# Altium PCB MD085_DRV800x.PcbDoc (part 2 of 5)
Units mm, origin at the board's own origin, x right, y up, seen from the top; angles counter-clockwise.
Board outline 152.66 x 101.89 mm, 4 copper layers (Top Layer, Mid-Layer 1, Mid-Layer 2, Bottom Layer), stack 2.355 mm thick; 265 components, 148 nets, 849 pads, 1494 vias.
Unrouted connection lines stored in the file: 2.

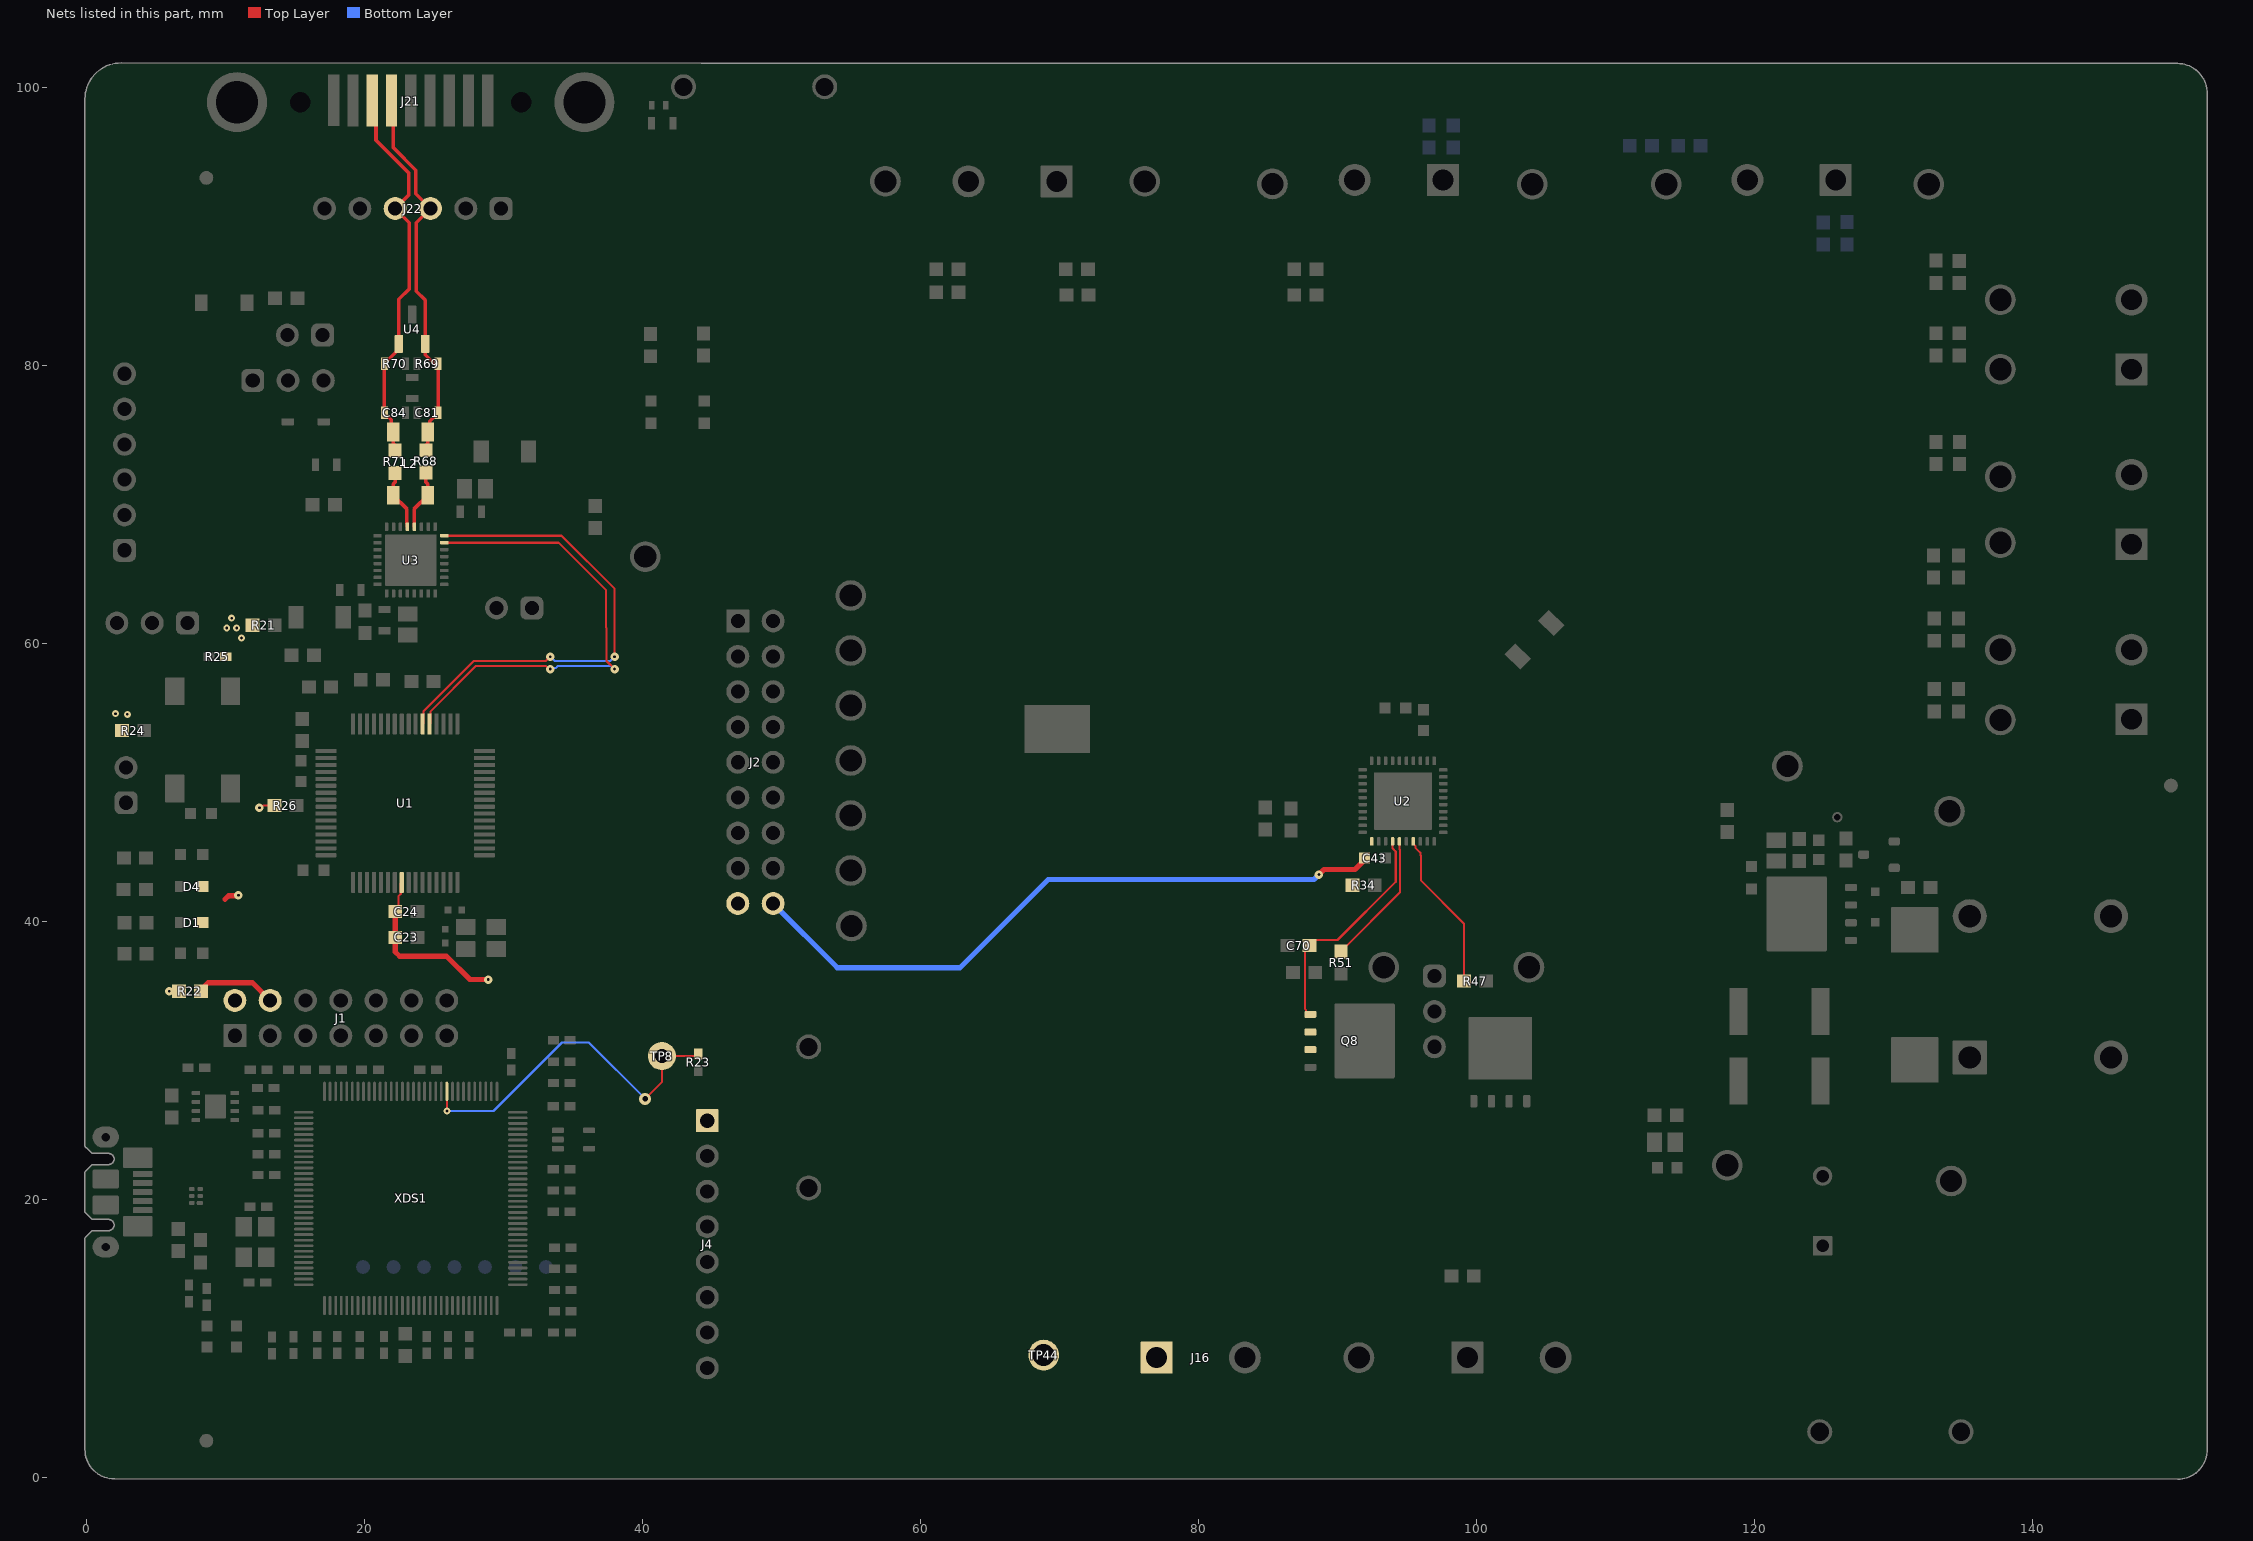
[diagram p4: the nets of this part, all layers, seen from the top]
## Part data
C1 C15: library part CMP-0006906-5, "CAP, CERM, 2.2 uF, 10 V, +/- 10%, X5R, 0603", Cap_Case=0603, Manufacturer=Kemet, Supplier Part Number 1=399-4911-1-ND, TempCo=X5R, Tolerance_%=10%, Value1=Unknown, Value2=10V, ValueDisplayed=2.2uF
C2: library part CMP-0006688-2, "CAP, CERM, 3300 pF, 50 V, +/- 10%, X7R, 0402", Cap_Case=0402, Manufacturer=MuRata, Supplier Part Number 1=490-3248-1-ND, TempCo=X7R, Tolerance_%=10%, Value1=Unknown, Value2=50V, ValueDisplayed=3300pF
C3 C10 C13 C17: library part CMP-0006276-2, "CAP, CERM, 1 uF, 25 V, +/- 10%, X5R, 0402", Cap_Case=0402, Manufacturer=TDK, Supplier Part Number 1=445-9066-1-ND, TempCo=X5R, Tolerance_%=10%, Value1=Unknown, Value2=25V, ValueDisplayed=1uF
C4: library part CMP-0006341-2, "CAP, CERM, 2.2 uF, 6.3 V, +/- 10%, X5R, 0402", Cap_Case=0402, Manufacturer=Samsung, Supplier Part Number 1=1276-1172-1-ND, TempCo=X5R, Tolerance_%=10%, Value1=Unknown, Value2=6.3V, ValueDisplayed=2.2uF
C5 C6 C7 C14 C20: library part CMP-0006658-2, "CAP, CERM, 0.01 uF, 25 V, +/- 10%, X7R, 0402", Cap_Case=0402, Manufacturer=MuRata, Supplier Part Number 1=490-1312-1-ND, TempCo=X7R, Tolerance_%=10%, Value1=Unknown, Value2=25V, ValueDisplayed=0.01uF
C8 C9 C11 C12 C16 C21 C22: library part CMP-0006623-2, "CAP, CERM, 0.1 uF, 6.3 V, +/- 10%, X7R, 0402", Cap_Case=0402, Manufacturer=MuRata, Supplier Part Number 1=GRM155R70J104KA01D-ND, TempCo=X7R, Tolerance_%=10%, Value1=Unknown, Value2=6.3V, ValueDisplayed=0.1uF
C18 C19: library part CMP-0006415-2, "CAP, CERM, 12 pF, 50 V, +/- 5%, C0G/NP0, 0402", Cap_Case=0402, Manufacturer=MuRata, Supplier Part Number 1=14T3292, TempCo=C0G/NP0, Tolerance_%=5%, Value1=Unknown, Value2=50V, ValueDisplayed=12pF
C23: library part CMP-0860569-1, "CAP, CERM, 10 µF, 25 V,+/- 10%, X5R, 0603", Cap_Case=0603, Manufacturer=MuRata, TempCo=X5R, Tolerance_%=10%, Value2=25V, ValueDisplayed=10µF
C24 C34 C37: library part CMP-0006837-4, "CAP, CERM, 0.1 uF, 50 V, +/- 10%, X7R, 0603", Cap_Case=0603, Manufacturer="Wurth Elektronik", TempCo=X7R, Tolerance_%=10%, Value1=Unknown, Value2=50V, ValueDisplayed=0.1uF
C25: library part CMP-0119380-1, "WCAP-CSGP Multilayer Ceramic Chip Capacitor, General Purpose, size 0603, X7R Class II, 470nF, 25VDC", Capacitance Tolerance=+/-10%, Case/Size Code=0603, Insulation Resistance=1.1GOhm, Manufacturer="Wurth Elektronik", Operating Temperature Max=125°C, Operating Temperature Min=-55°C, Rated Voltage (DC)=25V
C26: library part CMP-0104705-1, "WCAP-CSGP Multilayer Ceramic Chip Capacitor, General Purpose, size 0603, X7R, 10nF, 25VDC", Capacitance Tolerance=+/-10%, Case/Size Code=0603, Insulation Resistance=10GOhm, Manufacturer="Wurth Elektronik", Operating Temperature Max=125°C, Operating Temperature Min=-55°C, Rated Voltage (DC)=25V
C27: library part CMP-0115494-1, "WCAP-CSGP Multilayer Ceramic Chip Capacitor, General Purpose, size 0603, X7R, 1µF, 50VDC", Capacitance Tolerance=+/-10%, Case/Size Code=0603, Insulation Resistance=0.5GOhm, Manufacturer="Wurth Elektronik", Operating Temperature Max=125°C, Operating Temperature Min=-55°C, Rated Voltage (DC)=50V
C28 C29: library part CMP-0050268-1, "WCAP-CSGP Multilayer Ceramic Chip Capacitor, General Purpose, size 0402, NP0, 22pF, 50VDC", Capacitance Tolerance=+/-5%, Case/Size Code=0402, Insulation Resistance=10GOhm, Manufacturer="Wurth Elektronik", Operating Temperature Max=125°C, Operating Temperature Min=-55°C, Rated Voltage (DC)=50V
C33 C36: library part CMP-0750039-1, "CAP, CERM, 0.01 µF, 50 V,+/- 10%, X7R, 0603", Cap_Case=0603, Manufacturer="Wurth Elektronik", TempCo=X7R, Tolerance_%=10%, Value2=50V, ValueDisplayed=0.01µF
C35 C38: library part CMP-0007696-2, "CAP, CERM, 1 uF, 50 V, +/- 10%, X7R, 0805", Cap_Case=0805, Manufacturer="Wurth Elektronik", Supplier Part Number 1=710-885012207103, TempCo=X7R, Tolerance_%=10%, Value1=Unknown, Value2=50V, ValueDisplayed=1uF
C39: library part CMP-0087013-2, "Electrolytic Capacitor, 330 uF, 50 V, WCAP-ATG5 Series, 20%, Radial Leaded, 10 mm", Manufacturer="Wurth Electronics", Tolerance_%=20%, ValueDisplayed=330uF
C43 C46: library part CMP-0108290-1, "WCAP-CSGP Multilayer Ceramic Chip Capacitor, General Purpose, size 0603, X7R, 1µF, 25VDC", Capacitance Tolerance=+/-10%, Case/Size Code=0603, Insulation Resistance=0.5GOhm, Manufacturer="Wurth Elektronik", Operating Temperature Max=125°C, Operating Temperature Min=-55°C, Rated Voltage (DC)=25V
C44: library part CMP-0081454-1, "CAP, CERM, 10 µF, 50 V,+/- 20%, X5R, 1206", Cap_Case=1206, Manufacturer="Wurth Elektronik", TempCo=X5R, Tolerance_%=20%, Value2=50V, ValueDisplayed=10µF
C45: library part CMP-0108322-1, "WCAP-CSGP Multilayer Ceramic Chip Capacitor, General Purpose, size 0603, X7R, 100nF, 100VDC", Capacitance Tolerance=+/-10%, Case/Size Code=0603, Insulation Resistance=1GOhm, Manufacturer="Wurth Elektronik", Operating Temperature Max=125°C, Operating Temperature Min=-55°C, Rated Voltage (DC)=100V
C49 C50 C51 C52 C53 C54 C55 C56 C57 C58 C59 C60 C61 C64 C65 C66 C71 C72 C73 C87 C88 C89 C90 C91 C92: library part CMP-0006836-4, "CAP, CERM, 0.022 uF, 50 V, +/- 10%, X7R, 0603", Cap_Case=0603, Manufacturer="Wurth Elektronik", TempCo=X7R, Tolerance_%=10%, Value1=Unknown, Value2=50V, ValueDisplayed=0.022uF
C68: library part CMP-0079993-1, "CAP, CERM, 0.01 µF, 100 V,+/- 10%, X7R, 0603", Cap_Case=0603, Manufacturer="Wurth Elektronik", Supplier Part Number 1=45AC8565, TempCo=X7R, Tolerance_%=10%, Value2=100V, ValueDisplayed=0.01µF
C69: library part CMP-0080094-1, "CAP, CERM, 5100 pF, 50 V,+/- 5%, C0G/NP0, 0603", Cap_Case=0603, Manufacturer=Kemet, Supplier Part Number 1=399-9975-1-ND, TempCo=C0G/NP0, Tolerance_%=5%, Value2=50V, ValueDisplayed=5100pF
C70: library part CMP-0074687-3, "CAP, CERM, 0.22 µF, 10 V,+/- 10%, X7R, 0603", Cap_Case=0603, Manufacturer="Wurth Elektronik", Supplier Part Number 1=732-7941-1-ND, TempCo=X7R, Tolerance_%=10%, Value2=10V, ValueDisplayed=0.22µF
C74 C77 C79: library part CMP-0007044-5, "CAP, CERM, 0.1 uF, 50 V, +/- 10%, X7R, 0603", Cap_Case=0603, Manufacturer=TDK, Supplier Part Number 1=445-1314-1-ND, TempCo=X7R, Tolerance_%=10%, Value1="0.0296 ohm", Value2=50V, ValueDisplayed=0.1uF
C75 C83: library part CMP-0080701-1, "CAP, CERM, 4.7 µF, 16 V,+/- 10%, X7R, AEC-Q200 Grade 1, 0805", Cap_Case=0805, Manufacturer=TDK, Supplier Part Number 1=445-8788-1-ND, TempCo=X7R, Tolerance_%=10%, Value2=16V, ValueDisplayed=4.7µF
C76 C78: library part CMP-0008802-2, "CAP, CERM, 10 uF, 50 V, +/- 10%, X7R, 1206", Cap_Case=1206, Manufacturer=Samsung, Supplier Part Number 1=1276-6767-1-ND, TempCo=X7R, Tolerance_%=10%, Value1=Unknown, Value2=50V, ValueDisplayed=10uF
C80: library part CMP-0006776-4, "CAP, CERM, 220 pF, 50 V, +/- 1%, C0G/NP0, 0603", Cap_Case=0603, Manufacturer=AVX, Supplier Part Number 1=478-3719-1-ND, TempCo=C0G/NP0, Tolerance_%=1%, Value1="0.083 ohm", Value2=50V, ValueDisplayed=220pF
C81 C84: library part CMP-0007253-4, "CAP, CERM, 20 pF, 100 V, +/- 5%, C0G/NP0, 0603", Cap_Case=0603, Manufacturer=MuRata, Supplier Part Number 1=490-1334-1-ND, TempCo=C0G/NP0, Tolerance_%=5%, Value1=Unknown, Value2=100V, ValueDisplayed=20pF
C82: library part CMP-0006746-5, "CAP, CERM, 4700 pF, 100 V, +/- 10%, X7R, 0603", Cap_Case=0603, Manufacturer=AVX, Supplier Part Number 1=478-1203-1-ND, TempCo=X7R, Tolerance_%=10%, Value1="0.136 ohm", Value2=100V, ValueDisplayed=4700pF
C85: library part CMP-0006977-4, "CAP, CERM, 0.01 uF, 100 V, +/- 10%, X7R, 0603", Cap_Case=0603, Manufacturer=Kemet, Supplier Part Number 1=399-5347-1-ND, TempCo=X7R, Tolerance_%=10%, Value1=Unknown, Value2=100V, ValueDisplayed=0.01uF
D1 D2 D3 D6 D7 D10: library part CMP-0002894-2, "LED, Green, SMD", Color=green, Manufacturer="Wurth Elektronik", Value1=W, Value2=2V
D4: library part CMP-0002947-3, "LED, Red, SMD", Color=Red, Manufacturer="Wurth Elektronik", Power_TotalModule=72mW, Value1=0.072W, Value2=2V
D5: library part CMP-0079597-2, "Diode, Switching, 75 V, 0.15 A, AEC-Q101, SOD-323", Manufacturer="Diodes Inc.", Value1=0.15A, Value2=1.25V
D8: library part CMP-0076974-2, "Diode, Switching, 100 V, 0.15 A, SOD-123", Manufacturer="Micro Commercial Components", Value1=0.15A, Value2=1.25V
D9: library part CMP-0098376-1, "24-V, 1-Channel ESD Protection Diode", Breakdown Voltage=25.5V, Clamping Voltage=40V, Digikey Part Number=296-ESD1LIN24DYFRCT-ND, Manufacturer="Texas Instruments", Mouser Part Number=595-ESD1LIN24DYFR, Operating Temperature Range="-55°C to +150°C", ValueDisplayed=2.3pF
F1: library part CMP-0077200-3, "Fuse, 30 A, 250 VAC, 100 VDC, SMD", Irating_A=30A, Manufacturer=Littelfuse, Supplier Part Number 1=F6439CT-ND
FID1 FID2 FID3: library part CMP-0077181-1, "Fiducial mark.  There is nothing to buy or mount.", Manufacturer=N/A
H1 H2 H3 H4: library part CMP-0003620-1, "Bumpon, Hemisphere, 0.44 X 0.20, Clear", Manufacturer=3M, Supplier Part Number 1=SJ5303-7-ND
IC1: library part CMP-0043115-3, "4-Channel ESD Protection Array for High-Speed Data Interfaces, DRY0006A (USON-6)", Breakdown Voltage(Min)(V)=6, IO Capacitance(Typ)(pF)=1.6, IO Leakage Current(nA)=1, Manufacturer="Texas Instruments", Operating Temperature Range="-40 to 85 C", Rating=Catalog
IC2: library part CMP-0036329-3, "500mA, Adjustable, Low Quiescent Current, Low-Noise, High-PSRR, Single-Output LDO Regulator, DRB0008A (VSON-8)", Manufacturer="Texas Instruments", Operating Temperature Range="-40 to 125 C", Rating=Catalog
IC3: library part CMP-0032790-2, "Precision Micropower Shunt Voltage Reference, 0.5% accuracy, 2.5 V, 15 ppm / degC, 15 mA, -40 to 85 degC, 5-pin SC70 (DCK), Green (RoHS & no Sb/Br)", Manufacturer="Texas Instruments", Rating=Catalog, Temp Coeff(Max)(ppm/ degree C)=100, Temp Coeff(Typ)(ppm/ degree C)=15
J1: library part CMP-0075415-2, "Header, 100mil, 7x2, Gold, TH", Color=Black, Current_A=6.3A, Manufacturer=Samtec, Supplier Part Number 1=SAM1028-07-ND, Voltage_V=550V
J2: library part CMP-0075464-1, "Header, 100mil, 9x2, Gold, TH", Color=Black, Current_A=6.3A, Manufacturer=Samtec, Supplier Part Number 1=SAM1028-09-ND, Voltage_V=550V
J3 J18 J20: library part CMP-0075405-3, "Header, 100mil, 2x1, Gold, TH", Color=Black, Current_A=6.3A, Manufacturer=Samtec, Supplier Part Number 1=SAM1029-02-ND, Voltage_V=550V
J4: library part CMP-0075419-2, "Header, 100mil, 8x1, Gold, TH", Color=Black, Current_A=6.3A, Manufacturer=Samtec, Supplier Part Number 1=SAM1029-08-ND, Voltage_V=550V
J5: library part CMP-0086764-1, "2 Position Wire to Board Terminal Block Horizontal with Board 0.400\" (10.16mm) Through Hole", Current_A=57A, Manufacturer=Wurth, Voltage_V=750V
J6 J7 J8 J9 J16: library part CMP-0093233-2, "2 Position Wire to Board Terminal Block Horizontal with Board 0.250\" (6.35mm) Through Hole", Current_A=32A, Digikey Part Number=732-691250610002-ND, Manufacturer="Wurth Electronics", Mouser Part Number=710-691250610002, Operating Temperature Range="-32°C to +120°C", Voltage_V=450V
J10 J11 J12: library part CMP-0096350-1, "2 Position Wire to Board Terminal Block Horizontal with Board 0.197\" (5.00mm) Through Hole", Current_A=14A, Digikey Part Number=732-691216710002-ND, Manufacturer="Wurth Electronics", Mouser Part Number=710-691216710002, Operating Temperature Range="-30°C to +120°C", Voltage_V=300V
J13 J19 J23: library part CMP-0075407-2, "Header, 100mil, 3x1, Gold, TH", Color=Black, Current_A=6.3A, Manufacturer=Samtec, Supplier Part Number 1=SAM1029-03-ND, Voltage_V=550V
J17 J22: library part CMP-0075413-2, "Header, 100mil, 6x1, Gold, TH", Color=Black, Current_A=6.3A, Manufacturer=Samtec, Supplier Part Number 1=SAM1029-06-ND, Voltage_V=550V
J21: library part CMP-0074875-1, "Receptacle, D-Sub, 9 Position, R/A, SMT", Color=Black, Manufacturer=NorComp, Supplier Part Number 1=190-09FA-ND
L1: library part CMP-0087162-1, "FIXED IND 2.2UH 16A 2.2 MOHM", Manufacturer="Wurth Electronics"
L2: library part CMP-0062430-2, "Inductor, Ferrite, 100 uH, 0.15 A, 2 ohm, SMD", Manufacturer=TDK, Supplier Part Number 1=445-3959-1-ND, Value1="2 ohm", Value2=0.15A, ValueDisplayed=100uH
LBL1: library part CMP-0003625-1, "Thermal Transfer Printable Labels, 0.650\" W x 0.200\" H - 10,000 per roll", Manufacturer=Brady, Supplier Part Number 1=97C5133
LED1: library part CMP-0078131-2, "LED, Red, SMD", Color=Red, Manufacturer=Lite-On, Power_TotalModule=62.5mW, Value1=.0625W, Value2=2V
LED2: library part CMP-0002827-3, "LED, Green, SMD", Color=green, Manufacturer=Lite-On, Power_TotalModule=100mW, Value1=0.1W, Value2=2.1V
Logo1: library part CMP-0074844-1
Logo2: library part CMP-0074838-1, "Texas Instrument Corporate Signature"
Logo3: library part CMP-0074847-1, "FCC_disclaimer"
Logo4: library part CMP-0074769-3, Manufacturer="Texas Instruments"
LOGO5 LOGO7: library part CMP-0074837-2, "IEC 61010-1 Hot Surface Warning", Manufacturer="Texas Instruments"
Logo6: library part CMP-0074836-1, "IEC 61010-1 Caution Warning"
Q1: library part CMP-0000375-2, "Transistor, NPN, 65 V, 0.1 A, SOT-23", Manufacturer="ON Semiconductor", Supplier Part Number 1=BC846BLT1GOSCT-ND, Value1="0.1 A", Value2=450
Q4 Q8: library part CMP-0000713-2, "MOSFET, N-CH, 40 V, 100 A, DNK0008A (VSON-CLIP-8)", Alternate Manufacturer=None, Manufacturer="Texas Instruments", Supplier Part Number 1=CSD18512Q5B-ND, Value1=0.002, Value2="37 nC"
Q7: library part CMP-0000594-1, "MOSFET, N-CH, 30 V, 25 A, DQJ0008A (VSONP-8)", Alternate Manufacturer=None, Manufacturer="Texas Instruments", Supplier Part Number 1=CSD17579Q5A-ND, Value1=0.013, Value2="11.6 nC"
R1: library part CMP-0026731-1, "RES, 330 k, 1%, 0.0625 W, 0402", Manufacturer="Yageo America", Power_W=62.5mW, Supplier Part Number 1=311-330KLRCT-ND, TempCo="100 ppm/C", Tolerance_%=1%, Value2=0.0625W, Value_Code=330k
R2 R5 R68 R71: library part CMP-0025885-5, "RES, 0, 5%, 0.1 W, 0603", Manufacturer=Yageo, Power_W=100mW, Supplier Part Number 1=311-0.0GRCT-ND, TempCo="200 ppm/C", Tolerance_%=5%, Value2=0.1W, Value_Code=0000, ValueDisplayed=0
R3: library part CMP-0026728-1, "RES, 220 k, 1%, 0.0625 W, 0402", Manufacturer="Yageo America", Power_W=62.5mW, Supplier Part Number 1=311-220KLRCT-ND, TempCo="100 ppm/C", Tolerance_%=1%, Value2=0.0625W, Value_Code=220k
R4: library part CMP-0026695-1, "RES, 3.30 k, 1%, 0.1 W, AEC-Q200 Grade 0, 0402", Manufacturer=Panasonic, Power_W=100mW, Supplier Part Number 1=P3.30KLCT-ND, TempCo="100 ppm/C", Tolerance_%=1%, Value2=0.1W, Value_Code=3k30, ValueDisplayed=3.30k
R6: library part CMP-0026100-2, "RES, 1.00 M, 1%, 0.063 W, AEC-Q200 Grade 0, 0402", Manufacturer=Vishay-Dale, Power_W=63mW, Supplier Part Number 1=541-1.00MLCT-ND, TempCo="100 ppm/C", Tolerance_%=1%, Value2=0.063W, Value_Code=1M00, ValueDisplayed=1.00M
R7 R8 R14: library part CMP-0026825-5, "RES, 10 k, 5%, 0.063 W, AEC-Q200 Grade 0, 0402", Manufacturer=Vishay-Dale, Power_W=63mW, Supplier Part Number 1=541-10KJCT-ND, TempCo="200 ppm/C", Tolerance_%=5%, Value2=0.063W, Value_Code=10k0, ValueDisplayed=10k
R9 R10 R11 R12 R17: library part CMP-0026852-3, "RES, 1.0 k, 5%, 0.063 W, AEC-Q200 Grade 0, 0402", Manufacturer=Vishay-Dale, Power_W=63mW, Supplier Part Number 1=541-1.0KJCT-ND, TempCo="200 ppm/C", Tolerance_%=5%, Value2=0.063W, Value_Code=1k00, ValueDisplayed=1.0k
R13 R16: library part CMP-0026824-3, "RES, 100, 5%, 0.063 W, AEC-Q200 Grade 0, 0402", Manufacturer=Vishay-Dale, Power_W=63mW, Supplier Part Number 1=541-100JCT-ND, TempCo="200 ppm/C", Tolerance_%=5%, Value2=0.063W, Value_Code=100R, ValueDisplayed=100
R15: library part CMP-0026413-2, "RES, 4.87 k, 1%, 0.063 W, AEC-Q200 Grade 0, 0402", Manufacturer=Vishay-Dale, Power_W=63mW, Supplier Part Number 1=541-4.87KLCT-ND, TempCo="100 ppm/C", Tolerance_%=1%, Value2=0.063W, Value_Code=4k87, ValueDisplayed=4.87k
R18: library part CMP-0026946-3, "RES, 51, 5%, 0.063 W, AEC-Q200 Grade 0, 0402", Manufacturer=Vishay-Dale, Power_W=63mW, Supplier Part Number 1=541-51JCT-ND, TempCo="200 ppm/C", Tolerance_%=5%, Value2=0.063W, Value_Code=51R0, ValueDisplayed=51
R19 R20: library part CMP-0026934-3, "RES, 470, 5%, 0.063 W, AEC-Q200 Grade 0, 0402", Manufacturer=Vishay-Dale, Power_W=63mW, Supplier Part Number 1=541-470JCT-ND, TempCo="200 ppm/C", Tolerance_%=5%, Value2=0.063W, Value_Code=470R, ValueDisplayed=470
R21 R22 R26 R27 R34 R64: library part CMP-0025885-5, "RES, 0, 5%, 0.1 W, 0603", Manufacturer=Yageo, PartNumber=RC0603JR-070RL, Power_W=100mW, Supplier Part Number 1=311-0.0GRCT-ND, TempCo="200 ppm/C", Tolerance_%=5%, Value2=0.1W, Value_Code=0000, ValueDisplayed=0
R23 R25: library part CMP-0026935-3, "RES, 47 k, 5%, 0.063 W, AEC-Q200 Grade 0, 0402", Manufacturer=Vishay-Dale, Power_W=63mW, Supplier Part Number 1=541-47KJCT-ND, TempCo="200 ppm/C", Tolerance_%=5%, Value2=0.063W, Value_Code=47k0, ValueDisplayed=47k
R24 R43 R73 R74: library part CMP-0025918-5, "RES, 3.3 k, 5%, 0.1 W, 0603", Manufacturer=Yageo, Power_W=100mW, Supplier Part Number 1=311-3.3KGRCT-ND, TempCo="100 ppm/C", Tolerance_%=5%, Value2=0.1W, Value_Code=3k30, ValueDisplayed=3.3k
R28 R29 R30 R31 R63: library part CMP-0025912-5, "RES, 330, 5%, 0.1 W, 0603", Manufacturer=Yageo, Power_W=100mW, Supplier Part Number 1=311-330GRCT-ND, TempCo="100 ppm/C", Tolerance_%=5%, Value2=0.1W, Value_Code=330R, ValueDisplayed=330
R32 R33 R67: library part CMP-0025886-5, "RES, 10 k, 5%, 0.1 W, 0603", Manufacturer=Yageo, Power_W=100mW, Supplier Part Number 1=311-10KGRCT-ND, TempCo="100 ppm/C", Tolerance_%=5%, Value2=0.1W, Value_Code=10k0, ValueDisplayed=10k
R44: library part CMP-0025891-5, "RES, 16 k, 5%, 0.1 W, 0603", Manufacturer=Yageo, Power_W=100mW, Supplier Part Number 1=311-16KGRCT-ND, TempCo="100 ppm/C", Tolerance_%=5%, Value2=0.1W, Value_Code=16k0, ValueDisplayed=16k
R47 R65: library part CMP-0025899-5, "RES, 1.0 k, 5%, 0.1 W, 0603", Manufacturer=Yageo, Power_W=100mW, Supplier Part Number 1=311-1.0KGRCT-ND, TempCo="100 ppm/C", Tolerance_%=5%, Value2=0.1W, Value_Code=1k00, ValueDisplayed=1.0k
R51: library part CMP-0022918-5, "RES, 220, 1%, 0.1 W, 0603", Manufacturer=Yageo, Power_W=100mW, Supplier Part Number 1=311-220HRCT-ND, TempCo="100 ppm/C", Tolerance_%=1%, Value2=0.1W, Value_Code=220R, ValueDisplayed=220
R57: library part CMP-0022895-5, "RES, 1.00 k, 1%, 0.1 W, 0603", Manufacturer=Yageo, Power_W=100mW, Supplier Part Number 1=311-1.00KHRCT-ND, TempCo="100 ppm/C", Tolerance_%=1%, Value2=0.1W, Value_Code=1k00, ValueDisplayed=1.00k
R62: library part CMP-0025930-5, "RES, 560, 5%, 0.1 W, 0603", Manufacturer=Yageo, Power_W=100mW, Supplier Part Number 1=311-560GRCT-ND, TempCo="100 ppm/C", Tolerance_%=5%, Value2=0.1W, Value_Code=560R, ValueDisplayed=560
R66 R75: library part CMP-0078790-1, "RES, 0, 0.05%, 2 W, AEC-Q200 Grade 0, 2512", Manufacturer="Stackpole Electronics Inc", Power_W=2W, Supplier Part Number 1=HCJ2512ZT0R00CT-ND, Tolerance_%=0.05%, Value_Code=0
R69 R70: library part CMP-0023213-5, "RES, 60.4, 1%, 0.1 W, 0603", Manufacturer=Yageo, Power_W=100mW, Supplier Part Number 1=311-60.4HRCT-ND, TempCo="100 ppm/C", Tolerance_%=1%, Value2=0.1W, Value_Code=60R4, ValueDisplayed=60.4
R72: library part CMP-0026660-1, "RES, 1.00 M, 1%, 0.1 W, 0402", Manufacturer=Panasonic, Power_W=100mW, Supplier Part Number 1=P1.00MLCT-ND, TempCo="100 ppm/C", Tolerance_%=1%, Value2=0.1W, Value_Code=1M00, ValueDisplayed=1.00M
R76: library part CMP-0025900-5, "RES, 20 k, 5%, 0.1 W, 0603", Manufacturer=Yageo, Power_W=100mW, Supplier Part Number 1=311-20KGRCT-ND, TempCo="100 ppm/C", Tolerance_%=5%, Value2=0.1W, Value_Code=20k0, ValueDisplayed=20k
R77: library part CMP-0025898-5, "RES, 1.8 k, 5%, 0.1 W, 0603", Manufacturer=Yageo, Power_W=100mW, Supplier Part Number 1=311-1.8KGRCT-ND, TempCo="100 ppm/C", Tolerance_%=5%, Value2=0.1W, Value_Code=1k80, ValueDisplayed=1.8k
S1: library part CMP-0097347-1, "Tactile Switch SPST-NO Top Actuated Surface Mount", Coil Resistance_ohm=100mΩ, Contact Current Rating=50mA, Digikey Part Number=732-7022-1-ND, Manufacturer="Wurth Electronics", Mouser Part Number=710-430481025816, Operating Force=160gf, Operating Temperature Range="-40°C to +85°C"
SH1 SH2 SH3: library part CMP-0075110-1, "1mm Uninsulated Shorting Plug, 10.16mm spacing, TH", Manufacturer=Harwin, PartNumber=D3082-05, Supplier Part Number 1=952-1873-ND
SH-J1 SH-J2 SH-J3 SH-J4 SH-J5 SH-J6 SH-J7 SH-J8 SH-J9 SH-J10 SH-J14 SH-J15 SH-J16 SH-J17 SH-J18 SH-J19 SH-J20 SH-J21: library part CMP-0003761-2, "Shunt, 2.54mm, Gold, Black", Manufacturer="Wurth Elektronik", Supplier Part Number 1=732-2678-ND
TP1 TP2 TP3 TP4 TP5 TP6 TP7: library part CMP-0003825-1, "1mm Test Point, SMT", Manufacturer=Any, PartNumber=TP_SM_1MM
TP8: library part CMP-0055139-2, "Test Point, Miniature, White, TH", Color=White, Manufacturer="Keystone Electronics", Supplier Part Number 1=36-5002-ND
TP10 TP11 TP12 TP13 TP14 TP15 TP19 TP31 TP32 TP33 TP34 TP35 TP36 TP37 TP38 TP39 TP40 TP41 TP42 TP44 TP46 TP47 TP48 TP49: library part CMP-0055149-2, "Test Point, Multipurpose, White, TH", Color=White, Manufacturer="Keystone Electronics", Supplier Part Number 1=36-5012-ND
TP16: library part CMP-0055153-2, "Test Point, Compact, SMT", Manufacturer="Keystone Electronics", Supplier Part Number 1=36-5016TR-ND
TP20 TP21: library part CMP-0055147-2, "Test Point, Multipurpose, Red, TH", Color=Red, Manufacturer="Keystone Electronics", Supplier Part Number 1=36-5010-ND
TP25 TP26: library part CMP-0055148-2, "Test Point, Multipurpose, Black, TH", Color=Black, Manufacturer="Keystone Electronics", Supplier Part Number 1=36-5011-ND
TP30: library part CMP-0003719-1, "Testpoint", Manufacturer="Texas Instruments"
U1: library part CMP-0093960-1, "Mixed-Signal Microcontrollers With CAN-FD Interface LQFP64", Frequency_Fixed=80MHz, Manufacturer="Texas Instruments", Max Supply Voltage=3.6V, Min Supply Voltage=1.62V, Operating Temperature Range="-40°C to +125°C"
U2: library part CMP-0121851-2, "Automotive Multi-function Driver with Integrated Half-bridges &HighSide and Current Sensing & Advanced Diagnostics", Manufacturer="Texas Instruments", Max Supply Voltage=35V, Min Supply Voltage=4.5V, Operating Temperature Range="-40°C to +150°C"
U3: library part CMP-0093295-1, "CAN FD and LIN System Basis Chip (SBC) with Integrated Watchdog, Selective Wake and Advanced CAN Bus Fault Diagnostics", Manufacturer="Texas Instruments", Max Supply Voltage=28V, Min Supply Voltage=4.5V, Operating Temperature Range="-40°C to +150°C"
U4: library part CMP-0093261-1, "24-V, 2-Channel ESD Protection Diode for In-Vehicle Networks", Breakdown Voltage=25.5V, Clamping Voltage=32V, Manufacturer="Texas Instruments", Operating Temperature Range="-55°C to +150°C", ValueDisplayed=3pF
USB1: library part CMP-0055311-1, "Receptacle, USB 2.0, Micro B, 5 Position, R/A, SMT", Color=Black, Current_A=1.8A, Manufacturer=Molex, Supplier Part Number 1=WM11263CT-ND, Voltage_V=30V
XDS1: library part CMP-0077954-1, "MSP432E401YTPDT, PDT0128A (TQFP-128)", Alternate Manufacturer="Texas Instruments", Alternate PartNumber=MSP432E401YTPDT
Y1: library part CMP-0004635-3, "Crystal, 16 MHz, 8pF, SMD", Frequency Stability=+/-30ppm, Frequency_Fixed=16MHz, Manufacturer=NDK, Supplier Part Number 1=644-1157-1-ND
Y2: library part CMP-0098168-2, "Crystal 40MHz ±10ppm (Tol) ±20ppm (Stability) 12pF FUND 40Ohm 4-Pin Mini-CSMD T/R", Frequency Stability=20ppm, Frequency Tolerance=10ppm, Frequency_Fixed=40MHz, Load Capacitance=12pF, Manufacturer="Seiko Epson", Operating Temperature Range="-40°C to +105°C"
ZZ1: library part CMP-0003616-3
ZZ2: library part CMP-0077236-1
ZZ3: library part CMP-0077237-1
ZZ4: library part CMP-0077238-1

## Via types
v1: diameter 0.5, hole 0.2, Top Layer to Bottom Layer, tented both sides, 1346 vias
v2: diameter 0.61, hole 0.2, Top Layer to Bottom Layer, tented both sides, 54 vias
v3: diameter 0.508, hole 0.203, Top Layer to Bottom Layer, tented both sides, 46 vias
v4: diameter 0.5, hole 0.2, Top Layer to Bottom Layer, 16 vias
v5: diameter 0.864, hole 0.406, Top Layer to Bottom Layer, tented both sides, 15 vias
v6: diameter 0.711, hole 0.356, Top Layer to Bottom Layer, tented both sides, 10 vias
v7: diameter 5, hole 4.3, Top Layer to Bottom Layer, 3 vias
v8: diameter 0.61, hole 0.203, Top Layer to Bottom Layer, tented both sides, 3 vias
v9: diameter 5, hole 4.5, Top Layer to Bottom Layer, 1 vias

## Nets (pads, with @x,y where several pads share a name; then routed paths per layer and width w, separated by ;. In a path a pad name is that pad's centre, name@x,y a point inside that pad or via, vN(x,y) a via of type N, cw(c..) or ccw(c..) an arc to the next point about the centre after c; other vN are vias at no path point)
3V3: J1.4 R22.1 | length 5.9
  Top Layer w0.381: R22.1@8.13,34.992 8.13,35.017 8.339,35.227 8.364,35.227 8.737,35.6 11.928,35.6 J1.4@13.198,34.33
3V3_MCU: C23.1 C24.1 D1.2 D4.2 J2.17 J4.1 R21.1 R22.2 R24.2 R25.2 R26.1 U1.40 | length 15.8
  Top Layer w0.152: v2(12.426,48.188) 12.55,48.188 12.701,48.339 R26.1@13.596,48.339 ; C24.1@22.195,40.714 22.418,40.937 22.418,41.809 22.588,41.979 22.588,42.051 22.588,42.74 U1.40@22.662,42.814
  Top Layer w0.381: v2(5.945,34.992) R22.2@6.73,34.992 ; 9.953,41.605 10.194,41.846 10.868,41.846 v2(10.912,41.889) ; C24.1@22.195,40.714 22.195,37.822 22.514,37.503 25.887,37.503 27.561,35.828 v2(28.885,35.828)
  other v1: 2.923,54.908 2.075,54.954 11.142,60.397 10.075,61.108 10.787,61.108 10.431,61.82
+5V: J1.2
BSL_INVOKE: R23.2 TP8.1 XDS1.42 | length 25.6
  Top Layer w0.152: XDS1.42@25.907,27.78 25.907,26.389 v1(25.924,26.372) ; v5(40.177,27.246) 41.377,28.446 TP8.1@41.377,30.328 43.82,30.328 R23.2@43.979,30.486
  Bottom Layer w0.152: v1(25.924,26.372) 29.258,26.372 34.19,31.304 36.12,31.304 v5(40.177,27.246)
CAN_RX: U1.6 U3.24 | length 35.3
  Top Layer w0.152: U1.6@24.162,54.214 24.236,54.288 24.236,55.148 27.835,58.747 33.027,58.747 33.335,59.055 v2(33.345,59.055) ; U3.24@25.72,67.753 34.155,67.753 37.972,63.936 v2(37.972,59.055)
  Bottom Layer w0.152: v2(33.345,59.055) 33.355,59.055 33.663,58.747 37.654,58.747 37.962,59.055 v2(37.972,59.055)
CAN_TX: U1.5 U3.23 | length 34.8
  Top Layer w0.152: U1.5@24.662,54.214 24.736,54.288 24.736,55.123 28.007,58.395 33.027,58.395 33.255,58.166 v2(33.345,58.166) ; U3.23@25.72,67.253 33.948,67.253 37.341,63.86 37.341,61.161 37.391,61.11 37.391,58.747 v2(37.972,58.166)
  Bottom Layer w0.152: v2(33.345,58.166) 33.408,58.229 33.731,58.229 33.896,58.395 37.654,58.395 37.883,58.166 v2(37.972,58.166)
CANH: L2.2 R68.1 U3.28 | length 4.4
  Top Layer w0.254: U3.28@23.57,68.403 23.57,68.83 23.545,68.855 23.545,69.673 L2.2@24.541,70.669 24.541,71.471 24.398,71.615 R68.1@24.398,72.342
CANH_BUS: C81.1 J21.7 J22.3 L2.3 R68.2 R69.2 U4.2 | length 27.7
  Top Layer w0.254: J21.7@22.066,99.033 22.066,95.663 23.673,94.056 23.673,92.344 J22.3@24.729,91.288 23.713,90.272 23.713,85.349 24.356,84.705 U4.2@24.356,81.558 24.356,80.781 25.275,79.862 C81.1@25.275,76.608 24.668,76.001 24.668,75.346 L2.3@24.541,75.219 24.541,74.417 24.398,74.274 R68.2@24.398,73.866
CANL: L2.1 R71.1 U3.29 | length 4.4
  Top Layer w0.254: R71.1@22.185,72.318 22.185,71.615 22.041,71.471 L2.1@22.041,70.669 23.037,69.673 23.037,68.644 23.062,68.619 U3.29@23.062,68.403
CANL_BUS: C84.2 J21.2 J22.4 L2.4 R70.1 R71.2 U4.1 | length 28.1
  Top Layer w0.254: J21.2@20.682,99.033 20.809,98.906 20.809,96.202 23.165,93.846 23.165,92.263 J22.4@22.189,91.288 23.205,90.272 23.205,85.501 22.456,84.752 U4.1@22.456,81.558 22.329,81.431 22.329,81.048 R70.1@21.407,80.125 C84.2@21.407,76.608 21.914,76.1 21.914,75.346 L2.4@22.041,75.219 22.041,74.417 22.185,74.274 R71.2@22.185,73.842
DVDD: C43.2 J2.18 R34.2 U2.21 | length 47.8
  Top Layer w0.381: v2(88.633,43.376) 89.005,43.747 91.236,43.747 C43.2@92.032,44.543
  Bottom Layer w0.381: J2.18@49.378,41.297 53.997,36.677 62.812,36.677 69.163,43.029 88.287,43.029 v2(88.633,43.376)
ECDRV: R51.1 U2.25 | length 9.7
  Top Layer w0.152: R51.1@90.233,37.843 90.233,37.868 94.466,42.101 94.466,45.164 94.432,45.198 U2.25@94.432,45.765
ECFB: C70.1 J16.1 Q8.1 Q8.2 Q8.3 TP44.1 U2.24 | length 16.4
  Top Layer w0.152: Q8.1@88.024,33.323 87.878,33.323 87.701,33.5 87.701,33.646 87.641,33.706 87.641,37.943 88.37,38.672 89.97,38.672 94.161,42.863 94.161,45.038 94.027,45.172 94.022,45.172 93.932,45.261 U2.24@93.932,45.765
GH_HS: R47.2 U2.27 | length 11.5
  Top Layer w0.152: U2.27@95.432,45.765 95.432,45.59 95.579,45.443 95.579,45.313 95.932,44.959 95.932,44.865 cw(c95.308,44.65) 95.968,44.65 95.968,42.958 99.077,39.85 R47.2@99.077,35.72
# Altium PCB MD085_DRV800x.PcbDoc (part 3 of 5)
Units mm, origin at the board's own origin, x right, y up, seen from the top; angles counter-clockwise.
Board outline 152.66 x 101.89 mm, 4 copper layers (Top Layer, Mid-Layer 1, Mid-Layer 2, Bottom Layer), stack 2.355 mm thick; 265 components, 148 nets, 849 pads, 1494 vias.
Unrouted connection lines stored in the file: 2.

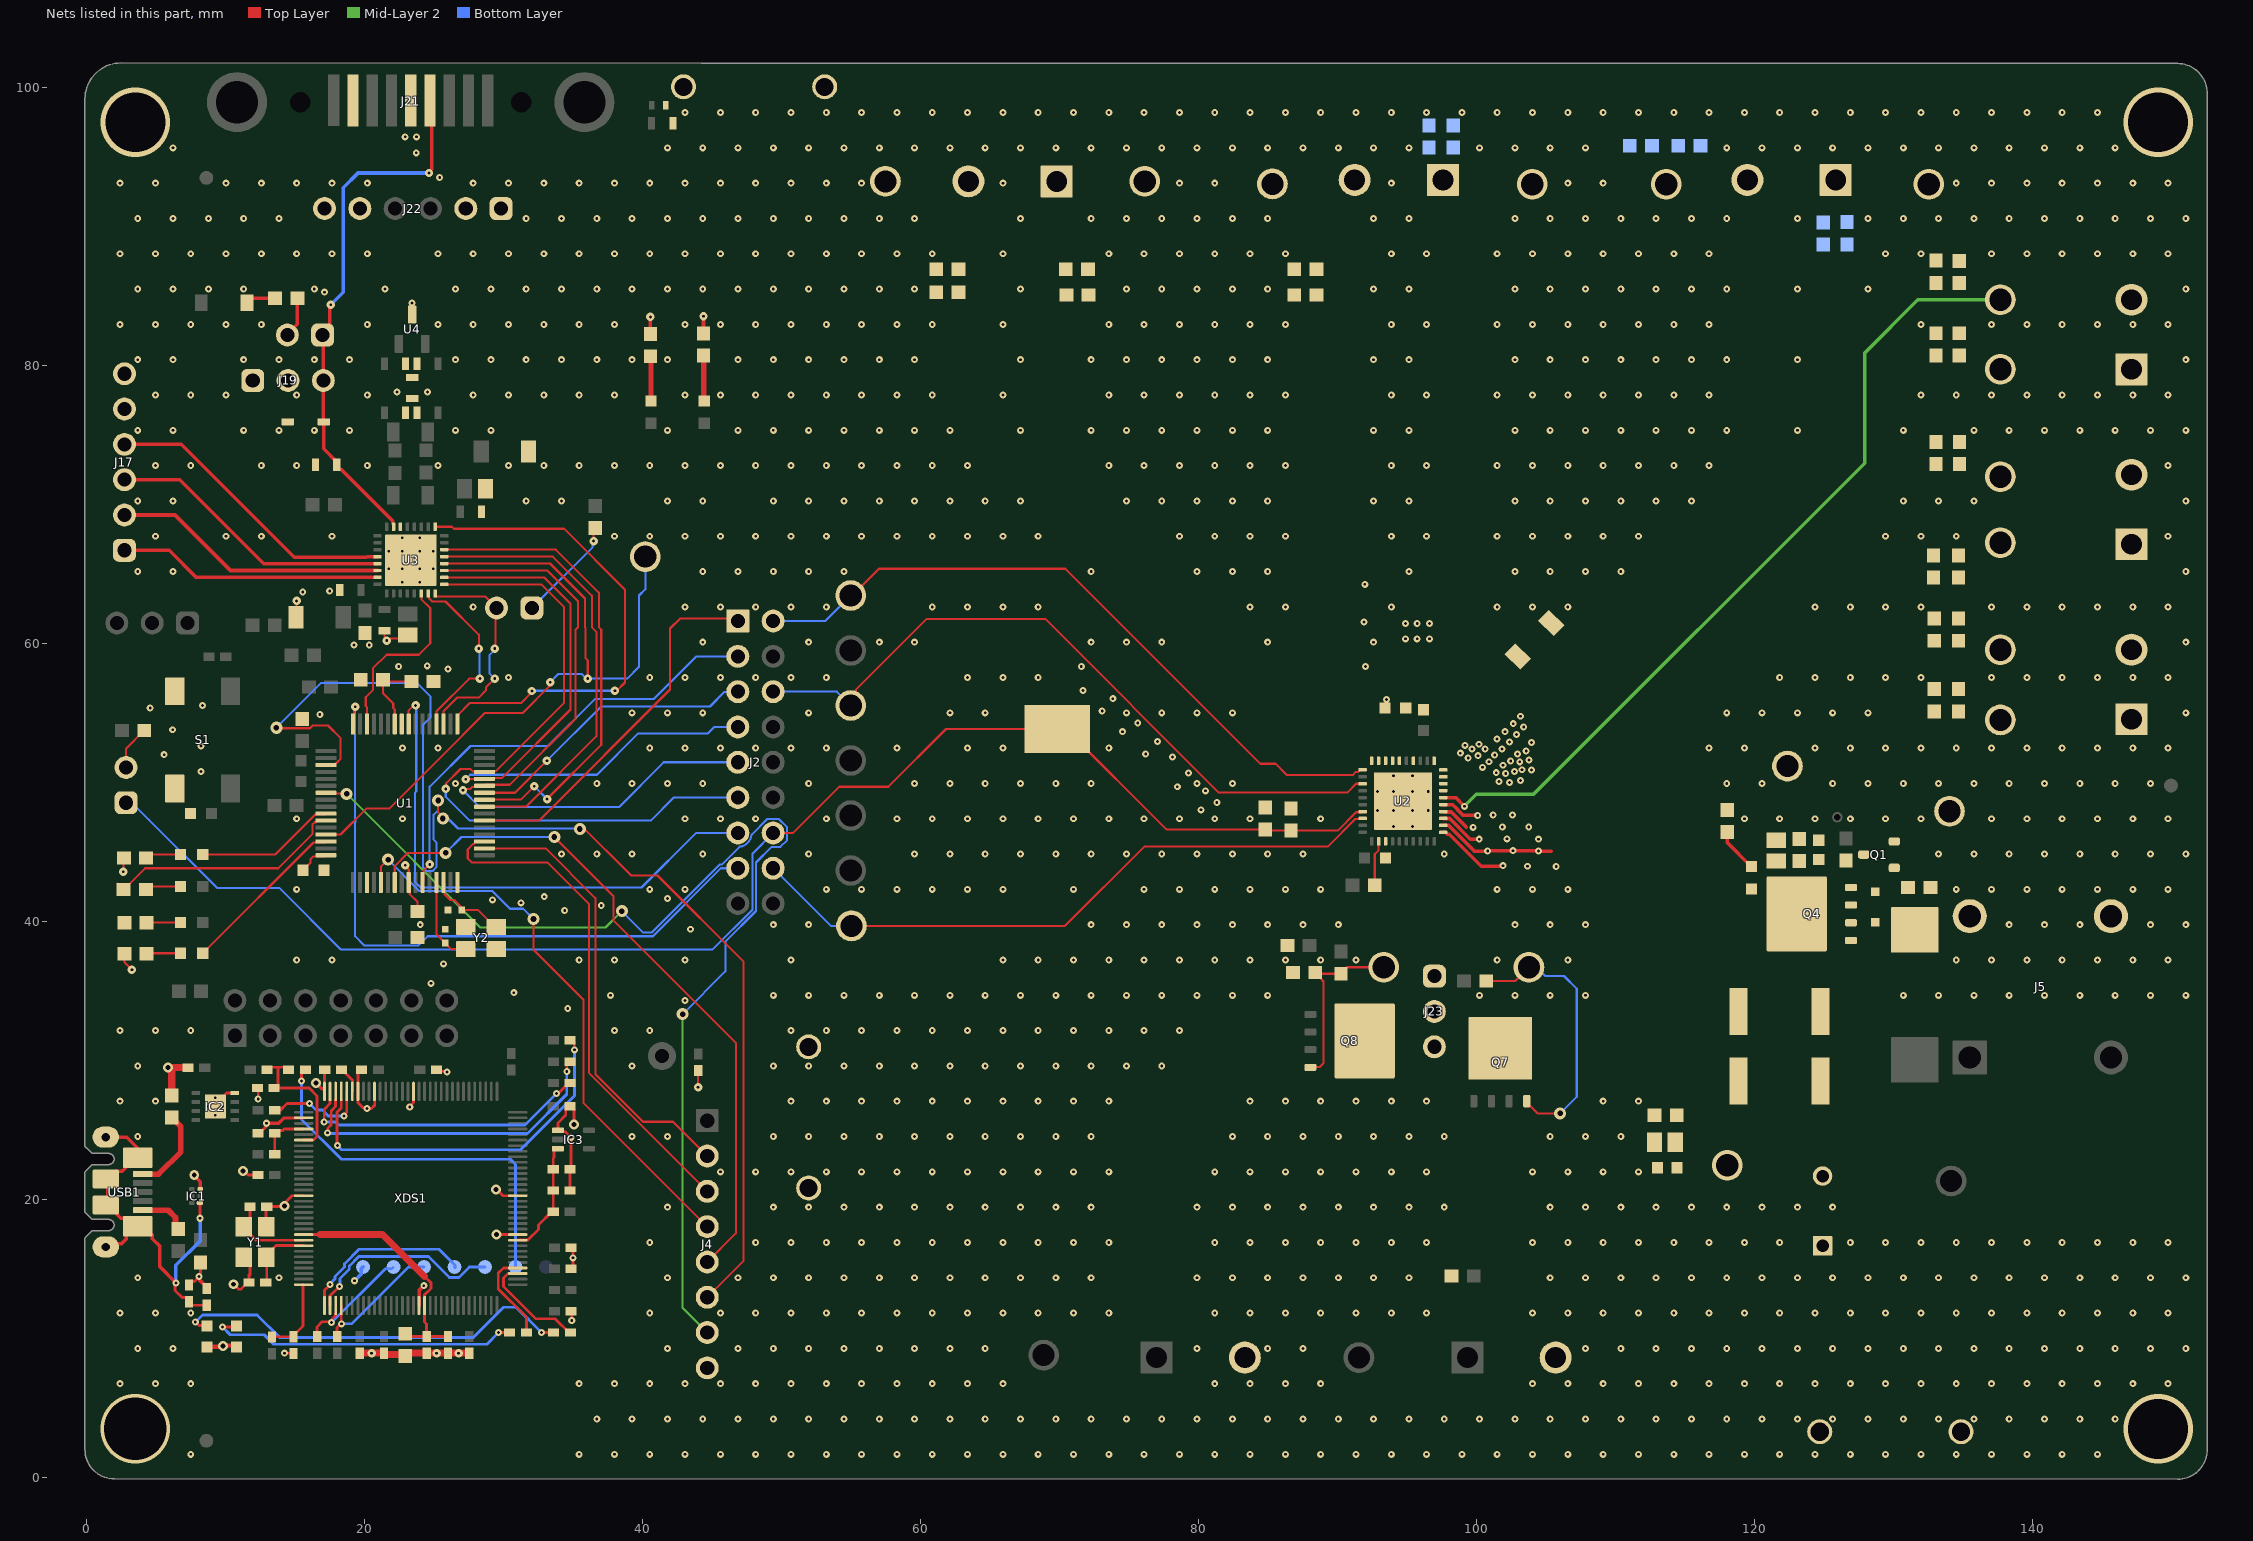
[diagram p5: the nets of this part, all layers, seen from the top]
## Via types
v1: diameter 0.5, hole 0.2, Top Layer to Bottom Layer, tented both sides, 1346 vias
v2: diameter 0.61, hole 0.2, Top Layer to Bottom Layer, tented both sides, 54 vias
v3: diameter 0.508, hole 0.203, Top Layer to Bottom Layer, tented both sides, 46 vias
v4: diameter 0.5, hole 0.2, Top Layer to Bottom Layer, 16 vias
v5: diameter 0.864, hole 0.406, Top Layer to Bottom Layer, tented both sides, 15 vias
v6: diameter 0.711, hole 0.356, Top Layer to Bottom Layer, tented both sides, 10 vias
v7: diameter 5, hole 4.3, Top Layer to Bottom Layer, 3 vias
v8: diameter 0.61, hole 0.203, Top Layer to Bottom Layer, tented both sides, 3 vias
v9: diameter 5, hole 4.5, Top Layer to Bottom Layer, 1 vias

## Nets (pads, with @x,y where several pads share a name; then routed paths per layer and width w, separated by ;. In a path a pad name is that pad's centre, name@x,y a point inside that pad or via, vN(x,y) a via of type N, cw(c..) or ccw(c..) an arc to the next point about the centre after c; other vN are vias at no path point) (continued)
GND: C1.2 C2.2 C3.2 C4.2 C5.2 C6.2 C7.2 C8.2 C9.2 C10.2 C11.2 C12.2 C13.2 C14.2 C15.2 C16.2 C17.2 C18.2 C19.2 C20.2 C21.2 C22.2 C23.2 C24.2 C25.1 C26.1 C28.1 C29.1 C33.2 C34.2 C35.2 C36.2 C37.2 C38.2 C39.1 C43.1 C44.2 C45.1 C49.1 C50.1 C51.1 C52.1 C53.1 C54.1 C55.1 C56.1 C57.1 C58.1 C59.1 C60.1 C61.1 C64.1 C65.1 C66.1 C68.2 C69.2 C70.2 C71.1 C72.1 C73.1 C74.2 C75.2 C76.2 C77.2 C78.2 C79.2 C80.2 C81.2 C82.1 C83.2 C84.1 C85.2 C87.1 C88.1 C89.1 C90.1 C91.1 C92.1 D9.2 IC1.3 IC2.4 IC2.9 IC3.1 J4.8 J5.2 J9.2 J16.2 J17.5 J17.6 J19.1 J19.2 J21.3 J21.6 J22.1 J22.2 J22.5 J22.6 LED1.2 LED2.2 R2.2 R3.1 R6.1 R15.1 R23.1 R27.1 R28.1 R29.1 R30.1 R33.1 R44.1 R57.1 R62.1 R63.1 R72.1 R77.1 S1.3 S1.4 SH1.1 SH1.2 SH2.1 SH2.2 SH3.1 SH3.2 TP1.1 TP25.1 TP26.1 U1.41 U2.8 U2.23 U2.39 U2.41 U3.30 U3.33 U4.3 XDS1.10 XDS1.17 XDS1.48 XDS1.55 XDS1.58 XDS1.64 XDS1.66 XDS1.80 XDS1.114 Y1.2 Y1.4 Y2.2 Y2.4 | length 77.4
  Top Layer w0.152: v2(2.634,43.577) 2.634,44.538 R29.1@2.677,44.582 ; R30.1@2.715,37.689 2.715,37.069 v2(3.25,36.534) ; C76.2@15.058,61.893 15.1,61.935 v2(15.1,63.066) ; C77.2@21.426,60.919 21.426,60.374 v2(21.59,60.21) 21.714,60.21 21.871,60.368 22.858,60.368 C75.2@23.108,60.618 ; v2(22.907,44.05) 22.907,44.004 23.162,43.749 U1.41@23.162,42.814 23.236,42.74 23.236,41.977 23.795,41.417 C24.2@23.795,40.714 ; U4.3@23.406,83.862 v1(23.406,84.496) ; C83.2@28.393,70.842 C83.2@28.681,71.131 C83.2@28.681,71.281 ; C78.2@31.304,73.086 31.778,73.559 C78.2@31.778,73.809 ; v2(43.979,28.086) R23.1@43.979,29.286 ; C45.1@93.387,55.361 93.501,55.476 v1(93.501,55.974) ; C45.1@93.437,55.361 C45.1@93.725,55.073
  Top Layer w0.203: R6.1@7.555,13.603 7.356,13.802 R6.1@7.356,13.848 R6.1@7.356,13.886 ; R6.1@7.645,14.146 7.555,14.146 7.356,13.948 R6.1@7.356,13.886 ; v3@8.027,14.529 8.182,14.683 C1.2@8.182,15.488 ; v3(8.089,14.467) 7.706,14.084 7.555,14.084 R6.1@7.356,13.886 ; v4(9.253,27.321) 9.753,27.321 9.902,27.469 9.902,27.524 10.048,27.671 IC2.4@10.653,27.671 ; v6(10.564,13.908) 10.572,13.908 10.924,13.556 11.093,13.556 11.579,14.042 C19.2@11.679,14.042 11.679,14.592 ; v6(11.242,22.062) 11.334,22.062 11.624,21.772 C5.2@12.329,21.772 ; Y1.4@11.395,16.19 11.395,15.801 11.753,15.443 11.753,14.592 ; C12.2@12.273,28.03 12.335,27.968 v3(12.335,27.243) ; C22.2@12.329,24.78 12.429,24.78 12.886,25.237 12.886,25.432 v3(12.944,25.491) v3@12.886,25.549 ; Y1.2@12.907,18.089 12.907,19.442 C18.2@12.953,19.488 12.974,19.509 14.203,19.509 v6(14.225,19.53) 14.322,19.627 14.322,19.832 14.77,20.28 XDS1.80@15.607,20.28 ; 14.163,25.872 14.172,25.88 XDS1.66@15.607,25.88 ; v3(14.225,8.949) 14.866,8.949 C11.2@14.88,8.935 ; XDS1.64@17.107,27.78 XDS1.64@17.107,27.978 ; XDS1.64@17.107,28.379 R15.1@17.107,29.323 ; C7.2@19.742,29.482 19.717,29.482 19.519,29.283 19.519,27.169 19.521,27.167 19.521,26.966 19.879,26.607 20.112,26.607 v3(20.17,26.549) 20.171,26.55 20.481,26.55 20.719,26.788 20.719,27.172 XDS1.55@20.709,27.182 ; v3(23.236,26.652) 23.236,26.707 23.507,26.978 XDS1.48@23.507,27.78 ; C6.2@25.157,29.336 25.261,29.232 25.865,29.232 v3(25.924,29.174) ; v6@29.48,17.489 XDS1.10@31.018,17.489 ; v6@29.51,20.715 29.945,20.28 XDS1.17@31.007,20.28 ; C20.2@34.756,20.651 C21.2@34.756,22.174 34.844,22.262 v3(34.844,24.479) 34.449,24.874 33.99,24.874 IC3.1@33.892,24.972 33.892,25.508 34.458,26.074 34.458,26.511 34.656,26.709 C14.2@34.756,26.709 34.844,26.709 35.042,26.511 v6(35.042,25.414) ; R3.1@34.844,11.976 34.89,11.931 v3(34.89,11.292) ; C8.2@34.844,15.022 34.991,15.17 v3(34.991,15.813) 34.991,16.398 C13.2@34.844,16.545
  Top Layer w0.254: v6(7.737,21.757) 7.737,21.72 8.164,21.293 IC1.3@8.164,20.758 ; v3(8.089,14.467) 8.118,14.438 8.118,14.212 8.626,13.703 C2.2@8.626,13.603 ; v3(12.944,25.491) 13.8,25.491 14.172,25.863 ; v6(16.5,28.386) 16.909,27.978 XDS1.64@17.08,27.978 ; XDS1.114@23.907,12.38 23.907,13.461 24.247,13.801 v3(24.247,13.807) ; v6(29.429,20.715) v6@29.51,20.715 ; v2(40.553,83.492) 40.553,82.273 R63.1@40.566,82.261 ; R62.1@44.368,82.311 v2(44.368,83.542)
  Top Layer w0.305: LED1.2@8.753,9.349 8.81,9.406 9.738,9.406 v6(9.795,9.463) 9.838,9.506 10.742,9.506 LED2.2@10.785,9.549
  Top Layer w0.508: R2.2@6.117,27.496 6.117,29.189 5.858,29.449 v6(5.858,29.504) 5.869,29.493 7.278,29.493 C3.2@7.29,29.482 ; C9.2@19.637,8.949 v8(20.49,8.949) C10.2@21.387,8.949 21.387,8.895 21.433,8.849 22.819,8.849 C15.2@22.919,8.749 ; C15.2@22.919,8.949 C16.2@24.452,8.949 v8(25.168,8.949) C17.2@25.985,8.949 v8(26.749,8.949) C4.2@27.519,8.949
  Bottom Layer w0.254: v3(19.269,14.162) 19.736,14.629 19.736,15.01 TP1.1@19.878,15.153
  other v1: 7.483,1.676 35.423,1.676 37.963,1.676 40.503,1.676 43.043,1.676 45.583,1.676 48.123,1.676 50.663,1.676 53.203,1.676 55.743,1.676 58.283,1.676 60.823,1.676 63.363,1.676 65.903,1.676 68.443,1.676 70.983,1.676 73.523,1.676 76.063,1.676 78.603,1.676 81.143,1.676 83.683,1.676 86.223,1.676 88.763,1.676 91.303,1.676 93.843,1.676 96.383,1.676 98.923,1.676 101.463,1.676 104.003,1.676 106.543,1.676 109.083,1.676 111.623,1.676 114.163,1.676 116.703,1.676 119.243,1.676 121.783,1.676 124.323,1.676 126.863,1.676 129.403,1.676 131.943,1.676 134.483,1.676 137.023,1.676 139.563,1.676 142.103,1.676 144.643,1.676 36.693,4.216 39.233,4.216 41.773,4.216 44.313,4.216 46.853,4.216 49.393,4.216 51.933,4.216 54.473,4.216 57.013,4.216 59.553,4.216 62.093,4.216 64.633,4.216 67.173,4.216 69.713,4.216 72.253,4.216 74.793,4.216 77.333,4.216 79.873,4.216 82.413,4.216 84.953,4.216 87.493,4.216 90.033,4.216 92.573,4.216 95.113,4.216 97.653,4.216 100.193,4.216 102.733,4.216 105.273,4.216 107.813,4.216 110.353,4.216 112.893,4.216 115.433,4.216 117.973,4.216 120.513,4.216 123.053,4.216 125.593,4.216 128.133,4.216 130.673,4.216 133.213,4.216 135.753,4.216 138.293,4.216 140.833,4.216 143.373,4.216 145.913,4.216 2.403,6.756 4.943,6.756 7.483,6.756 35.423,6.756 37.963,6.756 40.503,6.756 43.043,6.756 45.583,6.756 48.123,6.756 50.663,6.756 53.203,6.756 55.743,6.756 58.283,6.756 60.823,6.756 63.363,6.756 65.903,6.756 81.143,6.756 83.683,6.756 86.223,6.756 88.763,6.756 104.003,6.756 106.543,6.756 109.083,6.756 111.623,6.756 114.163,6.756 116.703,6.756 119.243,6.756 121.783,6.756 124.323,6.756 126.863,6.756 129.403,6.756 131.943,6.756 134.483,6.756 137.023,6.756 139.563,6.756 142.103,6.756 144.643,6.756 147.183,6.756 149.723,6.756 3.673,9.296 6.213,9.296 41.773,9.296 46.853,9.296 49.393,9.296 51.933,9.296 54.473,9.296 57.013,9.296 59.553,9.296 62.093,9.296 64.633,9.296 79.873,9.296 84.953,9.296 87.493,9.296 107.813,9.296 110.353,9.296 112.893,9.296 115.433,9.296 117.973,9.296 120.513,9.296 123.053,9.296 125.593,9.296 128.133,9.296 130.673,9.296 133.213,9.296 135.753,9.296 138.293,9.296 140.833,9.296 143.373,9.296 145.913,9.296 148.453,9.296 150.993,9.296 2.403,11.836 4.943,11.836 7.483,11.836 40.503,11.836 45.583,11.836 48.123,11.836 50.663,11.836 53.203,11.836 55.743,11.836 58.283,11.836 60.823,11.836 63.363,11.836 65.903,11.836 68.443,11.836 70.983,11.836 73.523,11.836 81.143,11.836 83.683,11.836 86.223,11.836 88.763,11.836 91.303,11.836 93.843,11.836 96.383,11.836 104.003,11.836 106.543,11.836 109.083,11.836 111.623,11.836 114.163,11.836 116.703,11.836 119.243,11.836 121.783,11.836 124.323,11.836 126.863,11.836 129.403,11.836 131.943,11.836 134.483,11.836 137.023,11.836 139.563,11.836 142.103,11.836 144.643,11.836 147.183,11.836 149.723,11.836 3.673,14.376 13.833,14.376 41.773,14.376 46.853,14.376 49.393,14.376 51.933,14.376 54.473,14.376 57.013,14.376 59.553,14.376 62.093,14.376 64.633,14.376 67.173,14.376 69.713,14.376 72.253,14.376 79.873,14.376 82.413,14.376 84.953,14.376 87.493,14.376 90.033,14.376 92.573,14.376 95.113,14.376 105.273,14.376 107.813,14.376 110.353,14.376 112.893,14.376 115.433,14.376 117.973,14.376 120.513,14.376 123.053,14.376 125.593,14.376 128.133,14.376 130.673,14.376 133.213,14.376 135.753,14.376 138.293,14.376 140.833,14.376 143.373,14.376 145.913,14.376 148.453,14.376 150.993,14.376 40.503,16.916 48.123,16.916 50.663,16.916 53.203,16.916 55.743,16.916 58.283,16.916 60.823,16.916 63.363,16.916 65.903,16.916 68.443,16.916 70.983,16.916 73.523,16.916 81.143,16.916 83.683,16.916 86.223,16.916 88.763,16.916 91.303,16.916 93.843,16.916 96.383,16.916 104.003,16.916 106.543,16.916 109.083,16.916 111.623,16.916 114.163,16.916 116.703,16.916 119.243,16.916 121.783,16.916 126.863,16.916 129.403,16.916 131.943,16.916 134.483,16.916 137.023,16.916 139.563,16.916 142.103,16.916 144.643,16.916 147.183,16.916 149.723,16.916 41.773,19.456 49.393,19.456 51.933,19.456 54.473,19.456 57.013,19.456 59.553,19.456 62.093,19.456 64.633,19.456 67.173,19.456 69.713,19.456 72.253,19.456 79.873,19.456 82.413,19.456 84.953,19.456 87.493,19.456 90.033,19.456 92.573,19.456 95.113,19.456 97.653,19.456 105.273,19.456 107.813,19.456 110.353,19.456 112.893,19.456 115.433,19.456 117.973,19.456 120.513,19.456 123.053,19.456 125.593,19.456 45.583,21.996 48.123,21.996 50.663,21.996 53.203,21.996 55.743,21.996 58.283,21.996 60.823,21.996 63.363,21.996 65.903,21.996 68.443,21.996 70.983,21.996 73.523,21.996 81.143,21.996 83.683,21.996 86.223,21.996 88.763,21.996 91.303,21.996 93.843,21.996 96.383,21.996 104.003,21.996 106.543,21.996 109.083,21.996 111.623,21.996 3.673,24.536 39.233,24.536 41.773,24.536 49.393,24.536 51.933,24.536 54.473,24.536 57.013,24.536 59.553,24.536 62.093,24.536 64.633,24.536 67.173,24.536 69.713,24.536 72.253,24.536 82.413,24.536 84.953,24.536 87.493,24.536 90.033,24.536 92.573,24.536 95.113,24.536 97.653,24.536 105.273,24.536 107.813,24.536 110.353,24.536 2.403,27.076 4.943,27.076 50.663,27.076 53.203,27.076 55.743,27.076 58.283,27.076 60.823,27.076 63.363,27.076 65.903,27.076 68.443,27.076 70.983,27.076 73.523,27.076 83.683,27.076 86.223,27.076 88.763,27.076 91.303,27.076 93.843,27.076 96.383,27.076 109.083,27.076 111.623,27.076 3.673,29.616 39.233,29.616 49.393,29.616 51.933,29.616 54.473,29.616 57.013,29.616 59.553,29.616 62.093,29.616 64.633,29.616 67.173,29.616 69.713,29.616 72.253,29.616 74.793,29.616 77.333,29.616 2.403,32.156 4.943,32.156 7.483,32.156 37.963,32.156 40.503,32.156 50.663,32.156 53.203,32.156 55.743,32.156 58.283,32.156 60.823,32.156 63.363,32.156 65.903,32.156 68.443,32.156 70.983,32.156 73.523,32.156 76.063,32.156 78.603,32.156 34.605,33.739 43.043,34.321 37.677,34.696 49.393,34.696 51.933,34.696 54.473,34.696 57.013,34.696 59.553,34.696 62.093,34.696 64.633,34.696 67.173,34.696 69.713,34.696 72.253,34.696 74.793,34.696 77.333,34.696 79.873,34.696 82.413,34.696 84.953,34.696 100.193,34.696 102.733,34.696 105.273,34.696 107.813,34.696 130.673,34.696 133.213,34.696 135.753,34.696 138.293,34.696 140.833,34.696 143.373,34.696 145.913,34.696 148.453,34.696 150.993,34.696 30.725,34.881 24.763,35.56 25.662,36.96 15.103,37.236 17.643,37.236 35.423,37.236 37.963,37.236 43.043,37.236 50.663,37.236 65.903,37.236 68.443,37.236 70.983,37.236 73.523,37.236 76.063,37.236 78.603,37.236 81.143,37.236 83.683,37.236 86.223,37.236 88.763,37.236 91.303,37.236 101.463,37.236 106.543,37.236 134.483,37.236 137.023,37.236 139.563,37.236 142.103,37.236 144.643,37.236 147.183,37.236 149.723,37.236 43.425,39.448 23.993,39.776 49.393,39.776 51.933,39.776 72.253,39.776 74.793,39.776 77.333,39.776 79.873,39.776 82.413,39.776 84.953,39.776 87.493,39.776 90.033,39.776 102.733,39.776 105.273,39.776 107.813,39.776 138.293,39.776 140.833,39.776 143.373,39.776 148.453,39.776 150.993,39.776 34.385,40.804 37.013,41.152 31.248,41.35 29.195,41.567 41.773,41.656 32.913,41.79 15.103,42.316 40.503,42.316 43.043,42.316 53.203,42.316 55.743,42.316 58.283,42.316 60.823,42.316 63.363,42.316 65.903,42.316 70.983,42.316 76.063,42.316 78.603,42.316 81.143,42.316 83.683,42.316 86.223,42.316 88.763,42.316 101.463,42.316 104.003,42.316 106.543,42.316 134.483,42.316 137.023,42.316 139.563,42.316 142.103,42.316 144.643,42.316 147.183,42.316 149.723,42.316 34.153,44.856 36.693,44.856 39.233,44.856 44.313,44.856 51.933,44.856 59.553,44.856 62.093,44.856 64.633,44.856 67.173,44.856 69.713,44.856 72.253,44.856 74.793,44.856 77.333,44.856 79.873,44.856 82.413,44.856 84.953,44.856 87.493,44.856 97.653,44.856 133.213,44.856 135.753,44.856 138.293,44.856 140.833,44.856 143.373,44.856 145.913,44.856 148.453,44.856 150.993,44.856 93.997,46.84 95.367,46.84 15.103,47.396 22.723,47.396 43.043,47.396 45.583,47.396 48.123,47.396 53.203,47.396 58.283,47.396 60.823,47.396 63.363,47.396 65.903,47.396 68.443,47.396 70.983,47.396 73.523,47.396 76.063,47.396 78.603,47.396 81.143,47.396 83.683,47.396 88.763,47.396 119.243,47.396 121.783,47.396 124.323,47.396 126.863,47.396 129.403,47.396 131.943,47.396 137.023,47.396 139.563,47.396 142.103,47.396 144.643,47.396 147.183,47.396 149.723,47.396 92.857,47.98 93.997,47.98 95.367,47.98 96.507,47.98 80.159,48.039 81.296,48.573 92.857,49.35 93.997,49.35 95.367,49.35 96.507,49.35 80.478,49.402 78.451,49.698 26.533,49.936 36.693,49.936 39.233,49.936 41.773,49.936 44.313,49.936 51.933,49.936 59.553,49.936 62.093,49.936 64.633,49.936 67.173,49.936 69.713,49.936 72.253,49.936 79.873,49.936 82.413,49.936 117.973,49.936 120.513,49.936 125.593,49.936 128.133,49.936 130.673,49.936 133.213,49.936 135.753,49.936 138.293,49.936 140.833,49.936 143.373,49.936 145.913,49.936 148.453,49.936 93.997,50.49 95.367,50.49 79.266,50.677 8.218,50.8 78.095,51.827 5.573,52.002 76.173,52.044 22.723,52.476 25.263,52.476 40.503,52.476 43.043,52.476 45.583,52.476 48.123,52.476 50.663,52.476 53.203,52.476 58.283,52.476 63.363,52.476 65.903,52.476 73.523,52.476 116.703,52.476 119.243,52.476 124.323,52.476 126.863,52.476 129.403,52.476 131.943,52.476 134.483,52.476 137.023,52.476 139.563,52.476 142.103,52.476 144.643,52.476 147.183,52.476 149.723,52.476 8.218,52.628 77.028,52.944 74.51,53.655 6.187,53.796 75.606,54.275 16.771,54.898 39.233,55.016 41.773,55.016 44.313,55.016 51.933,55.016 62.093,55.016 64.633,55.016 74.793,55.016 77.333,55.016 79.873,55.016 82.413,55.016 117.973,55.016 120.513,55.016 123.053,55.016 125.593,55.016 128.133,55.016 150.993,55.016 73.048,55.145 4.567,55.356 8.326,55.551 73.81,56.033 71.66,56.629 30.343,57.556 40.503,57.556 43.043,57.556 45.583,57.556 48.123,57.556 50.663,57.556 53.203,57.556 63.363,57.556 65.903,57.556 68.443,57.556 121.783,57.556 124.323,57.556 126.863,57.556 129.403,57.556 131.943,57.556 137.023,57.556 139.563,57.556 142.103,57.556 144.643,57.556 147.183,57.556 149.723,57.556 25.984,58.162 22.443,58.339 71.543,58.353 91.99,58.353 24.495,58.395 44.313,60.096 51.933,60.096 57.013,60.096 59.553,60.096 72.253,60.096 74.793,60.096 77.333,60.096 84.953,60.096 92.573,60.096 150.993,60.096 91.888,61.543 27.803,62.636 43.043,62.636 45.583,62.636 48.123,62.636 50.663,62.636 53.203,62.636 60.823,62.636 63.363,62.636 65.903,62.636 68.443,62.636 83.683,62.636 86.223,62.636 93.843,62.636 101.463,62.636 104.003,62.636 106.543,62.636 124.323,62.636 126.863,62.636 129.403,62.636 131.943,62.636 137.023,62.636 139.563,62.636 142.103,62.636 144.643,62.636 147.183,62.636 149.723,62.636 15.542,63.714 17.48,63.772 91.938,64.26 3.673,65.176 6.213,65.176 44.313,65.176 46.853,65.176 49.393,65.176 51.933,65.176 54.473,65.176 72.253,65.176 79.873,65.176 82.413,65.176 84.953,65.176 95.113,65.176 102.733,65.176 105.273,65.176 107.813,65.176 110.353,65.176 150.993,65.176 4.943,67.716 10.023,67.716 12.563,67.716 17.643,67.716 37.963,67.716 40.503,67.716 43.043,67.716 45.583,67.716 48.123,67.716 50.663,67.716 53.203,67.716 55.743,67.716 58.283,67.716 60.823,67.716 63.363,67.716 65.903,67.716 68.443,67.716 78.603,67.716 81.143,67.716 83.683,67.716 86.223,67.716 93.843,67.716 96.383,67.716 101.463,67.716 104.003,67.716 106.543,67.716 109.083,67.716 111.623,67.716 129.403,67.716 131.943,67.716 134.483,67.716 149.723,67.716 3.673,70.256 6.213,70.256 31.613,70.256 34.153,70.256 41.773,70.256 44.313,70.256 49.393,70.256 51.933,70.256 54.473,70.256 57.013,70.256 59.553,70.256 62.093,70.256 64.633,70.256 67.173,70.256 74.793,70.256 77.333,70.256 79.873,70.256 82.413,70.256 84.953,70.256 92.573,70.256 95.113,70.256 102.733,70.256 105.273,70.256 107.813,70.256 110.353,70.256 112.893,70.256 115.433,70.256 130.673,70.256 133.213,70.256 135.753,70.256 150.993,70.256 4.943,72.796 7.483,72.796 12.563,72.796 15.103,72.796 20.183,72.796 25.263,72.796 30.343,72.796 32.883,72.796 35.423,72.796 37.963,72.796 40.503,72.796 43.043,72.796 45.583,72.796 48.123,72.796 50.663,72.796 53.203,72.796 55.743,72.796 58.283,72.796 60.823,72.796 63.363,72.796 73.523,72.796 76.063,72.796 78.603,72.796 81.143,72.796 83.683,72.796 86.223,72.796 93.843,72.796 96.383,72.796 101.463,72.796 104.003,72.796 106.543,72.796 109.083,72.796 111.623,72.796 114.163,72.796 116.703,72.796 149.723,72.796 3.673,75.336 6.213,75.336 11.293,75.336 13.833,75.336 16.373,75.336 18.913,75.336 26.533,75.336 29.073,75.336 41.773,75.336 46.853,75.336 49.393,75.336 51.933,75.336 54.473,75.336 57.013,75.336 59.553,75.336 62.093,75.336 67.173,75.336 72.253,75.336 74.793,75.336 77.333,75.336 79.873,75.336 82.413,75.336 84.953,75.336 92.573,75.336 95.113,75.336 102.733,75.336 105.273,75.336 107.813,75.336 110.353,75.336 112.893,75.336 115.433,75.336 117.973,75.336 123.053,75.336 130.673,75.336 135.753,75.336 138.293,75.336 140.833,75.336 143.373,75.336 145.913,75.336 148.453,75.336 150.993,75.336 4.943,77.876 7.483,77.876 10.023,77.876 15.103,77.876 20.183,77.876 27.803,77.876 30.343,77.876 32.883,77.876 35.423,77.876 37.963,77.876 43.043,77.876 45.583,77.876 48.123,77.876 50.663,77.876 53.203,77.876 55.743,77.876 58.283,77.876 60.823,77.876 65.903,77.876 73.523,77.876 76.063,77.876 78.603,77.876 81.143,77.876 83.683,77.876 86.223,77.876 93.843,77.876 96.383,77.876 101.463,77.876 104.003,77.876 106.543,77.876 109.083,77.876 111.623,77.876 114.163,77.876 116.703,77.876 131.943,77.876 134.483,77.876 137.023,77.876 139.563,77.876 142.103,77.876 144.643,77.876 147.183,77.876 149.723,77.876 22.32,78.101 24.519,78.101 3.673,80.416 6.213,80.416 11.293,80.416 13.833,80.416 16.373,80.416 18.913,80.416 26.533,80.416 29.073,80.416 31.613,80.416 34.153,80.416 36.693,80.416 39.233,80.416 41.773,80.416 46.853,80.416 49.393,80.416 51.933,80.416 54.473,80.416 57.013,80.416 59.553,80.416 67.173,80.416 72.253,80.416 74.793,80.416 77.333,80.416 79.873,80.416 82.413,80.416 84.953,80.416 92.573,80.416 95.113,80.416 102.733,80.416 105.273,80.416 107.813,80.416 110.353,80.416 112.893,80.416 115.433,80.416 117.973,80.416 123.053,80.416 150.993,80.416 2.403,82.956 4.943,82.956 7.483,82.956 10.023,82.956 12.563,82.956 20.183,82.956 25.263,82.956 27.803,82.956 30.343,82.956 32.883,82.956 35.423,82.956 37.963,82.956 43.043,82.956 45.583,82.956 48.123,82.956 50.663,82.956 53.203,82.956 55.743,82.956 58.283,82.956 60.823,82.956 65.903,82.956 73.523,82.956 76.063,82.956 78.603,82.956 81.143,82.956 83.683,82.956 86.223,82.956 93.843,82.956 96.383,82.956 101.463,82.956 104.003,82.956 106.543,82.956 109.083,82.956 111.623,82.956 114.163,82.956 116.703,82.956 131.943,82.956 137.023,82.956 139.563,82.956 142.103,82.956 144.643,82.956 147.183,82.956 149.723,82.956 17.109,85.273 3.673,85.496 6.213,85.496 8.753,85.496 11.293,85.496 16.373,85.496 21.453,85.496 26.533,85.496 29.073,85.496 31.613,85.496 34.153,85.496 36.693,85.496 39.233,85.496 41.773,85.496 44.313,85.496 46.853,85.496 49.393,85.496 51.933,85.496 54.473,85.496 57.013,85.496 59.553,85.496 67.173,85.496 74.793,85.496 77.333,85.496 79.873,85.496 82.413,85.496 84.953,85.496 92.573,85.496 95.113,85.496 102.733,85.496 105.273,85.496 107.813,85.496 110.353,85.496 112.893,85.496 115.433,85.496 117.973,85.496 123.053,85.496 128.133,85.496 150.993,85.496 2.403,88.036 4.943,88.036 7.483,88.036 10.023,88.036 12.563,88.036 15.103,88.036 17.643,88.036 20.183,88.036 25.263,88.036 27.803,88.036 30.343,88.036 32.883,88.036 35.423,88.036 37.963,88.036 40.503,88.036 43.043,88.036 45.583,88.036 48.123,88.036 50.663,88.036 53.203,88.036 55.743,88.036 58.283,88.036 60.823,88.036 65.903,88.036 73.523,88.036 76.063,88.036 78.603,88.036 81.143,88.036 83.683,88.036 86.223,88.036 93.843,88.036 96.383,88.036 101.463,88.036 104.003,88.036 106.543,88.036 109.083,88.036 111.623,88.036 114.163,88.036 116.703,88.036 129.403,88.036 131.943,88.036 137.023,88.036 139.563,88.036 142.103,88.036 144.643,88.036 147.183,88.036 149.723,88.036 3.673,90.576 6.213,90.576 8.753,90.576 11.293,90.576 13.833,90.576 31.613,90.576 34.153,90.576 36.693,90.576 39.233,90.576 41.773,90.576 44.313,90.576 46.853,90.576 49.393,90.576 51.933,90.576 54.473,90.576 57.013,90.576 59.553,90.576 67.173,90.576 72.253,90.576 74.793,90.576 77.333,90.576 79.873,90.576 82.413,90.576 84.953,90.576 92.573,90.576 95.113,90.576 102.733,90.576 105.273,90.576 107.813,90.576 110.353,90.576 112.893,90.576 115.433,90.576 117.973,90.576 123.053,90.576 128.133,90.576 130.673,90.576 133.213,90.576 135.753,90.576 138.293,90.576 140.833,90.576 143.373,90.576 145.913,90.576 148.453,90.576 150.993,90.576 2.403,93.116 4.943,93.116 10.023,93.116 12.563,93.116 15.103,93.116 17.643,93.116 20.183,93.116 27.803,93.116 30.343,93.116 32.883,93.116 35.423,93.116 37.963,93.116 40.503,93.116 43.043,93.116 45.583,93.116 48.123,93.116 50.663,93.116 53.203,93.116 55.743,93.116 65.903,93.116 78.603,93.116 81.143,93.116 93.843,93.116 106.543,93.116 109.083,93.116 134.483,93.116 137.023,93.116 139.563,93.116 142.103,93.116 144.643,93.116 147.183,93.116 149.723,93.116 25.392,93.529 23.704,95.301 6.213,95.656 41.773,95.656 44.313,95.656 46.853,95.656 49.393,95.656 51.933,95.656 54.473,95.656 57.013,95.656 59.553,95.656 62.093,95.656 64.633,95.656 67.173,95.656 69.713,95.656 72.253,95.656 74.793,95.656 77.333,95.656 79.873,95.656 82.413,95.656 84.953,95.656 87.493,95.656 90.033,95.656 92.573,95.656 95.113,95.656 100.193,95.656 102.733,95.656 105.273,95.656 107.813,95.656 117.973,95.656 120.513,95.656 123.053,95.656 125.593,95.656 128.133,95.656 130.673,95.656 133.213,95.656 135.753,95.656 138.293,95.656 140.833,95.656 143.373,95.656 145.913,95.656 22.906,96.45 23.724,96.45 43.043,98.196 45.583,98.196 48.123,98.196 50.663,98.196 53.203,98.196 55.743,98.196 58.283,98.196 60.823,98.196 63.363,98.196 65.903,98.196 68.443,98.196 70.983,98.196 73.523,98.196 76.063,98.196 78.603,98.196 81.143,98.196 83.683,98.196 86.223,98.196 88.763,98.196 91.303,98.196 93.843,98.196 96.383,98.196 98.923,98.196 101.463,98.196 104.003,98.196 106.543,98.196 109.083,98.196 111.623,98.196 114.163,98.196 116.703,98.196 119.243,98.196 121.783,98.196 124.323,98.196 126.863,98.196 129.403,98.196 131.943,98.196 134.483,98.196 137.023,98.196 139.563,98.196 142.103,98.196 144.643,98.196
  other v4: 9.253,26.071 8.753,26.696 9.753,26.696 22.69,64.403 23.95,64.403 21.72,65.373 22.69,65.373 23.95,65.373 24.92,65.373 21.72,66.633 22.69,66.633 23.95,66.633 24.92,66.633 22.69,67.603 23.95,67.603
  other v6: 29.48,17.49
  other v7: 149,3.5 3.5,97.5 149,97.5
  other v9: 3.5,3.5
GUI_STATUS: D3.2 U1.30 | length 12.2
  Top Layer w0.152: D3.2@8.345,37.724 16.312,45.69 17.138,45.69 U1.30@17.212,45.764
HFXIN: C29.2 U1.45 Y2.3 | length 6.3
  Top Layer w0.152: U1.45@25.162,42.814 25.162,39.078 C29.2@25.793,38.448 26.222,38.018 Y2.3@27.272,38.018
HFXOUT: C28.2 U1.46 Y2.1 | length 5.6
  Top Layer w0.152: U1.46@25.662,42.814 25.736,42.74 25.736,41.979 26.171,41.543 26.461,41.543 27.164,40.841 28.124,40.841 29.347,39.618 Y2.1@29.472,39.618
HSS1: J17.1 U3.7 | length 19
  Top Layer w0.254: J17.1@2.715,66.706 5.927,66.706 7.88,64.753 U3.7@20.92,64.753
HSS2: J17.2 U3.6 | length 19.9
  Top Layer w0.254: J17.2@2.715,69.246 6.351,69.246 10.344,65.253 U3.6@20.92,65.253
HSS3: J17.3 U3.5 | length 20.7
  Top Layer w0.254: J17.3@2.715,71.786 6.698,71.786 12.736,65.748 20.307,65.748 20.311,65.753 U3.5@20.92,65.753
HSS4: J17.4 U3.4 | length 21.6
  Top Layer w0.254: J17.4@2.715,74.326 6.812,74.326 14.936,66.202 20.119,66.202 20.169,66.253 U3.4@20.92,66.253
IN2: J2.2 TP10.1 U2.11 | length 50.2
  Top Layer w0.152: TP10.1@55.012,63.4 56.992,65.38 70.398,65.38 84.426,51.351 85.522,51.351 86.337,50.537 91.061,50.537 91.293,50.768 91.461,50.768 91.607,50.915 U2.11@91.782,50.915
  Bottom Layer w0.152: J2.2@49.378,61.617 53.121,61.617 TP10.1@54.958,63.454
IPROPI: C68.1 J2.14 J3.1 R57.2 TP16.1 U2.17 | length 105.4
  Top Layer w0.152: J2.14@49.378,46.377 50.818,46.377 54.14,49.698 57.658,49.698 61.809,53.849 TP16.1@69.811,53.849 70.446,53.849 77.686,46.609 C68.1@84.771,46.609 84.836,46.544 89.986,46.544 91.308,47.866 91.734,47.866 U2.17@91.782,47.915
  Bottom Layer w0.152: J3.1@3.25,48.545 4.462,47.334 9.373,42.423 13.845,42.423 18.292,37.976 45.007,37.976 47.891,40.86 47.891,44.89 J2.14@49.378,46.377
IRSTN: R16.1 TP6.1 | length 27.8
  Top Layer w0.203: v3(15.459,28.539) 15.459,29.148 R16.1@15.662,29.351
  Bottom Layer w0.203: v3(15.459,28.539) 15.459,25.763 18.322,22.9 30.47,22.9 30.843,22.527 TP6.1@30.843,15.153
ITCK: R8.2 TP3.1 XDS1.100 | length 10
  Top Layer w0.203: R8.2@18.011,10.149 18.011,10.804 18.271,11.063 v3(18.329,11.063) 18.307,11.085 XDS1.100@18.307,12.38
  Bottom Layer w0.203: v3(18.329,11.063) 19.048,11.063 23.138,15.153 TP3.1@24.264,15.153 TP3.1@24.273,15.153
ITDI: TP5.1 XDS1.98 | length 14.4
  Top Layer w0.203: XDS1.98@17.507,12.38 17.507,13.081 18.177,13.75 v3(18.177,13.756)
  Bottom Layer w0.203: v3(18.177,13.756) 18.215,13.795 18.215,14.332 18.891,15.007 18.891,15.231 19.566,15.907 21.501,15.907 24.576,15.907 26.084,14.399 26.769,14.399 27.523,15.153 TP5.1@28.65,15.153
ITDO: TP4.1 XDS1.97 | length 12
  Top Layer w0.203: XDS1.97@17.107,12.979 17.107,13.476 17.491,13.859 v3(17.491,13.883)
  Bottom Layer w0.203: v3(17.491,13.883) 17.491,13.935 17.86,14.304 17.86,14.479 18.535,15.154 18.535,15.379 19.579,16.423 25.339,16.423 26.482,15.28 TP4.1@26.482,15.102
ITMS: R7.2 TP2.1 XDS1.99 | length 8.7
  Top Layer w0.203: R7.2@16.567,10.135 16.567,10.84 16.935,11.208 17.575,11.208 v3(17.618,11.165) 17.676,11.223 17.676,11.434 17.906,11.663 XDS1.99@17.906,11.782
  Bottom Layer w0.203: v3(17.618,11.165) 21.473,15.02 21.93,15.02 TP2.1@22.024,15.114
LIN_PU: D8.1 R65.1 | length 2.2
  Top Layer w0.254: D8.1@11.523,84.513 11.853,84.843 R65.1@13.553,84.843
LIN_PU_EN: J18.2 R65.2 | length 3.3
  Top Layer w0.254: J18.2@14.432,82.192 14.432,82.245 15.153,82.966 R65.2@15.153,85.103 ; R65.2@14.861,84.843 R65.2@14.925,84.779
MCU_CAN_GFO: U1.1 U3.25 | length 35.9
  Top Layer w0.152: U3.25@25.07,68.403 26.267,68.403 26.417,68.253 34.341,68.253 38.719,63.875 38.719,57.2 38.118,56.599 v2(37.994,56.599) ; U1.1@26.662,54.214 26.662,54.814 27.566,55.718 31.248,55.718 32.026,56.496 v2(32.026,56.585)
  Bottom Layer w0.152: v2(32.026,56.585) 32.04,56.599 v2(37.994,56.599)
MCU_CAN_LRXD: U1.57 U3.22 | length 34.2
  Top Layer w0.152: U3.22@25.72,66.753 33.741,66.753 36.841,63.653 36.841,61.161 37.013,60.988 37.013,52.712 v2(33.115,48.813) ; U1.57@28.612,48.764 28.637,48.789 31.251,48.789 v2(32.201,49.739)
  Bottom Layer w0.152: v2(32.201,49.739) 32.201,49.727 v2(33.115,48.813)
MCU_CAN_LTXD: U1.56 U3.21 | length 32.2
  Top Layer w0.152: U3.21@25.72,66.253 33.534,66.253 36.341,63.446 36.341,61.161 36.661,60.84 36.661,53.327 31.598,48.264 U1.56@28.612,48.264
MCU_CAN_nINT: U1.4 U3.15 | length 13.2
  Top Layer w0.152: U3.15@24.57,63.603 24.619,63.554 24.619,63.268 24.86,63.027 25.809,63.027 28.208,60.628 v2(28.208,59.636) ; U1.4@25.162,54.214 25.162,55.119 27.521,57.477 v2(28.285,57.477)
  Bottom Layer w0.152: v2(28.208,59.636) 28.246,59.598 28.246,57.516 v2(28.285,57.477)
MCU_CAN_nRST: U1.14 U3.14 | length 13
  Top Layer w0.152: U1.14@20.162,54.214 20.162,55.409 20.074,55.497 20.074,56.138 20.587,56.65 20.587,58.211 21.571,59.195 23.897,59.195 24.713,60.01 24.713,60.581 24.713,62.555 24.075,63.193 24.075,63.598 U3.14@24.07,63.603
MCU_CAN_SW: J20.2 U1.3 U3.16 | length 16.2
  Top Layer w0.152: U3.16@25.07,63.603 25.07,63.379 28.662,63.379 29.397,62.644 29.397,59.688 v2(29.345,59.636) ; U1.3@25.662,54.214 25.662,55.134 26.632,56.104 28.194,56.104 28.722,56.632 28.722,56.854 v2(29.345,57.477)
  Bottom Layer w0.152: v2@29.258,57.39 v2(29.345,57.477) 28.968,57.854 28.968,59.151 29.345,59.529 v2(29.345,59.636)
MCU_DRVOFF: U1.48
MCU_GD_IN1: U1.35
MCU_GD_IN2: J2.1 U1.54 | length 26.9
  Top Layer w0.152: U1.54@28.612,47.264 32.538,47.264 41.963,56.688 41.963,61.081 42.685,61.803 46.651,61.803 J2.1@46.838,61.617
MCU_IPROPI/PWM2: J2.13 U1.8 | length 39.4
  Top Layer w0.152: U1.8@23.162,54.214 23.155,54.221 23.155,55.193 23.422,55.46 23.565,55.46 v2(23.652,55.547)
  Bottom Layer w0.152: v2(23.652,55.547) 23.706,55.494 23.706,49.369 23.608,49.271 23.608,42.868 24.028,42.448 39.908,42.448 43.837,46.377 J2.13@46.838,46.377
MCU_nSCS_CAN: TP49.1 U1.29 U3.20 | length 53
  Top Layer w0.152: U1.29@17.212,46.264 18.26,46.264 20.12,48.124 21.766,48.124 27.041,53.398 27.041,53.424 28.62,55.003 31.355,55.003 33.345,56.993 v2@33.345,57.103 ; U3.20@25.72,65.753 33.327,65.753 35.841,63.239 35.841,61.161 35.892,61.11 35.892,58.937 36.04,58.789 v2(36.04,57.477)
  Bottom Layer w0.152: v2@33.345,57.103 v2(33.345,57.218) 33.929,57.802 35.611,57.802 35.936,57.477 v2(36.04,57.477) 38.878,57.477 39.732,58.332 39.732,63.452 40.185,63.904 TP49.1@40.185,66.253
MCU_nSCS_DRV: J2.5 U1.58 | length 21.2
  Top Layer w0.152: U1.58@28.612,49.264 30.804,49.264 v2(33.104,51.564)
  Bottom Layer w0.152: v2(33.104,51.564) 37.012,55.472 44.836,55.472 45.873,56.509 46.81,56.509 J2.5@46.838,56.537
MCU_nSLEEP: J2.15 U1.16 | length 47.9
  Top Layer w0.152: U1.16@19.162,54.214 19.236,54.288 19.236,55.382 v2(19.311,55.457)
  Bottom Layer w0.152: v2(19.311,55.457) 19.311,47.443 cw(c18.626,47.264) 19.311,47.085 19.311,38.947 19.977,38.281 23.857,38.281 24.523,38.947 40.731,38.947 45.621,43.837 J2.15@46.838,43.837
MCU_PWM1: J2.3 U1.43 | length 33.1
  Top Layer w0.152: U1.43@24.162,42.814 24.236,42.888 24.236,43.679 v2(24.669,44.112)
  Bottom Layer w0.152: v2(24.669,44.112) 24.669,49.697 27.603,52.631 33.186,52.631 36.575,56.02 36.577,56.018 40.808,56.018 43.866,59.077 J2.3@46.838,59.077
MCU_SCLK: J2.11 U1.61 U3.17 | length 50.6
  Top Layer w0.152: U3.17@25.72,64.253 32.706,64.253 34.341,62.618 34.341,55.729 29.449,50.838 28.686,50.838 U1.61@28.612,50.764 28.572,50.804 27.763,50.804 27.597,50.971 26.884,50.971 25.864,49.95 25.864,49.573 v2(25.827,49.537)
  Bottom Layer w0.152: v2(25.827,49.537) 25.827,48.978 27.542,47.264 40.562,47.264 42.215,48.917 J2.11@46.838,48.917
MCU_SDI: J2.7 U1.60 U3.18 | length 48.2
  Top Layer w0.152: U3.18@25.72,64.753 32.913,64.753 34.803,62.863 34.803,55.258 29.882,50.338 28.686,50.338 U1.60@28.612,50.264 28.598,50.249 27.278,50.249 v2(27.263,50.235)
  Bottom Layer w0.152: v2(27.263,50.235) 27.592,50.563 36.708,50.563 39.685,53.541 44.697,53.541 45.153,53.997 J2.7@46.838,53.997
MCU_SDO: J2.9 U1.59 U3.19 | length 50.9
  Top Layer w0.152: U3.19@25.72,65.253 33.12,65.253 35.341,63.032 35.341,61.161 35.155,60.975 35.155,54.569 30.424,49.838 28.686,49.838 U1.59@28.612,49.764 28.538,49.69 27.737,49.69 27.583,49.537 27.155,49.537 v2(27.067,49.449)
  Bottom Layer w0.152: v2(27.067,49.449) 28.285,48.232 38.285,48.232 41.51,51.457 J2.9@46.838,51.457
MCU_SO: U1.9
MCU_STATUS: D2.2 U1.26 | length 10.1
  Top Layer w0.152: D2.2@8.345,44.812 13.546,44.812 16.424,47.69 17.138,47.69 U1.26@17.212,47.764
NetC2_1: C2.1 IC1.1 R6.2 USB1.6 USB1.7 USB1.8 USB1.9 USB1.10 USB1.11 | length 28.8
  Top Layer w0.203: v3(6.416,14.01) 6.358,13.951 6.358,13.463 6.874,12.946 7.158,12.946 7.356,12.748 R6.2@7.356,12.648 7.356,12.602 7.555,12.403 C2.1@8.626,12.403 ; IC1.1@8.128,19.726 8.14,19.726 8.141,19.724 8.141,18.673 v3(8.154,18.66)
  Top Layer w0.254: USB1.10@1.37,16.595 1.589,16.814 2.507,16.814 2.829,17.136 2.829,17.472 USB1.11@3.456,18.099 ; USB1.7@1.524,24.48 2.873,24.48 4.061,23.292 USB1.6@4.061,23.229 ; USB1.11@3.67,18.083 3.456,18.083 2.88,18.659 2.458,18.659 2.193,18.924 2.193,19.047 1.648,19.593 1.524,19.593 1.524,21.468 2.085,22.028 2.547,22.028 3.511,22.993 USB1.6@3.824,22.993 ; USB1.11@3.824,18.068 4.116,18.068 4.726,17.457 4.726,17.182 5.244,16.663 5.244,15.182 v3(6.416,14.01)
  Bottom Layer w0.254: v3(6.416,14.01) 6.416,15.278 8.154,17.016 v3(8.154,18.66)
NetC11_1: C11.1 R13.2 XDS1.96 | length 5.5
  Top Layer w0.203: R13.2@13.401,10.174 13.44,10.135 C11.1@14.88,10.135 14.88,10.235 15.56,10.916 XDS1.96@15.56,13.883
NetC12_1: C12.1 R14.1 R16.2 XDS1.70 | length 10
  Top Layer w0.203: R14.1@12.929,29.535 12.941,29.522 14.477,29.522 R16.2@14.49,29.509 ; 13.769,29.482 13.769,28.019 16.006,28.019 16.561,27.463 16.561,24.534 16.308,24.28 XDS1.70@15.607,24.28
NetC15_1: C15.1 C16.1 C17.1 XDS1.87 XDS1.115 | length 17.8
  Top Layer w0.203: XDS1.87@15.619,17.488 16.78,17.49 ; C15.1@22.919,10.149 C16.1@24.452,10.149 ; 24.307,14.467 24.307,14.465 24.755,14.017 24.755,13.596 24.309,13.15 24.309,12.382 XDS1.115@24.307,12.38 24.307,11.198 24.452,11.053 C16.1@24.452,10.149 ; C17.1@25.985,10.149 C16.1@24.452,10.149
  Top Layer w0.508: 16.78,17.49 21.285,17.49 24.307,14.467
NetC18_1: C18.1 XDS1.88 Y1.3 | length 6.4
  Top Layer w0.203: C18.1@11.753,19.488 11.753,18.535 11.307,18.089 11.307,17.939 11.806,17.44 12.013,17.233 12.013,17.224 12.156,17.08 XDS1.88@15.607,17.08
NetC19_1: C19.1 XDS1.89 Y1.1 | length 5
  Top Layer w0.203: C19.1@12.879,14.042 12.953,14.116 12.953,15.843 12.907,15.889 12.907,15.989 13.606,16.688 XDS1.89@15.619,16.688
NetC20_1: C20.1 C21.1 IC3.3 R17.1 XDS1.9 | length 8.3
  Top Layer w0.203: XDS1.9@31.019,17.088 31.021,17.09 31.721,17.09 32.489,17.858 32.489,18.162 33.456,19.128 R17.1@33.556,19.128 C20.1@33.556,20.651 C21.1@33.556,22.174 33.556,22.967 33.618,23.029 33.618,23.574 33.717,23.672 IC3.3@33.892,23.672
NetC22_1: C22.1 R18.1 XDS1.68 | length 3.4
  Top Layer w0.203: R18.1@13.529,23.27 C22.1@13.529,24.78 ; C22.1@13.825,24.976 13.827,24.978 14.097,24.978 14.206,25.088 XDS1.68@15.619,25.088
NetC25_2: C25.2 U1.32 | length 2.3
  Top Layer w0.152: C25.2@15.558,43.688 16.101,44.231 16.101,44.492 16.299,44.69 17.138,44.69 U1.32@17.212,44.764
NetC69_1: C69.1 Q8.4 R51.2 TP39.1 | length 13
  Top Layer w0.152: Q8.4@88.024,29.513 88.036,29.526 88.683,29.526 88.964,29.807 88.964,35.689 88.897,35.756 88.897,35.781 88.37,36.308 C69.1@88.37,36.325 88.452,36.243 R51.2@90.233,36.243 90.233,36.268 90.674,36.709 TP39.1@93.294,36.709
NetC82_2: C82.2 R69.1 R70.2
NetD1_1: D1.1 R28.2 | length 2.4
  Top Layer w0.152: R28.2@4.305,39.921 D1.1@6.745,39.921
NetD2_1: D2.1 R29.2 | length 2.6
  Top Layer w0.152: R29.2@4.277,44.582 4.507,44.812 D2.1@6.745,44.812
NetD3_1: D3.1 R30.2 | length 2.7
  Top Layer w0.152: R30.2@4.042,37.724 D3.1@6.745,37.724
NetD4_1: D4.1 R31.2 | length 2.6
  Top Layer w0.152: R31.2@4.252,42.296 4.466,42.511 D4.1@6.745,42.511
NetD5_1: D5.1 F1.1 Q4.1 Q4.2 Q4.3
NetD5_2: D5.2 Q1.2
NetD6_1: D6.1 R62.2 | length 3.3
  Top Layer w0.381: R62.2@44.368,80.711 44.394,80.685 44.394,77.473 D6.1@44.42,77.447
NetD7_1: D7.1 R63.2 | length 3.2
  Top Layer w0.381: R63.2@40.566,80.661 40.585,80.642 D7.1@40.585,77.466
NetD10_1: D10.1 R44.2 | length 3.2
  Top Layer w0.254: R44.2@118.016,46.438 118.016,45.682 D10.1@119.748,43.951
NetJ3_2: J3.2 R24.1 | length 3.2
  Top Layer w0.152: J3.2@2.832,51.085 2.832,52.451 4.113,53.733 R24.1@4.138,53.733
NetJ20_1: J20.1 R67.1 | length 7.7
  Top Layer w0.152: v2(36.459,67.373) 36.459,68.284 R67.1@36.575,68.4
  Bottom Layer w0.152: J20.1@32.026,62.555 36.372,66.901 36.372,67.286 v2(36.459,67.373)
NetJ23_2: J23.2 Q8.5 Q8.6 Q8.7 Q8.8 Q8.9@91.924,31.418
NetLED1_1: LED1.1 R19.1 | length 29.4
  Top Layer w0.203: v3(7.813,11.19) 7.832,11.19 8.073,10.949 LED1.1@8.753,10.949 ; v3(32.724,10.434) R19.1@33.59,10.434
  Bottom Layer w0.203: v3(7.813,11.19) 8.321,11.698 12.262,11.698 13.888,10.073 27.803,10.073 29.988,12.257 30.901,12.257 v3(32.724,10.434)
NetLED2_1: LED2.1 R20.1 | length 22.6
  Top Layer w0.203: v3(9.769,10.835) 10.721,10.835 LED2.1@10.785,10.899 ; v3(29.632,10.428) 29.635,10.431 30.423,10.431 R20.1@30.426,10.434
  Bottom Layer w0.203: v3(9.769,10.835) 10.328,10.276 12.766,10.276 13.452,9.59 28.794,9.59 v3(29.632,10.428)
NetQ1_1: Q1.1 R33.2
NetQ1_3: Q1.3 Q4.4 R32.2
NetQ7_4: Q7.4 R47.1 TP34.1 | length 19.8
  Top Layer w0.152: R47.1@100.677,35.72 102.754,35.72 TP34.1@103.744,36.709 ; Q7.4@103.588,27.083 103.588,26.98 104.366,26.203 v5(105.988,26.203)
  Bottom Layer w0.152: TP34.1@103.744,36.709 104.3,36.709 104.922,36.087 106.267,36.087 107.184,35.17 107.184,27.399 v5(105.988,26.203)
NetR2_1: R2.1 USB1.5 | length 6.3
  Top Layer w0.406: USB1.5@3.837,21.83 5.171,21.83 6.772,23.431 6.772,25.241 6.414,25.599 6.389,25.599 6.117,25.871 R2.1@6.117,25.896
NetR5_1: R5.1 USB1.1 | length 3.6
  Top Layer w0.406: USB1.1@3.898,19.23 5.87,19.23 6.385,18.715 6.385,18.085 R5.1@6.582,17.888
NetR9_1: R9.1 XDS1.63 | length 20.8
  Top Layer w0.203: v3(17.084,25.592) 17.084,26.481 17.507,26.904 XDS1.63@17.507,27.182 ; v3(33.798,27.624) 33.856,27.683 33.964,27.683 34.668,28.386 R9.1@34.768,28.386
  Bottom Layer w0.203: v3(17.084,25.592) 17.912,25.592 18.141,25.364 31.537,25.364 v3(33.798,27.624)
NetR10_1: R10.1 XDS1.62 | length 23.5
  Top Layer w0.203: v3(17.313,24.805) 17.356,24.848 17.356,25.146 17.592,25.382 17.592,26.38 17.906,26.693 XDS1.62@17.906,27.182 ; v3(34.534,29.224) 34.534,29.72 34.733,29.919 R10.1@34.768,29.919
  Bottom Layer w0.203: v3(17.313,24.805) 17.364,24.754 31.715,24.754 34.534,27.573 v3(34.534,29.224)
NetR11_1: R11.1 XDS1.61 | length 26.4
  Top Layer w0.203: v3(18.05,23.89) 17.999,23.941 17.999,26.283 18.306,26.59 XDS1.61@18.306,27.182 ; R11.1@34.768,31.452 34.868,31.452 35.066,31.253 35.066,30.8 v3(35.093,30.774)
  Bottom Layer w0.203: v3(18.05,23.89) 18.05,23.857 18.321,23.586 31.207,23.586 35.093,27.472 v3(35.093,30.774)
NetR12_1: R12.1 XDS1.60 | length 7.1
  Top Layer w0.203: R12.1@13.825,26.422 13.925,26.422 14.417,26.915 16.015,26.915 v3(16.018,26.913) ; v3(18.507,26.024) 18.507,26.106 18.707,26.307 XDS1.60@18.707,27.78
  Bottom Layer w0.203: v3(16.018,26.913) 16.491,26.439 16.956,26.439 17.371,26.024 v3(18.507,26.024)
NetR15_2: R15.2 XDS1.59 | length 2.2
  Top Layer w0.203: R15.2@18.119,29.482 18.219,29.482 19.117,28.583 XDS1.59@19.117,27.79
NetR19_2: R19.2 XDS1.3 | length 7.3
  Top Layer w0.203: XDS1.3@30.409,14.68 30.307,14.68 29.988,14.361 29.988,13.756 32.321,11.422 33.701,11.422 34.69,10.434 R19.2@34.79,10.434
NetR20_2: R20.2 XDS1.4 | length 6.7
  Top Layer w0.203: XDS1.4@31.017,15.086 29.972,15.086 29.607,14.721 29.607,13.578 31.626,11.559 R20.2@31.626,10.434
NetR34_1: R34.1 U2.22 | length 3.3
  Top Layer w0.152: R34.1@92.65,42.61 92.65,44.842 92.932,45.125 U2.22@92.932,45.765
nFAULT: R31.1 U1.27 | length 16.5
  Top Layer w0.152: R31.1@2.228,42.694 R31.1@2.228,42.719 ; R31.1@2.627,42.296 R31.1@2.652,42.296 2.677,42.296 4.211,43.83 13.779,43.83 16.234,46.285 16.234,46.98 16.396,47.143 16.449,47.143 16.491,47.143 U1.27@16.612,47.264
nSCS_DRV: J2.6 TP12.1 U2.13 | length 51.4
  Top Layer w0.152: TP12.1@54.958,55.472 55.332,55.846 55.332,56.679 60.427,61.773 68.94,61.773 81.435,49.278 90.665,49.278 91.302,49.915 U2.13@91.782,49.915
  Bottom Layer w0.152: J2.6@49.378,56.537 53.963,56.537 TP12.1@54.958,55.541
nSLEEP: J2.16 TP19.1 U2.18 | length 47.3
  Top Layer w0.152: TP19.1@55.012,39.686 70.376,39.686 76.077,45.387 89.26,45.387 91.254,47.381 91.749,47.381 U2.18@91.782,47.415
  Bottom Layer w0.152: J2.16@49.378,43.837 53.528,39.686 TP19.1@55.012,39.686
NU/LIN: C80.1 D9.1 J18.1 J19.3 J21.8 U3.31 | length 38.7
  Top Layer w0.254: v2(17.552,84.367) 17.484,84.299 17.484,82.704 J18.1@16.972,82.192 17.022,82.142 J19.3@17.022,78.921 17.022,75.977 D9.1@17.052,75.947 17.052,74.002 C80.1@17.996,73.058 ; C80.1@17.988,72.859 17.988,72.669 18.115,72.542 18.289,72.542 22.022,68.809 22.022,68.622 U3.31@22.068,68.576 ; v2(24.623,93.846) 24.623,93.942 24.835,94.154 J21.8@24.835,99.033
  Bottom Layer w0.254: v2(17.552,84.367) 18.458,85.273 18.458,92.789 19.515,93.846 v2(24.623,93.846)
OUT1: C49.2 C50.2 J6.1 TP31.1 U2.9
OUT2: C52.2 C54.2 J6.2 TP32.1 U2.10
OUT3: C56.2 C61.2 J8.2 TP35.1 U2.40
  other v1: 100.398,51.097 100.869,51.495 101.281,51.98 101.815,52.416 102.345,52.908 101.448,53.122 102.857,53.455 102.017,53.655 103.369,53.99 102.615,54.235 103.129,54.767
OUT4: C51.2 C60.2 J7.1 TP38.1 U2.1
  other v1: 99.377,51.773 100.072,51.931 98.808,52.111 99.652,52.404 100.598,52.416 99.147,52.676 100.145,52.755
OUT5: C53.2 C55.2 J7.2 TP33.1 U2.7
OUT6: C57.2 C59.2 J8.1 TP36.1 U2.38
  other v1: 102.349,50 101.598,50.071 103.129,50.14 102.069,50.65 101.394,50.712 102.707,50.789 103.926,50.893 103.252,50.92 101.88,51.243 103.085,51.488 102.432,51.551 103.753,51.622 102.932,52.044 103.545,52.278 103.926,52.886
OUT7: C71.2 C90.2 J10.2 TP46.1 U2.36 | length 59.9
  Top Layer w0.254: U2.36@97.755,48.917 97.803,48.917 97.805,48.919 98.473,48.919 v1(99.103,48.289)
  Mid-Layer 2 w0.254: v1(99.103,48.289) 99.962,49.148 104.075,49.148 127.889,72.961 127.889,80.899 131.718,84.728 TP46.1@137.658,84.728
OUT8: C64.2 C87.2 J10.1 TP40.1 U2.35 | length 2.8
  Top Layer w0.254: U2.35@97.582,48.415 98.263,48.415 98.574,48.105 98.574,48.07 99.012,47.631 v1(100.055,47.631)
  other v1: 101.174,47.665 102.566,47.665
OUT9: C72.2 C91.2 J11.2 TP47.1 U2.34 | length 2
  Top Layer w0.254: U2.34@97.727,47.88 98.155,47.88 99.238,46.797
  other v1: 99.735,46.778 101.829,46.811 103.731,46.811
OUT10: C65.2 C88.2 J11.1 TP41.1 U2.33 | length 3.2
  Top Layer w0.254: U2.33@97.582,47.415 97.584,47.413 98.047,47.413 99.535,45.926 v1(100.169,45.926)
  other v1: 104.43,45.926 102.172,45.952
OUT11: C73.2 C92.2 J12.2 J23.1 TP48.1 U2.32 | length 8.6
  Top Layer w0.254: U2.32@97.582,46.915 97.584,46.913 97.97,46.913 99.809,45.074 v1(100.776,45.074) 100.787,45.084 102.593,45.084 v1(102.604,45.095) 102.615,45.084 104.419,45.084 v1(104.43,45.074) 105.352,45.074
OUT12: C66.2 C89.2 J12.1 TP42.1 U2.31 | length 5.3
  Top Layer w0.254: U2.31@97.582,46.415 97.753,46.415 97.881,46.287 98.021,46.287 100.321,43.987 v1@101.911,43.987
  other v1: 103.645,43.978 105.702,43.957 101.88,44.018
PA30: J4.4 U1.37 | length 41.4
  Top Layer w0.152: U1.37@21.162,42.814 21.162,43.933 v5(21.683,44.454) ; v5(32.137,40.182) 32.137,37.978 35.726,34.389 35.726,26.966 J4.4@44.638,18.055
  Bottom Layer w0.152: v5(21.683,44.454) 21.683,44.434 23.922,42.194 29.172,42.194 30.444,40.923 31.396,40.923 v5(32.137,40.182)
PA31: J4.5 U1.39 | length 50.3
  Top Layer w0.152: U1.39@22.162,42.814 22.162,43.987 23.114,44.94 v5(25.822,44.94) ; v5(33.635,46.081) 37.883,41.833 37.883,40.087 46.696,31.274 46.696,17.572 J4.5@44.638,15.515
  Bottom Layer w0.152: v5(25.822,44.94) 26.964,46.081 v5(33.635,46.081)
PB2: J4.2 U1.50 | length 32.6
  Top Layer w0.152: U1.50@28.612,45.264 33.01,45.264 36.586,41.689 36.586,29.033 40.018,25.601 42.171,25.601 J4.2@44.638,23.135
PB3: J4.3 U1.51 | length 36.3
  Top Layer w0.152: U1.51@28.612,45.764 28.012,45.764 27.84,45.592 27.818,45.592 27.413,45.187 27.413,44.538 27.692,44.259 33.12,44.259 36.139,41.239 36.139,29.093 J4.3@44.638,20.595
PB20: J4.6 U1.19 | length 92.5
  Top Layer w0.152: v5(13.637,53.941) 13.677,53.901 16.065,53.901 16.264,54.1 17.355,54.1 18.269,53.185 18.269,51.699 18.007,51.436 17.984,51.436 17.812,51.264 U1.19@17.212,51.264 ; v5(25.279,48.713) 25.279,47.855 25.614,47.519 v5(25.614,47.41) ; v5(35.471,46.654) 35.471,47.002 39.162,43.311 41.056,43.311 47.254,37.113 47.254,15.591 J4.6@44.638,12.975
  Bottom Layer w0.152: v5(13.637,53.941) 16.862,57.166 23.752,57.166 24.736,56.182 24.736,54.706 24.186,54.156 24.186,43.912 24.469,43.629 24.869,43.629 25.152,43.912 25.152,45.699 24.954,45.897 24.954,47.683 25.279,48.008 v5(25.279,48.713) ; v5(25.614,47.41) 25.993,47.41 26.712,46.691 35.435,46.691 v5(35.471,46.654)
PB24: J4.7 U1.23 | length 82.6
  Top Layer w0.152: U1.23@17.212,49.264 17.253,49.224 18.661,49.224 v5(18.701,49.183)
  Mid-Layer 2 w0.152: v5(18.701,49.183) 28.312,39.572 37.322,39.572 v5(38.492,40.743) ; v5(42.866,33.34) 42.866,12.206 J4.7@44.638,10.435
  Bottom Layer w0.152: v5(38.492,40.743) 40.034,39.201 40.626,39.201 45.516,44.091 45.673,44.091 46.965,45.382 ccw(c46.838,46.377) 47.832,46.249 48.962,47.379 49.793,47.379 50.38,46.792 50.38,45.853 49.901,45.374 49.273,45.374 48.145,44.246 48.145,40.755 45.944,38.553 45.944,36.418 v5(42.866,33.34)
PI_IN: C33.1 C34.1 C35.1 C39.2 L1.1 Q4.5 Q4.6 Q4.7 Q4.8 Q4.9@123.011,40.548 R66.1 R75.1
PVDD: C36.1 C37.1 C38.1 C44.1 C45.2 C46.2 D10.2 J23.3 L1.2 Q7.5 Q7.6 Q7.7 Q7.8 Q7.9@101.683,30.883 R64.2 R66.2 R75.2 R76.2 TP20.1 U2.4 U2.6 U2.37 | length 0.1
  Top Layer w0.152: C45.2@95.053,55.497 C45.2@95.064,55.486 ; C46.2@95.985,55.397 C46.2@95.985,55.494
  other v1: 19.236,59.889 20.323,59.889 94.871,60.337 95.705,60.337 96.594,60.337 94.871,61.443 95.705,61.443 96.594,61.443
PVDD_ADC: R76.1 R77.2 U1.10 | length 5.6
  Top Layer w0.152: U1.10@22.162,54.214 22.162,55.243 22.049,55.356 22.049,55.682 21.315,56.416 R76.1@21.315,57.4 21.457,57.258 R77.2@23.36,57.258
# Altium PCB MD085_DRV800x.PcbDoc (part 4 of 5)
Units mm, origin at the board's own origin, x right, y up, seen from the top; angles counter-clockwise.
Board outline 152.66 x 101.89 mm, 4 copper layers (Top Layer, Mid-Layer 1, Mid-Layer 2, Bottom Layer), stack 2.355 mm thick; 265 components, 148 nets, 849 pads, 1494 vias.
Unrouted connection lines stored in the file: 2.

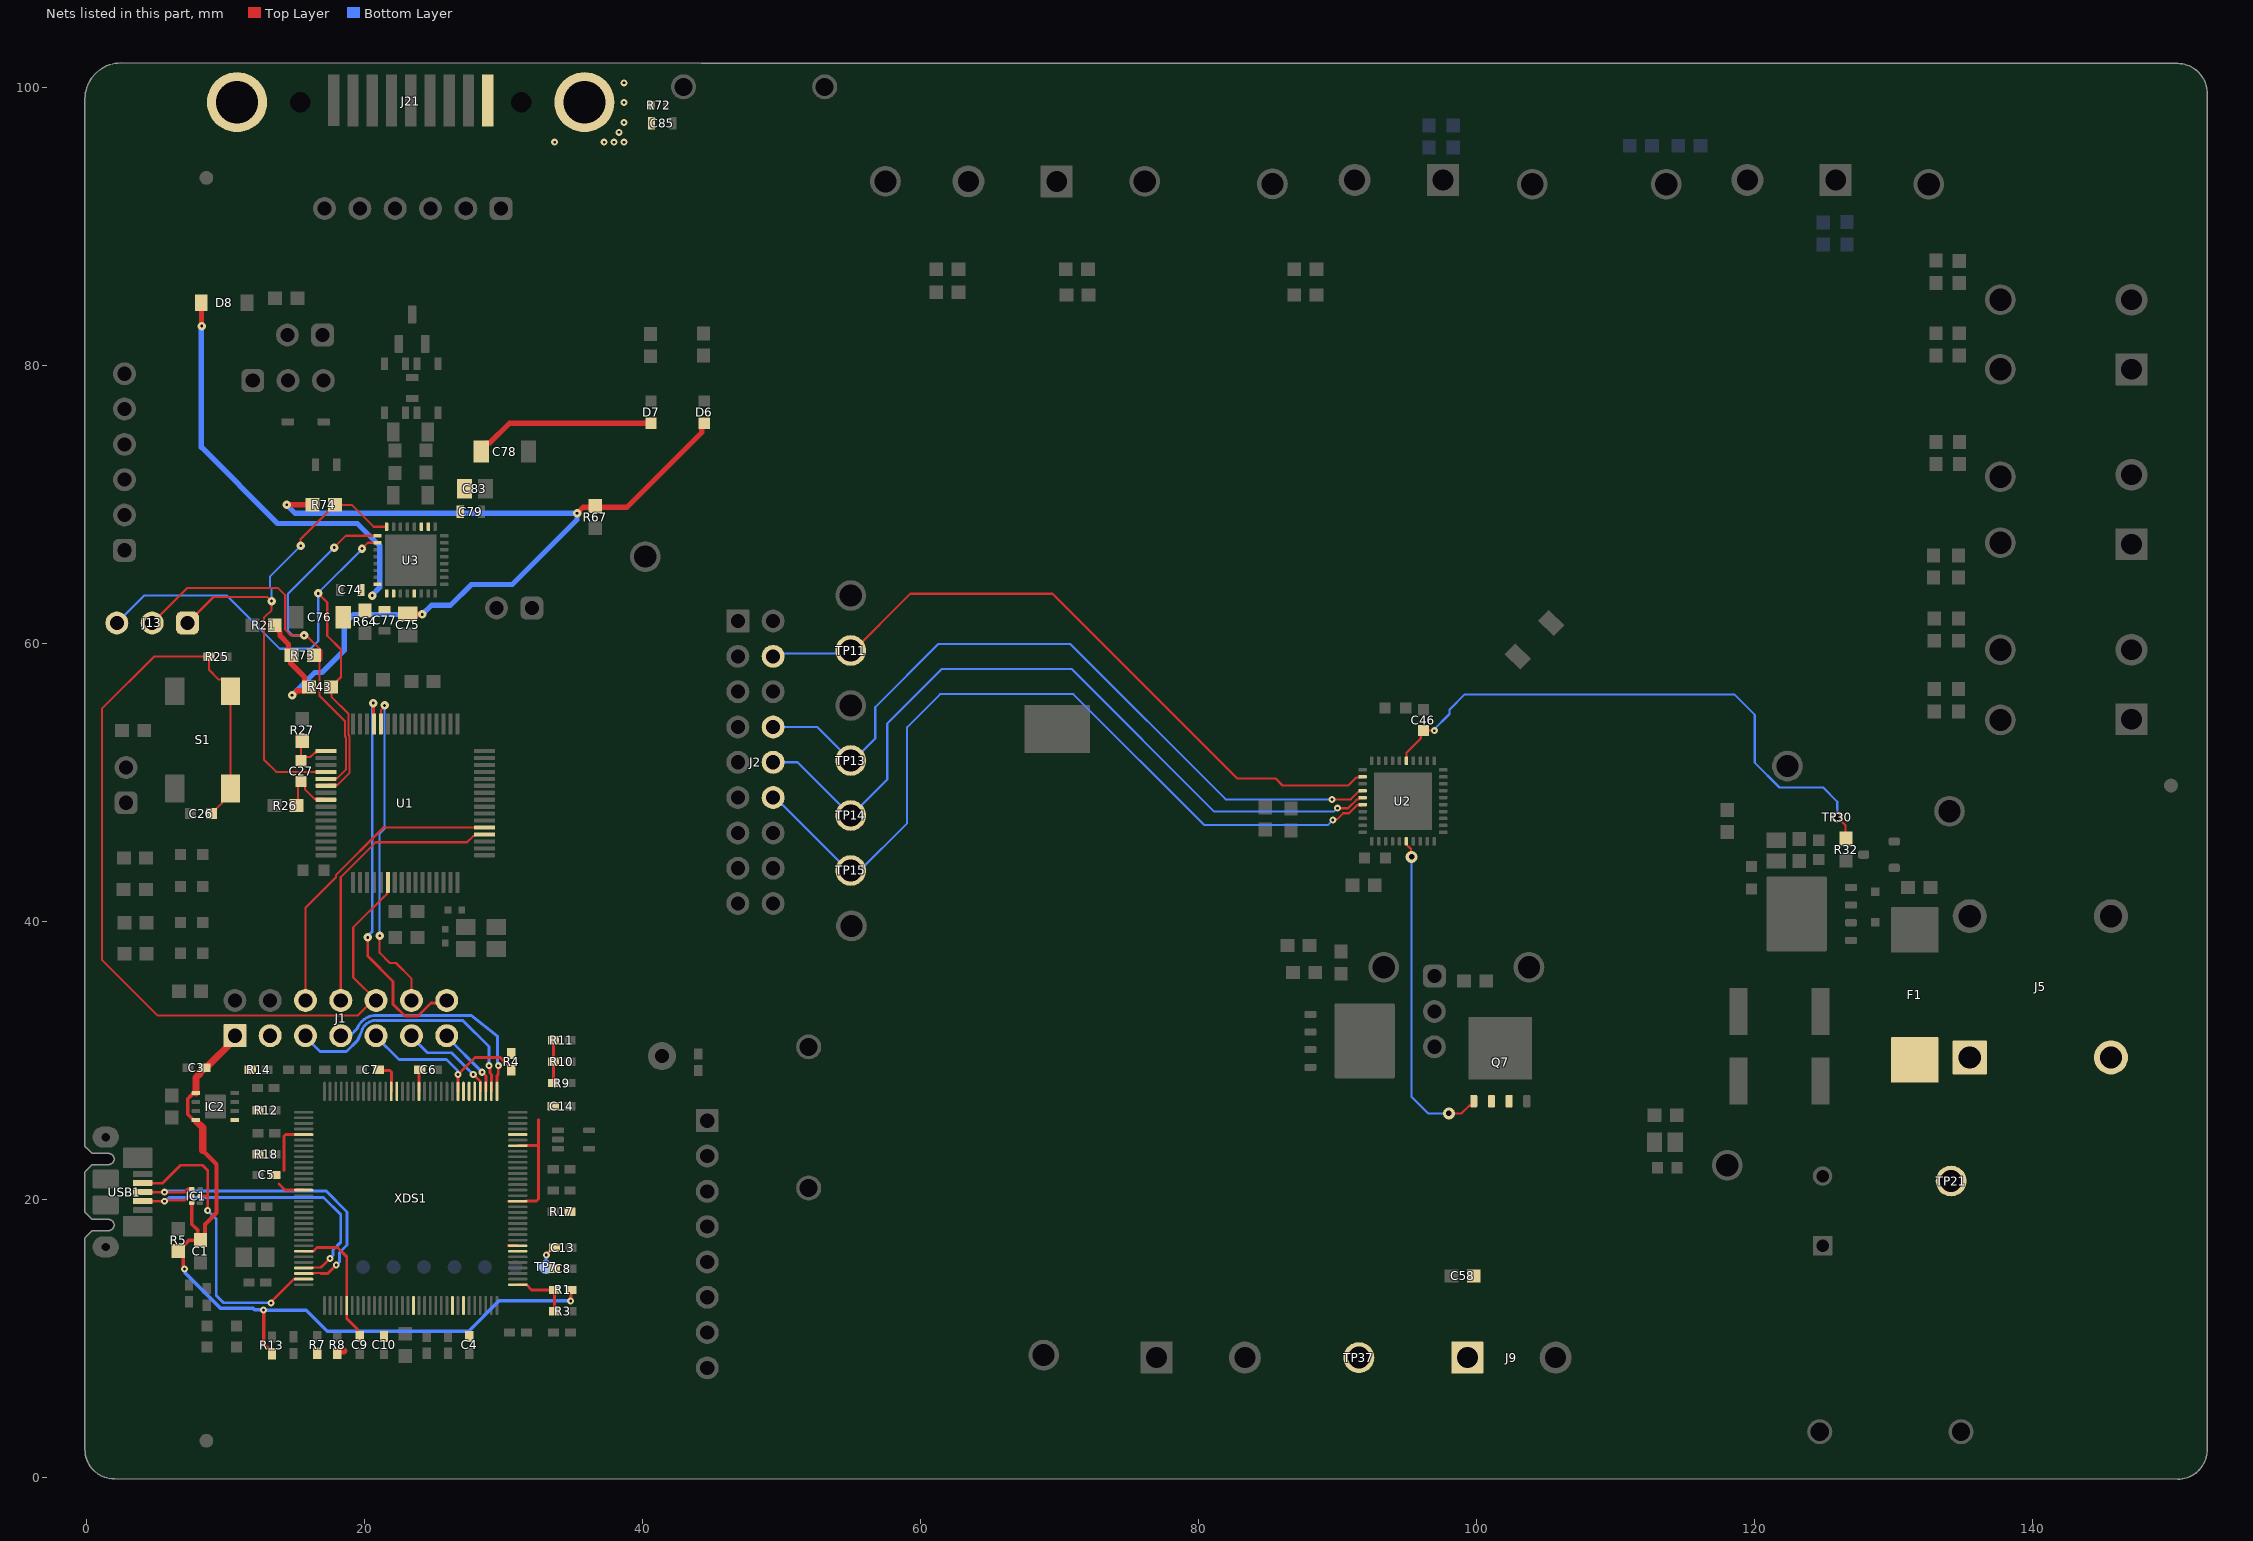
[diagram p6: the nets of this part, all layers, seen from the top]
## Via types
v1: diameter 0.5, hole 0.2, Top Layer to Bottom Layer, tented both sides, 1346 vias
v2: diameter 0.61, hole 0.2, Top Layer to Bottom Layer, tented both sides, 54 vias
v3: diameter 0.508, hole 0.203, Top Layer to Bottom Layer, tented both sides, 46 vias
v4: diameter 0.5, hole 0.2, Top Layer to Bottom Layer, 16 vias
v5: diameter 0.864, hole 0.406, Top Layer to Bottom Layer, tented both sides, 15 vias
v6: diameter 0.711, hole 0.356, Top Layer to Bottom Layer, tented both sides, 10 vias
v7: diameter 5, hole 4.3, Top Layer to Bottom Layer, 3 vias
v8: diameter 0.61, hole 0.203, Top Layer to Bottom Layer, tented both sides, 3 vias
v9: diameter 5, hole 4.5, Top Layer to Bottom Layer, 1 vias

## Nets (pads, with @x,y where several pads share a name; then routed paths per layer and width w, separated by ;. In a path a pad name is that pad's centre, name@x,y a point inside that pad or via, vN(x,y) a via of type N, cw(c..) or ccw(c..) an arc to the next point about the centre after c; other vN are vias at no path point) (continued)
PWM1: J2.4 TP11.1 U2.12 | length 50.9
  Top Layer w0.152: J2.4@49.378,59.077 J2.4@49.588,59.287 ; TP11.1@54.748,59.287 TP11.1@54.958,59.497 ; TP11.1@54.958,59.282 59.253,63.576 69.469,63.576 82.756,50.289 85.522,50.289 86.022,49.789 90.745,49.789 91.322,50.366 91.734,50.366 U2.12@91.782,50.415
  Bottom Layer w0.152: J2.4@49.378,59.077 49.588,59.287 54.748,59.287 TP11.1@54.958,59.497
REF_TARGET_VCC: XDS1.120
RST: C26.2 J1.10 R25.1 S1.1 S1.2 U1.38 | length 71.8
  Top Layer w0.152: C26.2@8.98,47.764 9.72,48.504 9.72,48.94 S1.2@10.344,49.564 S1.1@10.344,56.564 10.344,56.78 9.72,57.403 9.504,57.403 8.798,58.11 R25.1@8.798,59.055 4.838,59.055 1.092,55.309 1.092,37.249 5.112,33.229 19.48,33.229 20.581,34.33 J1.10@20.818,34.33 19.177,35.971 19.177,39.583 21.382,41.788 21.398,41.788 21.588,41.979 21.588,41.994 21.59,41.996 21.59,42.518 U1.38@21.662,42.59
SCLK: J2.12 TP15.1 U2.16 | length 58.9
  Top Layer w0.152: v1(89.637,47.303) 89.704,47.37 89.967,47.37 90.386,47.789 90.799,47.789 91.377,48.366 91.734,48.366 U2.16@91.782,48.415
  Bottom Layer w0.152: J2.12@49.378,48.917 49.546,48.917 54.79,43.673 TP15.1@54.958,43.673 TP15.1@54.958,43.59 ; TP15.1@54.679,43.534 54.958,43.534 55.014,43.59 TP15.1@55.014,43.673 ; TP15.1@55.014,43.534 55.467,43.534 59.013,47.079 59.013,53.984 61.392,56.363 70.973,56.363 80.402,46.934 89.268,46.934 v1(89.637,47.303)
SDI: J2.8 TP13.1 U2.14 | length 53.2
  Top Layer w0.152: v1(89.569,48.789) 90.937,48.789 91.515,49.366 91.734,49.366 U2.14@91.782,49.415
  Bottom Layer w0.152: J2.8@49.378,53.997 52.547,53.997 TP13.1@54.958,51.585 ; TP13.1@54.958,51.408 56.723,53.172 56.723,55.427 61.265,59.969 70.743,59.969 81.924,48.789 v1(89.569,48.789)
SDO: J2.10 TP14.1 U2.15 | length 55.4
  Top Layer w0.152: v1(89.97,48.154) 90.733,48.154 91.348,48.768 91.461,48.768 91.607,48.915 U2.15@91.782,48.915
  Bottom Layer w0.152: J2.10@49.378,51.457 51.131,51.457 TP14.1@54.958,47.629 ; TP14.1@54.974,47.613 57.582,50.221 57.582,54.247 61.501,58.166 70.858,58.166 81.115,47.909 89.707,47.909 89.951,48.154 v1(89.97,48.154)
SH_HS: C58.2 J9.1 Q7.1 Q7.2 Q7.3 TP37.1 U2.26 | length 24
  Top Layer w0.152: U2.26@94.932,45.765 94.981,45.716 94.981,45.497 95.079,45.399 95.257,45.221 95.257,44.7 v5(95.308,44.65) ; v5(97.977,26.203) 98.898,26.203 99.443,26.748 99.601,26.748 99.778,26.925 Q7.1@99.778,27.083
  Bottom Layer w0.152: v5(95.308,44.65) 95.308,27.383 96.488,26.203 v5(97.977,26.203)
SHIELD_GND: C85.1 J21.5 J21.10 J21.11 R72.2
  other v1: 33.665,96.064 37.221,96.064 37.932,96.064 38.644,96.064 38.288,96.775 38.644,97.487 38.644,98.909 38.644,100.331
SWCLK: J1.14 U1.13 | length 29.1
  Top Layer w0.203: v2(20.217,38.862) 20.217,37.525 22.044,35.699 22.044,34.051 22.892,33.203 23.825,33.203 24.768,34.147 25.715,34.147 J1.14@25.898,34.33 ; v2(20.607,55.718) 20.635,55.691 20.635,54.241 U1.13@20.662,54.214
  Bottom Layer w0.203: v2(20.217,38.862) 20.217,38.972 20.539,39.293 20.539,55.65 v2(20.607,55.718) ; J1.14@25.898,34.33 J1.14@26.101,34.533
SWDIO: J1.12 U1.12 | length 24
  Top Layer w0.152: v2(21.073,38.972) 21.073,37.752 21.805,37.02 22.25,37.02 23.358,35.912 J1.12@23.358,34.33 ; U1.12@21.162,54.214 21.164,54.216 21.164,55.193 21.426,55.455 v2(21.426,55.551)
  Bottom Layer w0.152: v2(21.073,38.972) 21.073,46.321 21.426,46.673 v2(21.426,55.551)
UART1_RX: J1.6 U1.53 | length 22
  Top Layer w0.152: J1.6@15.738,34.33 15.738,40.984 17.926,43.171 17.926,43.338 21.352,46.764 U1.53@28.612,46.764
UART1_TX: J1.8 U1.52 | length 20.5
  Top Layer w0.152: J1.8@18.278,34.33 18.278,43.192 20.79,45.703 27.357,45.703 27.796,46.143 27.891,46.143 28.012,46.264 U1.52@28.612,46.264
VBAT: F1.2 J5.1 TP21.1
VBUS_DETECT: R1.2 R3.2 XDS1.1 | length 4.3
  Top Layer w0.203: XDS1.1@31.007,13.88 31.623,13.88 32.004,13.499 R1.2@33.644,13.499 R3.2@33.644,11.976
VCC1: C75.1 D6.2 R21.2 R43.2 R67.2 R73.2 R74.2 U3.13 | length 70.5
  Top Layer w0.381: R21.2@13.423,61.286 13.573,61.286 13.833,61.026 13.833,60.872 13.902,60.803 13.902,60.565 14.52,59.947 14.52,59.377 R73.2@14.67,59.226 ; v2(14.39,69.975) R74.2@16.252,69.975 ; R73.2@14.745,59.151 R73.2@14.67,59.226 ; v2(14.768,56.283) 14.83,56.283 15.142,56.594 15.669,56.594 15.903,56.829 15.903,56.879 15.669,57.113 15.669,57.588 14.67,58.587 R73.2@14.67,59.226 ; C75.1@23.108,62.118 23.122,62.104 24.118,62.104 v2(24.131,62.09) ; v2(35.277,69.364) 35.713,69.8 38.866,69.8 44.243,75.177 44.243,75.671 D6.2@44.42,75.847
  Bottom Layer w0.381: v2(14.39,69.975) 15.002,69.364 v2(35.277,69.364) 35.262,69.349 35.262,68.902 30.613,64.253 27.668,64.253 26.171,62.756 24.797,62.756 v2(24.131,62.09) 19.199,62.09 18.517,61.407 18.517,59.507 16.926,57.917 16.403,57.917 v2(14.768,56.283)
VCC2: C78.1 C79.1 C83.1 D7.2 U3.26 U3.27 | length 13.2
  Top Layer w0.381: C78.1@28.378,73.809 28.378,74.059 28.737,74.419 28.987,74.419 30.415,75.847 D7.2@40.604,75.847
VCP: C46.1 R32.1 TP30.1 U2.5 | length 42
  Top Layer w0.152: U2.5@94.932,51.565 94.932,52.137 95.966,53.17 95.966,53.662 C46.1@96.06,53.756 ; C46.1@96.149,53.733 v1(96.94,53.733) ; TP30.1@125.927,47.506 126.521,46.912 R32.1@126.521,45.826
  Bottom Layer w0.152: v1@96.851,53.756 98.028,54.933 98.028,55.233 99.139,56.343 118.509,56.343 119.986,54.867 119.986,51.432 121.772,49.646 124.905,49.646 125.927,48.624 TP30.1@125.927,47.506
VREF_N: C27.1 R27.2 U1.17 | length 3.3
  Top Layer w0.152: R27.2@15.391,52.814 15.428,52.776 C27.1@15.428,51.564 15.71,51.846 16.099,51.846 16.396,52.143 16.491,52.143 16.612,52.264 U1.17@17.212,52.264
VREF_P: C27.2 R26.2 U1.24 | length 3.9
  Top Layer w0.152: R26.2@15.19,48.764 15.19,49.826 C27.2@15.428,50.064 15.69,49.802 15.69,49.525 16.377,48.838 17.138,48.838 U1.24@17.212,48.764
VSUP: C74.1 C76.1 C77.1 D8.2 R64.1 U3.8 U3.9 U3.10 | length 30
  Top Layer w0.381: D8.2@8.248,84.513 8.264,84.496 8.264,82.855 v2(8.281,82.839)
  Bottom Layer w0.381: v2(8.281,82.839) 8.248,82.806 8.248,74.125 13.733,68.64 19.463,68.64 21.073,67.03 21.073,64.036 20.545,63.508 v2(20.545,63.446)
WAKE1: J13.3 R43.1 U1.22 U3.2 | length 42.9
  Top Layer w0.152: v2(16.652,63.603) 17.302,62.953 17.302,60.56 18.292,59.57 18.292,57.593 18.002,57.302 18.002,57.277 17.603,56.879 17.603,56.175 18.834,54.944 18.834,53.419 18.915,53.339 18.915,50.705 18.048,49.838 17.286,49.838 U1.22@17.212,49.764 ; v2(19.802,66.834) 20.221,67.253 U3.2@20.92,67.253
  Bottom Layer w0.152: J13.3@2.169,61.476 4.154,63.461 10.057,63.461 13.892,59.626 16.095,59.626 16.652,60.183 v2(16.652,63.603) 16.652,63.643 19.802,66.793 v2(19.802,66.834)
WAKE2: J13.2 R73.1 U1.21 U3.1 | length 40.1
  Top Layer w0.152: J13.2@4.709,61.476 7.214,63.982 13.772,63.982 14.279,63.475 14.279,60.998 14.697,60.581 v2(15.636,60.581) 15.724,60.493 15.878,60.493 16.895,59.476 16.895,58.826 ; R73.1@16.745,59.151 16.745,56.238 18.58,54.403 18.58,53.314 18.661,53.234 18.661,50.951 18.048,50.338 17.286,50.338 U1.21@17.212,50.264 ; v2(17.812,66.901) 17.812,66.922 18.642,67.753 U3.1@20.92,67.753
  Bottom Layer w0.152: v2(15.636,60.581) 14.778,60.581 14.778,60.61 14.49,60.898 14.49,63.6 17.79,66.901 v2(17.812,66.901)
WAKE3: J13.1 R74.1 U1.20 U3.32 | length 36.7
  Top Layer w0.152: J13.1@7.249,61.476 9.121,63.348 12.984,63.348 13.277,63.055 v2(13.302,63.055) 13.302,62.405 12.747,61.85 12.747,51.654 13.637,50.764 U1.20@17.212,50.764 ; v2(15.391,67.03) 15.391,67.515 17.428,69.553 17.428,69.578 17.827,69.977 19.072,69.977 20.645,68.403 U3.32@21.57,68.403
  Bottom Layer w0.152: v2(13.302,63.055) 13.302,63.948 13.19,64.06 13.19,64.829 v2(15.391,67.03)
XDS_ID: IC1.2 USB1.4 XDS1.95 | length 21.8
  Top Layer w0.203: USB1.4@4.03,21.195 4.045,21.18 5.455,21.18 6.743,22.468 8.337,22.468 8.702,22.103 8.702,20.258 ; IC1.2@8.164,20.258 8.702,20.258 ; v3(8.702,19.217) 8.702,20.258 ; v3(13.249,12.562) 13.288,12.601 13.288,12.662 14.905,14.279 XDS1.95@15.009,14.279
  Bottom Layer w0.203: v3(8.702,19.217) 9.32,18.599 9.32,13.095 9.837,12.578 13.233,12.578 v3(13.249,12.562)
XDS_RESET_OUT: J1.9 R4.1 XDS1.40 | length 13.2
  Top Layer w0.203: v3(26.717,29.002) 27.93,30.215 29.749,30.215 30.545,29.419 R4.1@30.545,29.319 ; XDS1.40@26.718,27.789 v3@26.718,29.002
  Bottom Layer w0.203: J1.9@20.789,31.741 22.457,30.074 25.891,30.074 26.678,29.286 26.678,29.041 v3(26.717,29.002)
XDS_RXD: J1.7 XDS1.33 | length 15.8
  Top Layer w0.203: XDS1.33@29.507,28.379 29.507,28.912 29.607,29.011 v3(29.607,29.631)
  Bottom Layer w0.203: J1.7@18.273,31.815 18.964,31.815 19.471,32.322 cw(c20.813,31.815) 20.269,33.143 20.273,33.144 20.322,33.165 cw(c20.4,32.977) 20.352,33.174 20.395,33.188 cw(c20.813,31.815) 20.522,33.22 20.666,33.25 27.632,33.25 29.548,31.745 29.548,29.689 v3(29.607,29.631)
XDS_TCK_SWDCLK: J1.13 XDS1.35 | length 5.1
  Top Layer w0.203: v3(28.45,29.16) 28.719,28.891 XDS1.35@28.719,27.788
  Bottom Layer w0.203: J1.13@25.869,31.741 v3(28.45,29.16)
XDS_TDI: XDS1.38
XDS_TDO_SWO: XDS1.37
XDS_TMS_SWDIO: J1.11 XDS1.36 | length 7
  Top Layer w0.203: v3(27.805,29.002) 28.317,28.49 28.317,27.79 XDS1.36@28.319,27.788
  Bottom Layer w0.203: J1.11@23.329,31.741 24.51,30.56 26.248,30.56 v3(27.805,29.002)
XDS_TXD: J1.5 XDS1.34 | length 18.9
  Top Layer w0.203: v3(28.946,29.631) 29.005,29.572 29.005,29.109 29.119,28.994 XDS1.34@29.119,27.788
  Bottom Layer w0.203: J1.5@15.709,31.741 16.788,30.662 18.696,30.662 19.459,31.426 19.519,31.485 19.781,32.129 cw(c20.813,31.815) 20.813,32.894 27.052,32.894 28.946,31 v3(28.946,29.631)
XDS_USB_D_N: IC1.5 USB1.2 XDS1.93 | length 22.5
  Top Layer w0.152: XDS1.93@15.607,15.087 16.215,15.087 16.253,15.124 16.842,15.124 16.868,15.15
  Top Layer w0.203: USB1.2@4.184,19.88 5.593,19.88 v1(5.594,19.879) 5.668,19.953 7.104,19.953 7.409,20.258 IC1.5@7.564,20.258 ; 16.868,15.15 16.878,15.15 v1(17.491,15.763)
  Bottom Layer w0.203: v1(5.594,19.879) 5.654,19.879 5.932,20.157 17.043,20.157 18.271,18.929 18.271,16.927 17.726,16.382 17.726,15.998 v1(17.491,15.763)
XDS_USB_D_P: IC1.4 USB1.3 XDS1.94 | length 24
  Top Layer w0.152: XDS1.94@15.607,14.68 16.384,14.68 16.421,14.718 16.842,14.718 16.868,14.693
  Top Layer w0.203: USB1.3@4.184,20.53 v1(5.594,20.531) v1(5.594,20.531) 7.036,20.531 7.263,20.758 IC1.4@7.564,20.758 ; 16.868,14.693 17.343,14.693 v1(17.952,15.302)
  Bottom Layer w0.203: v1(5.594,20.531) 5.676,20.614 17.232,20.614 18.728,19.118 18.728,16.738 18.183,16.193 18.183,15.532 v1(17.952,15.302)
XDS_VBUS: C1.1 C3.1 IC1.6 IC2.5 IC2.8 J1.1 R1.1 R5.2 R13.1 | length 58.3
  Top Layer w0.254: v3@6.93,15.166 6.93,15.94 R5.2@6.582,16.288 6.582,16.313 7.357,17.088 C1.1@8.169,17.088 ; IC1.6@7.553,19.726 7.553,18.238 7.971,17.82 7.971,17.461 C1.1@8.33,17.461 ; IC2.8@7.654,25.749 7.274,26.129 7.274,27.262 7.467,27.455 7.493,27.455 7.708,27.671 IC2.5@7.853,27.671 ; v3(12.716,12.054) 12.748,12.022 12.748,9.593 13.154,9.187 13.154,9.082 R13.1@13.327,8.909 ; v3(34.814,12.714) 34.814,13.469 R1.1@34.844,13.499
  Top Layer w0.305: C1.1@8.177,17.109 8.504,17.436 8.504,18.219 9.337,19.052 9.337,22.544 8.347,23.535
  Top Layer w0.508: IC2.5@7.853,27.671 7.853,28.77 8.096,29.013 8.096,29.088 8.344,29.336 8.344,29.436 8.39,29.482 8.59,29.482 10.629,31.521 J1.1@10.629,31.741 ; IC2.8@7.899,25.622 8.347,25.174 8.347,23.535
  Bottom Layer w0.254: v3@7.001,15.051 7.075,14.977 7.075,14.727 9.605,12.197 11.954,12.197 12.071,12.079 12.69,12.079 12.741,12.029 15.797,12.029 17.295,10.53 27.473,10.53 29.657,12.714 v3(34.814,12.714)
  other v3: 7.026,15
XDS_VCC: C4.1 C5.1 C6.1 C7.1 C8.1 C9.1 C10.1 C13.1 C14.1 IC2.1 J1.3 R4.2 R7.1 R8.1 R9.2 R10.2 R11.2 R12.2 R14.2 R17.2 R18.2 TP7.1 XDS1.7 XDS1.8 XDS1.16 XDS1.26 XDS1.28 XDS1.39 XDS1.47 XDS1.51 XDS1.52 XDS1.69 XDS1.79 XDS1.90 XDS1.101 XDS1.113 XDS1.122 | length 35.7
  Top Layer w0.203: C5.1@13.529,21.772 C5.1@13.629,21.772 ; 13.827,21.128 14.267,20.688 XDS1.79@15.619,20.688 ; C5.1@13.827,21.574 C5.1@13.629,21.772 ; C5.1@13.827,21.971 C5.1@13.629,21.772 ; 14.183,22.09 14.183,24.561 14.302,24.68 XDS1.69@15.009,24.68 ; XDS1.90@15.607,16.28 16.308,16.28 16.577,16.55 18.05,16.55 18.707,15.892 XDS1.101@18.707,12.38 18.707,11.447 19.459,10.696 19.459,10.328 C9.1@19.637,10.149 ; C7.1@20.942,29.482 21.14,29.283 21.798,29.283 21.917,29.164 21.917,27.79 XDS1.52@21.919,27.788 ; XDS1.47@23.907,27.78 23.907,29.287 C6.1@23.957,29.336 ; C4.1@27.519,10.149 C4.1@27.519,10.249 ; XDS1.8@30.317,16.69 31.017,16.69 XDS1.8@31.019,16.688 ; XDS1.16@30.317,19.886 31.613,19.886 31.617,19.89 32.336,19.89 32.489,20.043 32.489,25.743 ; R4.2@30.418,30.392 R4.2@30.545,30.519 ; XDS1.7@31.017,16.286 XDS1.7@31.019,16.288 ; XDS1.26@31.019,23.888 31.615,23.888 31.617,23.89 32.489,23.89 ; v3(33.061,16.016) 33.061,16.062 33.544,16.545 C13.1@33.644,16.545 ; C14.1@33.456,26.709 C14.1@33.556,26.709 ; R11.2@33.568,31.452 R10.2@33.568,29.919 R9.2@33.568,28.386 R9.2@33.668,28.386
  Top Layer w0.508: R8.1@18.011,8.949 18.011,9.049 18.057,9.095 18.509,9.095 ; C9.1@19.637,10.049 C9.1@19.637,10.149
  Bottom Layer w0.203: TP7.1@33.036,15.153 33.048,15.165 33.048,16.004 v3(33.061,16.016)
pads on no net: FID1.1 FID2.1 FID3.1 H1.0 H2.0 H3.0 H4.0 IC2.2 IC2.3 IC2.6 IC2.7 IC3.2 IC3.4 IC3.5 J21.1 J21.4 J21.9 J21.MH LBL1.0 Q4.9@122.326,39.218 Q4.9@122.326,40.548 Q4.9@122.326,41.878 Q4.9@123.341,40.548 Q4.9@123.476,39.218 Q4.9@123.476,40.548 Q4.9@123.476,41.878 Q4.9@124.626,39.218 Q4.9@124.626,40.548 Q4.9@124.626,41.878 Q4.9@124.921,38.176 Q4.9@124.921,42.921 Q7.9@100.233,29.498 Q7.9@100.233,31.278 Q7.9@101.683,29.498 Q7.9@101.683,30.428 Q7.9@101.683,31.278 Q7.9@103.133,29.498 Q7.9@103.133,31.278 Q8.9@90.014,29.046 Q8.9@90.014,33.791 Q8.9@90.309,30.088 Q8.9@90.309,31.418 Q8.9@90.309,32.748 Q8.9@91.459,30.088 Q8.9@91.459,31.418 Q8.9@91.459,32.748 Q8.9@91.594,31.418 Q8.9@92.609,30.088 Q8.9@92.609,31.418 Q8.9@92.609,32.748 SH-J1.0 SH-J2.0 SH-J3.0 SH-J4.0 SH-J5.0 SH-J6.0 SH-J7.0 SH-J8.0 SH-J9.0 SH-J10.0 SH-J14.0 SH-J15.0 SH-J16.0 SH-J17.0 SH-J18.0 SH-J19.0 SH-J20.0 SH-J21.0 U1.2 U1.7 U1.11 U1.15 U1.18 U1.25 U1.28 U1.31 U1.33 U1.34 U1.36 U1.42 U1.44 U1.47 U1.49 U1.55 U1.62 U1.63 U1.64 U2.2 U2.3 U2.19 U2.20 U2.28 U2.29 U2.30 U3.3 U3.11 U3.12 XDS1.2 XDS1.5 XDS1.6 XDS1.11 XDS1.12 XDS1.13 XDS1.14 XDS1.15 XDS1.18 XDS1.19 XDS1.20 XDS1.21 XDS1.22 XDS1.23 XDS1.24 XDS1.25 XDS1.27 XDS1.29 XDS1.30 XDS1.31 XDS1.32 XDS1.41 XDS1.43 XDS1.44 XDS1.45 XDS1.46 XDS1.49 XDS1.50 XDS1.53 XDS1.54 XDS1.56 XDS1.57 XDS1.65 XDS1.67 XDS1.71 XDS1.72 XDS1.73 XDS1.74 XDS1.75 XDS1.76 XDS1.77 XDS1.78 XDS1.81 XDS1.82 XDS1.83 XDS1.84 XDS1.85 XDS1.86 XDS1.91 XDS1.92 XDS1.102 XDS1.103 XDS1.104 XDS1.105 XDS1.106 XDS1.107 XDS1.108 XDS1.109 XDS1.110 XDS1.111 XDS1.112 XDS1.116 XDS1.117 XDS1.118 XDS1.119 XDS1.121 XDS1.123 XDS1.124 XDS1.125 XDS1.126 XDS1.127 XDS1.128
copper on no net: | length 0.8
  Bottom Layer w0.152: 89.569,22.277 89.802,22.044 89.887,22.044 ; 89.578,22.684 89.812,22.917 89.896,22.917
  other v2: 74.562,45.601
  other v3: 16.754,14.111 16.729,15.864 6.645,19.445 6.645,21.503

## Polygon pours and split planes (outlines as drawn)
GND on Top Layer "TOP_LAYER_GND_P485" (solid, remove dead copper, pour order 485): 0,101.6 0,0 152.4,0 152.4,101.6
DVDD on Top Layer "TOP_LAYER_DVDD_P482" (solid, remove dead copper, pour order 482): 91.804,43.39 91.804,41.881 90.363,41.881 90.255,41.989 90.255,44.543 91.764,46.052 92.583,46.052 92.583,44.169
SH_HS on Top Layer "TOP_LAYER_SH_HS_P484" (solid, remove dead copper, pour order 484): 99.485,27.771 102.65,27.771 102.728,27.693 102.728,7.112 89.859,7.112 89.601,7.37 89.601,10.414 96.774,10.414 98.945,12.585 98.945,27.757
ECFB on Top Layer "TOP_LAYER_ECFB_P481" (solid, remove dead copper, pour order 481): 74.673,11.676 73.51,10.513 67.056,10.513 67.056,7.112 79.248,7.112 79.248,23.368 85.945,30.065 88.627,30.065 88.627,33.68 83.019,33.68 74.673,25.334
NetJ23_2 on Top Layer "TOP_LAYER_NETJ23_2_P479" (solid, remove dead copper, pour order 479): 89.721,34.351 89.769,34.4 98.27,34.4 98.27,33.061 98.302,33.03 97.619,32.347 95.445,32.347 94.56,31.462 94.56,28.686 89.521,28.686 89.601,28.766 89.601,34.271
OUT5 on Top Layer "TOP_LAYER_OUT5_P456" (solid, remove dead copper, pour order 456): 93.694,51.675 94.079,51.29 94.079,53.505 92.816,54.767 91.284,54.767 91.141,54.91 91.141,91.141 92.461,92.461 92.461,93.721 91.707,94.475 84.22,94.475 84.125,94.38 84.125,91.973 86.659,91.973 86.754,92.069 87.757,91.066 87.757,56.343 90.594,53.506 91.643,53.506 91.863,53.506
OUT1 on Top Layer "TOP_LAYER_OUT1_P455" (solid, remove dead copper, pour order 455): 93.123,52.679 92.426,53.375 90.503,53.375 71.284,72.593 71.227,91.116 72.178,92.069 77.437,92.069 77.378,92.128 77.378,94.426 68.627,94.426 68.199,93.998 68.199,73.039 89.115,52.123 92.733,52.123 92.733,51.057 93.123,51.057
PVDD on Top Layer "TOP_LAYER_PVDD_P053" (solid, remove dead copper, pour order 459): 99.076,33.53 97.399,31.853 95.958,31.853 95.958,30.139 95.945,30.127 97.85,28.222 113.671,28.222 113.671,20.586 120.375,20.586 120.375,27.078 120.389,27.092 120.389,35.464 120.375,36.905 120.375,44.289 102.752,61.911 94.344,61.911 94.262,61.911 94.262,51.605 94.298,51.569 96.299,51.569 96.299,51.093 96.309,51.083 96.323,51.097 96.822,51.097 96.822,51.827 97.109,52.114 98.396,52.114 99.225,52.943 100.237,52.943 102.205,54.911 102.829,55.535 103.472,55.535 104.503,54.504 104.503,52.193 102.34,50.03 97.256,50.03 97.256,47.855 103.995,47.855 108.419,43.456 108.419,33.53
OUT3 on Top Layer "TOP_LAYER_OUT3_P445" (solid, remove dead copper, pour order 445): 101.01,53.43 103.069,55.49 104.054,54.504 104.054,54.283 104.027,54.283 103.321,53.578 100.233,50.49 97.36,50.49 97.355,51.488 100.299,51.488 101.01,52.198
OUT4 on Top Layer "TOP_LAYER_OUT4_P139" (solid, remove dead copper, pour order 443): 100.527,53.041 101.047,52.522 100.834,52.309 100.055,51.53 98.477,51.538 98.065,51.126 96.843,51.126 96.843,51.827 96.9,51.884 97.527,51.884 97.756,52.114 97.894,52.114 98.82,53.041
OUT7 on Top Layer "TOP_LAYER_OUT7_P475" (solid, remove dead copper, pour order 475): 132.361,86.487 148.209,86.487 148.463,86.233 148.463,83.533 136.722,83.533 135.051,85.205 132.385,85.205
OUT12 on Top Layer "TOP_LAYER_OUT12_P472" (solid, remove dead copper, pour order 472): 132.226,55.727 148.529,55.727 148.775,55.48 148.775,52.995 137.049,52.995 135.911,54.133 135.911,54.177 132.183,54.177
OUT11 on Top Layer "OUT11" (solid, remove dead copper, pour order 468): 148.895,60.952 148.819,60.876 148.819,58.287 138.877,58.287 136.749,58.287 135.591,59.444 131.972,59.444 131.972,60.952
OUT10 on Top Layer "TOP_LAYER_OUT10_P466" (solid, remove dead copper, pour order 466): 138.674,68.516 148.777,68.516 148.777,65.904 148.819,65.862 148.493,65.537 137.607,65.537 137.461,65.545 131.976,65.545 131.972,67.099 135.84,67.099 135.891,67.048 137.36,68.516
OUT9 on Top Layer "OUT9" (solid, remove dead copper, pour order 464): 148.659,73.464 148.463,73.703 132.196,73.703 132.171,71.821 135.424,71.821 136.462,70.783 138.133,70.783 148.659,70.783
OUT8 on Top Layer "TOP_LAYER_OUT8_P462" (solid, remove dead copper, pour order 462): 148.074,78.638 148.361,78.926 148.354,79.019 148.354,81.407 132.358,81.407 132.269,79.966 135.09,79.966 136.253,78.803 136.253,78.638
OUT6 on Top Layer "TOP_LAYER_OUT6_P444" (solid, remove dead copper, pour order 444): 100.609,50.364 104.235,53.99 104.235,50.636 103.376,49.777 97.358,49.777 97.358,49.897 97.825,50.364
OUT8 on Top Layer "TOP_LAYER_OUT8_P435" (solid, remove dead copper, pour order 435): 98.579,47.826 98.695,47.942 102.946,47.942 102.946,47.347 99.059,47.347
OUT11 on Top Layer "TOP_LAYER_OUT11_P439" (solid, remove dead copper, pour order 439): 98.289,46.239 98.533,46.239 98.784,46.489 99.911,45.362 106.167,45.362 106.167,44.802 99.725,44.802
OUT12 on Top Layer "TOP_LAYER_OUT12_P440" (solid, remove dead copper, pour order 440): 98.136,45.718 98.909,45.718 100.395,44.232 106.925,44.232 106.925,43.747 100.107,43.747
OUT10 on Top Layer "TOP_LAYER_OUT10_P436" (solid, remove dead copper, pour order 436): 98.238,46.947 98.376,47.086 98.376,47.347 99.484,46.239 105.231,46.239 105.231,45.726 99.46,45.726
OUT9 on Top Layer "TOP_LAYER_OUT9_P433" (solid, remove dead copper, pour order 433): 98.324,47.499 98.324,47.521 98.55,47.748 99.262,47.017 103.973,47.017 103.973,46.559 99.264,46.559
OUT2 on Top Layer "TOP_LAYER_OUT2_P454" (solid, remove dead copper, pour order 454): 63.652,94.475 64.607,93.52 64.607,76.515 86.172,54.656 86.371,54.457 88.813,52.015 92.733,52.015 92.733,51.104 87.047,51.104 68.53,69.621 62,76.314 62,90.995 60.73,92.266 56.828,92.266 56.515,92.578 56.515,94.463 61.987,94.463 62,94.475
SHIELD_GND on Top Layer "TOP_LAYER_SHIELD_GND_P453" (solid, remove dead copper, pour order 453): 28.534,95.301 41.224,95.301 41.224,100.815 28.534,100.815
NetC82_2 on Top Layer "TOP_LAYER_NETC82_2_P432" (solid, remove dead copper, pour order 432): 22.645,79.726 22.906,79.465 22.906,78.921 23.906,78.921 23.906,79.471 24.05,79.615 24.05,80.625 22.645,80.625
VCC2 on Top Layer "TOP_LAYER_VCC2_P449" (solid, remove dead copper, pour order 449): 23.953,68.05 23.953,69.364 25.662,69.364 26.506,70.208 26.506,71.931 27.194,71.931 27.891,72.628 27.891,74.809 29.178,74.809 29.345,74.642 29.345,72.941 28.035,71.631 27.931,71.631 27.931,69.277 27.568,68.914 24.797,68.914 24.797,68.05
VCC1 on Top Layer "TOP_LAYER_VCC1_P434" (solid, remove dead copper, pour order 434): 22.308,61.568 22.308,63.124 23.37,63.124 23.37,63.936 23.744,63.936 23.744,63.132 24.519,62.357 24.519,61.568
PVDD on Top Layer "TOP_LAYER_PVDD_P437" (solid, remove dead copper, pour order 437): 18.877,59.355 18.769,59.247 18.769,56.829 20.052,56.829 20.291,57.067 20.291,58.828 20.926,59.463 20.926,61.311 19.486,61.311 18.868,60.693 18.868,59.364
VSUP on Top Layer "TOP_LAYER_VSUP_P447" (solid, remove dead copper, pour order 447): 17.837,60.89 17.837,62.89 19,62.89 19.441,63.332 19.441,64.343 21.27,64.343 21.27,64.111 21.479,63.903 22.297,63.903 22.297,62.052 21.884,61.639 19.617,61.639 18.868,60.89
no net on Top Layer "TOP_LAYER_NONET_P450" (solid, remove dead copper, pour order 450): 14.274,37.249 14.417,37.392 14.417,40.937 12.229,40.937 11.507,40.214 11.507,37.249
3V3_MCU on Top Layer "TOP_LAYER_3V3_MCU_P448" (solid, remove dead copper, pour order 448): 7.725,39.221 7.703,39.243 7.703,43.211 10.231,43.211 10.27,43.171 10.259,43.161 10.259,40.295 9.186,39.221 7.708,39.221
3V3_MCU on Top Layer "TOP_LAYER_3V3_MCU_P441" (solid, remove dead copper, pour order 441): 2.692,53.064 3.242,53.614 3.242,55.318 0.961,55.318 0.961,53.064
3V3_MCU on Top Layer "TOP_LAYER_3V3_MCU_P451" (solid, remove dead copper, pour order 451): 9.398,58.229 9.398,62.789 12.681,62.789 12.673,62.781 12.673,58.917 12.646,58.917 11.958,58.229
NetQ1_3 on Top Layer "TOP_LAYER_NETQ1_3_P442" (solid, remove dead copper, pour order 442): 128.075,44.526 127.502,43.952 127.502,43.207 127.502,41.878 126.152,41.878 126.152,43.181 126.126,43.207 126.126,45.101 128.249,45.101 128.249,44.526
NetQ1_1 on Top Layer "TOP_LAYER_NETQ1_1_P438" (solid, remove dead copper, pour order 438): 130.131,42.944 129.549,43.526 129.549,44.184 131.826,44.184 131.826,41.727 130.131,41.727
NetD5_2 on Top Layer "TOP_LAYER_NETD5_2_P446" (solid, remove dead copper, pour order 446): 127.761,42.997 127.761,44.002 129.013,45.254 129.013,46.197 131.351,46.197 131.351,44.314 130.1,44.314 129.865,44.048 129.865,41.727 127.727,41.727 127.727,42.997
PI_IN on Top Layer "TOP_LAYER_PI_IN_P457" (solid, remove dead copper, pour order 457): 120.808,38.097 122.047,36.858 122.047,25.039 120.788,23.78 120.788,20.586 127.938,20.586 127.938,37.344 125.315,37.344 125.315,45.151 120.808,45.151
NetD5_1 on Top Layer "TOP_LAYER_NETD5_1_P452" (solid, remove dead copper, pour order 452): 126.126,41.504 133.604,41.504 133.604,37.558 126.126,37.558
VBAT on Top Layer "TOP_LAYER_VBAT_P458" (solid, remove dead copper, pour order 458): 142.584,18.796 128.413,18.796 128.413,32.258 151.982,32.258 151.982,18.796
XDS_VCC on Top Layer "TOP_LAYER_XDS_VCC_P460" (solid, remove dead copper, pour order 460): 8.504,2.889 9.526,1.945 10.085,1.945 33.378,1.945 34.8,3.367 34.8,8.487 38.242,8.487 39.32,9.565 39.218,9.666 39.218,32.399 8.504,32.399
3V3_MCU on Mid-Layer 2 "MID-LAYER_2_3V3_MCU_P480" (solid, remove dead copper, pour order 480): 48.172,33.25 47.909,32.986 47.909,24.529 42.112,24.529 42.086,24.503 42.086,26.652 42.119,26.652 42.934,27.467 45.759,27.467 45.759,33.214 45.723,33.25 3.651,33.25 0.623,36.278 0.623,60.262 4.279,63.918 12.689,63.918 12.673,63.903 12.673,58.917 14.346,57.258 14.346,36.63 35.676,36.63 43.708,36.63 45.568,38.49 45.568,42.314 47.908,42.314 48.172,42.05
OUT8 on Mid-Layer 2 "MID-LAYER_2_NONET_P152" (solid, remove dead copper, pour order 470): 99.477,47.926 99.477,47.403 104.898,47.403 129.54,72.045 129.54,79.756 129.794,80.01 135.763,80.01 137.16,78.613 148.354,78.613 148.354,81.407 132.358,81.407 132.334,81.383 129.643,81.383 128.778,80.518 128.778,72.146 104.558,47.926
PVDD on Mid-Layer 2 "MID-LAYER_2_PVDD_P463" (solid, remove dead copper, pour order 463): 94.833,61.971 95.315,61.971 95.315,62.453 95.319,62.458 91.714,66.062 91.563,66.062 86.345,71.281 48.388,71.281 40.154,63.047 40.154,60.904 39.735,60.485 26.343,60.485 24.776,58.917 18.868,58.917 18.868,60.631 18.962,60.631 19.641,61.311 20.727,61.311 20.727,60.585 20.926,60.387 20.926,59.409 24.446,59.409 26.012,60.975 39.268,60.975 39.483,61.189 39.483,63.272 48.104,71.894 87.056,71.894 93.195,65.755 97.038,61.911 97.038,60.001 94.581,60.001 94.581,61.719
OUT12 on Mid-Layer 2 "MID-LAYER_2_OUT12_P465" (solid, remove dead copper, pour order 465): 101.409,44.251 101.409,43.747 106.832,43.747 116.2,53.114 148.68,53.114 148.68,55.989 132.246,55.989 130.513,54.256 116.528,54.256 106.52,44.249 106.519,44.251
OUT11 on Mid-Layer 2 "MID-LAYER_2_OUT11_P473" (solid, remove dead copper, pour order 473): 98.142,37.124 98.142,34.965 95.88,34.965 95.88,38.757 96.626,39.503 99.399,39.503 99.399,45.248 99.539,45.387 106.142,45.387 121.715,60.96 148.354,60.96 148.354,58.438 148.336,58.42 136.969,58.42 135.774,59.615 121.23,59.615 106.527,44.913 106.414,44.802 100.294,44.802 100.294,39.276
OUT10 on Mid-Layer 2 "MID-LAYER_2_OUT10_P154" (solid, remove dead copper, pour order 469): 136.969,68.58 135.536,67.147 135.536,67.056 126.36,67.048 105.551,46.239 99.484,46.239 99.46,45.726 105.869,45.726 125.675,65.531 125.674,65.532 148.336,65.532 148.336,68.58
OUT9 on Mid-Layer 2 "MID-LAYER_2_OUT9_P467" (solid, remove dead copper, pour order 467): 99.399,46.927 99.419,46.946 104.925,46.946 131.639,73.66 148.463,73.66 148.463,70.612 136.969,70.612 135.536,72.045 130.874,72.045 105.388,46.559 99.451,46.559
OUT7 on Mid-Layer 2 "MID-LAYER_2_OUT7_P471" (solid, remove dead copper, pour order 471): 99.298,48.016 100.269,48.987 104.544,48.987 128.143,72.586 128.143,80.772 131.128,83.757 148.209,83.757 148.209,86.487 132.334,86.487 127.254,81.407 127.254,72.771 103.973,49.49 103.973,49.402 99.685,49.402 98.856,48.573 98.856,48.016
OUT6 on Mid-Layer 2 "MID-LAYER_2_OUT6_P477" (solid, remove dead copper, pour order 477): 98.2,49.778 98.2,50.364 100.585,50.364 123.952,73.731 123.952,94.546 133.604,94.546 133.604,91.904 127.889,91.904 126.492,90.507 126.492,72.89 103.273,49.671 98.216,49.671
OUT4 on Mid-Layer 2 "MID-LAYER_2_OUT4_P476" (solid, remove dead copper, pour order 476): 100.016,51.439 101.073,52.495 101.073,52.526 100.084,53.514 100.072,53.712 100.072,91.618 104.708,91.618 105.562,92.472 105.562,94.844 95.86,94.844 95.86,91.904 97.237,90.526 97.237,51.855 96.871,51.855 96.843,51.827 96.95,51.72 96.95,51.439
OUT3 on Mid-Layer 2 "MID-LAYER_2_OUT3_P474" (solid, remove dead copper, pour order 474): 119.05,72.773 100.922,54.645 100.922,51.976 100.072,51.126 100.039,51.159 97.436,51.159 97.436,50.677 97.463,50.65 100.502,50.65 102.445,52.593 121.59,71.738 121.59,94.539 112.37,94.539 112.37,92.862 113.328,91.904 118.415,91.904 119.05,91.269
SHIELD_GND on Mid-Layer 2 "MID-LAYER_2_SHIELD_GND_P478" (solid, remove dead copper, pour order 478): 7.956,95.301 39.452,95.301 39.452,100.815 7.956,100.815
GND on Mid-Layer 2 "MID-LAYER_2_GND_P483" (solid, remove dead copper, pour order 483): 0.173,0.046 0.173,101.646 152.573,101.646 152.573,0.046
OUT3 on Bottom Layer "BOTTOM_LAYER_OUT3_P488" (solid, remove dead copper, pour order 488): 111.86,96.535 111.896,92.114 113.296,91.305 115.329,91.388 115.329,96.535
OUT6 on Bottom Layer "BOTTOM_LAYER_OUT6_P487" (solid, remove dead copper, pour order 487): 124.424,89.615 127.067,89.615 127.067,94.485 124.715,94.485 124.424,94.194
GND on Bottom Layer "BOTTOM_LAYER_GND_P489" (solid, remove dead copper, pour order 489): 0,101.298 152.098,101.298 152.4,101.6 152.4,0 0,0
OUT4 on Bottom Layer "BOTTOM_LAYER_OUT4_P486" (solid, remove dead copper, pour order 486): 95.783,94.853 95.751,92.384 96.26,92.149 99.121,92.149 99.121,96.187 95.752,96.187
GND on Mid-Layer 1 "MID-LAYER_1_GND_P461" (solid, remove dead copper, pour order 461): 0,0 0,101.6 152.4,101.6 152.202,101.402 152.4,101.204 152.4,0

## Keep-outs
Keep-Out Layer:
  lines w0.508: 0,0 0,15.58 0,23.855 0,91.1 0,101.6 152.4,101.6 152.4,0 0,0
  text ".Layer_Name" at 14.316,-21.806 h1.52

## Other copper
Top Layer:
  region net XDS_VCC: 29.073,19.801 29.657,19.801 30.851,19.801 30.851,19.953 30.826,19.979 29.073,19.979
  region net XDS_VCC: 31.004,24.576 29.073,24.576 29.073,24.779 31.004,24.779
  region net XDS_VCC: 31.004,23.789 29.073,23.789 29.073,23.992 29.124,23.992 31.004,23.992
  region net XDS_VCC: 29.073,16.194 29.632,16.194 32.35,16.194 32.35,16.88 32.35,16.778 32.197,16.778 29.073,16.778
  pour cut-out: 12.499,9.358 16.876,9.358 16.876,13.852 12.499,13.852
  region net XDS_VCC: 27.194,10.886 27.016,10.886 27.016,14.949 27.088,14.949 27.194,14.949 27.194,12.467
  pour cut-out: 29.505,11.241 18.812,11.241 18.812,13.349 18.989,13.527 29.48,13.527 29.505,13.502
  pour cut-out: 16.754,15.915 16.754,23.89 14.468,23.89 14.468,16.245 14.798,15.915
  pour cut-out: 30.318,13.832 32.098,13.832 32.173,13.908 32.172,13.909 32.172,26.634 31.994,26.811 30.191,26.811 29.845,26.466 29.845,14.152
  region net XDS_VCC: 23.612,11.976 23.612,14.01 23.409,14.01 23.409,11.976
  region net XDS_VCC: 15.535,20.588 15.535,20.792 18.151,20.792 18.151,20.614 18.151,20.588
  pour cut-out: 10.504,16.792 11.891,16.792 11.677,17.006 11.677,17.186 10.504,17.186
  region net XDS_VCC: 23.815,27.853 23.815,25.44 23.993,25.44 23.993,27.853
  region net XDS_VCC: 27.016,27.853 27.016,25.287 27.194,25.287 27.194,27.853
  region net XDS_VCC: 21.809,25.44 22.418,25.44 22.418,29.631 21.809,29.631
  pour cut-out: 30.038,28.386 30.038,26.946 29.691,26.634 20.945,26.634 20.945,28.97 29.708,28.97
  text ".Layer_Name" at 14.316,-21.806 h1.52
Mid-Layer 1:
  pour cut-out: 10.252,13.832 10.252,20.106 13.681,20.106 13.681,18.805 14.69,18.805 14.9,18.594 14.9,15.407 14.671,15.178 13.681,15.178 13.681,13.832
Mid-Layer 2:
  pour cut-out: 10.252,13.832 13.655,13.832 13.681,13.857 13.681,15.178 14.671,15.178 14.9,15.407 14.9,18.594 14.69,18.805 13.681,18.805 13.681,20.106 10.252,20.106
Bottom Layer:
  text ".Layer_Name" at 14.316,-21.806 h1.52

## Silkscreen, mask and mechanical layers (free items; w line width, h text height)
Top Overlay:
  drawing of 1237 lines, arcs and shapes, not listed
  text "HIGH / SIDE DRIVERS" at 134.708,90.745 h2.29
  text "OUT7" at 135.753,86.978 h2.54
  text "CANL" at 22.111,85.814 h0.76 r90
  text "CANH" at 25.51,85.814 h0.76 r90
  text "VCC2" at 39.182,84.05 h0.76
  text "VCC1" at 43.325,84.05 h0.76
  text "LIN" at 19.639,83.06 h0.76 r90
  text "8" at 139.372,81.138 h2.54
  text "HSS4" at 5.411,73.88 h0.76
  text "9" at 139.394,73.432 h2.54
  text "OUT5" at 93.748,73.135 h5.08 r90
  text "OUT4" at 99.818,73.135 h5.08 r90
  text "OUT2" at 65.122,73.096 h5.08 r90
  text "OUT1" at 72.178,72.967 h5.08 r90
  text "OUT3" at 121.705,72.617 h5.08 r90
  text "OUT6" at 128.604,72.617 h5.08 r90
  text "DRV8001-Q1" at 49.886,72.466 h2.03
  text "M0" at 37.341,71.845 h2.03
  text "HSS3" at 5.487,71.43 h0.76
  text "HSS2" at 5.564,69.092 h0.76
  text "HALF-BRIDGE DRIVERS" at 83.366,67.286 h2.29
  text "HSS1" at 5.64,66.635 h0.76
  text "10" at 138.182,63.17 h2.54
  text "1" at 1.092,62.746 h0.76
  text "2" at 3.99,62.746 h0.76
  text "3" at 6.537,62.746 h0.76
  text "PWM2" at 57.17,62.154 h3.05
  text "Read  / User Guide / before use" at 118.378,61.473 h0.76
  text "WAKE" at 1.494,58.625 h0.76
  text "PWM1" at 57.128,58.1 h3.05
  text "11" at 138.262,55.72 h2.54
  text "nSCS" at 56.947,54.19 h3.05
  text "IPROPI" at 73.614,52.373 h2.54
  text "SDI" at 56.992,50.035 h3.05
  text "OUT12" at 134.636,49.836 h2.54
  text "Caution / Hot Surface" at 105.185,47.535 h0.76
  text "SDO" at 58.191,45.999 h3.05
  text "GND" at 138.182,45.79 h3.3
  text "MCU_STATUS" at 9.151,45.703 h0.51
  text "IPROPI" at 38.918,45.57 h2.03
  text "nFAULT" at 9.12,43.363 h0.51
  text "PVDD" at 114.219,42.883 h0.76
  text "SCLK" at 57.224,41.872 h3.05
  text "3V3" at 8.897,40.774 h0.51
  text "ECDRV" at 91.254,39.686 h1.27
  text "GH_HS" at 103.369,38.828 h1.27
  text "nSLEEP" at 57.128,37.911 h3.05
  text "NRST" at 34.756,36.097 h2.03 r90
  text "SWDIO" at 36.799,36.097 h2.03 r90
  text "SWCLK" at 38.957,36.097 h2.03 r90
  text "RXD>>" at 15.833,35.828 h2.03 r90
  text "TXD <<" at 19.575,35.778 h2.03 r90
  text "GUI_STATUS" at 0.775,34.983 h0.51
  text "Target" at 28.359,33.639 h1.14
  text "Debugger" at 27.93,31.452 h1.14
  text "3V3" at 39.594,24.235 h2.03
  text "PB2" at 39.628,21.88 h2.03
  text "PB3" at 39.692,19.257 h2.03
  text "HEATER" at 98.272,17.693 h3.3
  text "EC" at 77.47,16.764 h3.3
  text "PA30" at 38.781,16.69 h2.03
  text "VBAT" at 135.452,14.376 h5.08
  text "PA31" at 38.781,14.351 h2.03
  text "MIRROR" at 74.541,13.462 h3.3
  text "4.5 V -35 V DC" at 133.278,11.952 h2.54
  text "PB20" at 38.781,11.663 h2.03
  text "PB24" at 38.781,9.026 h2.03
  text "MD085.PCB_Rev" at 124.363,5.08 h2.75
  text ".Layer_Name" at 14.316,-21.806 h1.52
Bottom Overlay:
  text "Caution / Hot Surface" at 110.459,47.577 h0.76
  text "GND" at 20.31,14.01 h1.27 r90
  text "ITMS" at 22.495,14.01 h1.27 r90
  text "ITCK" at 24.679,14.01 h1.27 r90
  text "ITDO" at 26.889,14.01 h1.27 r90
  text "ITDI" at 29.073,14.01 h1.27 r90
  text "IRSTN" at 31.308,14.01 h1.27 r90
  text "XDS_VCC" at 33.671,14.01 h1.27 r90
  text ".Layer_Name" at 14.316,-21.806 h1.52
Top Paste:
  text ".Layer_Name" at 14.316,-21.806 h1.52
Bottom Paste:
  text ".Layer_Name" at 14.316,-21.806 h1.52
Top Solder:
  text ".Layer_Name" at 14.316,-21.806 h1.52
  text ".Layer_Name" at 14.316,-21.806 h1.52
Bottom Solder:
  text ".Layer_Name" at 14.316,-21.806 h1.52
Drill Guide:
  text ".Layer_Name" at 14.316,-21.806 h1.52
M1 Board Outline:
  lines w0.254: 0,17.163 0,15.58 0,2.032 ccw(c2,2.032) 2,0.032 150.4,0 ccw(c150.4,2) 152.4,2 152.4,99.6 ccw(c150.4,99.6) 150.4,101.6 133.265,101.6 44.195,101.6 2.471,101.639 ccw(c2.471,99.168) 0,99.168 0,91.1 0,23.855
  text ".Layer_Name" at 14.316,-21.806 h1.52
M2 Board Dimensions:
  rectangle: -0.34,-6.985 2.835,-3.81
  rectangle: 2.835,-10.16 12.36,-6.985
  lines w0.178: -0.34,-6.985 25.06,-6.985 ; 2.835,-10.16 2.835,-3.81 ; 6.01,-10.16 6.01,-3.81 ; 12.36,-10.16 12.36,-3.81 ; 18.71,-10.16 18.71,-3.81 ; -0.34,-10.16 25.06,-10.16 25.06,-3.81 -0.34,-3.81 -0.34,-10.16
  text ".Layer_Name" at 14.316,-21.806 h1.52
M3 3D STEP Top:
  text ".Layer_Name" at 14.316,-21.806 h1.52
M4 3D STEP Bottom:
  text ".Layer_Name" at 14.316,-21.806 h1.52
M5 Assembly Top:
  lines w0.254: -7.757,-23.626 159.883,-23.626 ; -7.757,-18.462 159.934,-18.462 ; -7.757,-13.297 -7.757,-28.791 93.97,-28.791 159.934,-28.791 159.934,-13.297 -7.744,-13.297 -7.744,-28.791 32.274,-28.791 ; 54.854,-28.791 54.854,-13.297 ; 87.036,-18.462 87.036,-13.297 ; 108.372,-18.462 108.372,-13.297 ; 124.171,-28.956 124.171,-23.804
  text "COMPONENTS MARKED 'DNP' SHOULD NOT BE POPULATED." at 28.959,-8.09 h1.52
  text "ASSEMBLY VARIANT:" at 28.946,-11.024 h1.52
  text ".VariantName" at 55.261,-11.024 h1.52
  text "PCB VIEWED FROM TOP SIDE" at -6.144,-16.654 h1.52
  text "BOARD #:" at 56.759,-16.654 h1.52
  text ".PRJ_Number" at 70.615,-16.654 h1.52
  text "REV:" at 92.065,-16.654 h1.52
  text ".PCB_Rev" at 99.469,-16.654 h1.52
  text "SVN REV:" at 113.35,-16.654 h1.52
  text ".VersionControl_RevNumber" at 126.203,-16.654 h1.52
  text "TID #:" at 56.759,-21.819 h1.52
  text ".TID" at 70.615,-21.819 h1.52
  text "PLOT NAME =" at -6.144,-27.034 h1.52
  text ".plot_File_Name" at 14.316,-27.034 h1.52
  text "GENERATED    :" at 56.81,-27.034 h1.52
  text ".Print_Date" at 78.895,-27.034 h1.52
  text ".Print_Time" at 97.412,-27.034 h1.52
  text "TEXAS INSTRUMENTS" at 129.53,-27.034 h1.52
M6 Assembly Bottom:
  lines w0.254: -7.769,-18.474 159.921,-18.474 ; -7.719,-23.639 159.921,-23.639 ; 27.994,-28.969 27.994,-23.817 ; 43.793,-18.474 43.793,-13.31 ; 65.129,-18.474 65.129,-13.31 ; 97.31,-28.804 97.31,-13.31 ; 119.891,-28.804 159.909,-28.804 159.909,-13.31 -7.769,-13.31 -7.769,-28.804 58.194,-28.804 159.921,-28.804 159.921,-13.31
  text "COMPONENTS MARKED 'DNP' SHOULD NOT BE POPULATED." at 154.651,-8.077 h1.52
  text ".VersionControl_RevNumber" at 268.402,-9.474 h1.52
  text ".VariantName" at 128.133,-11.024 h1.52
  text "ASSEMBLY VARIANT:" at 154.524,-11.024 h1.52
  text "SVN REV:" at 38.814,-16.667 h1.52
  text ".PCB_Rev" at 52.695,-16.667 h1.52
  text "REV:" at 60.099,-16.667 h1.52
  text ".PRJ_Number" at 81.55,-16.667 h1.52
  text "BOARD #:" at 95.405,-16.667 h1.52
  text "PCB VIEWED FROM BOTTOM SIDE" at 158.308,-16.667 h1.52
  text ".TID" at 81.55,-21.831 h1.52
  text "TID #:" at 95.405,-21.831 h1.52
  text "TEXAS INSTRUMENTS" at 22.634,-27.047 h1.52
  text ".Print_Time" at 54.753,-27.047 h1.52
  text ".Print_Date" at 73.269,-27.047 h1.52
  text "GENERATED    :" at 95.355,-27.047 h1.52
  text ".plot_File_Name" at 137.849,-27.047 h1.52
  text "PLOT NAME =" at 158.308,-27.047 h1.52
M9 Title Sheet:
  drawing of 57 lines, arcs and shapes, not listed
  text "1" at 18.452,204.127 h1.78
  text "2" at 81.842,204.127 h1.78
  text "3" at 145.071,204.127 h1.78
  text "4" at 208.74,204.127 h1.78
  text "5" at 272.215,204.127 h1.78
  text "6" at 335.842,204.127 h1.78
  text "A" at -10.919,175.095 h1.78
  text "A" at 365.001,175.095 h1.78
  text "B" at -10.919,114.643 h1.78
  text "B" at 365.001,114.643 h1.78
  text "C" at -10.919,54.318 h1.78
  text "C" at 365.001,54.318 h1.78
  text "PROJECT TITLE:" at 287.785,7.048 h1.14
  text ".PRJ_Title" at 289.055,3.662 h1.78
  text "DESIGNED FOR:" at 287.785,-0.597 h1.14
  text ".PRJ_Customer" at 289.055,-4.153 h1.78
  text "D" at -10.919,-5.88 h1.78
  text "D" at 365.001,-5.88 h1.78
  text "FILE NAME:" at 287.785,-8.217 h1.14
  text ".PCB_File_Name_No_Path" at 289.055,-11.265 h1.78
  text "Texas Instruments (TI) and/or its licensors do not warrant the accuracy or completeness of this specification" at 161.56,-15.376 h1.14
  text "ENGINEER:" at 287.785,-15.583 h1.14
  text "LAYOUT BY:" at 326.012,-15.583 h1.14
  text "or any information contained therein. TI and/or its licensors do not warrant that this design will meet" at 160.417,-18.237 h1.14
  text ".PRJ_Engineer" at 289.055,-19.52 h1.78
  text ".PCB_Layout" at 327.295,-19.52 h1.78
  text "the specifications, will be suitable for your application or fit for any particular purpose, or will operate in" at 160.417,-21.099 h1.14
  text ".Layer_Name" at 14.316,-21.806 h1.52
  text "ALTIUM DESIGNER VERSION:" at 326.012,-23.457 h1.14
  text "an implementation. TI and/or its licensors do not warrant that the design is production worthy. You should" at 160.417,-23.961 h1.14
  text "completely validate and test your design implementation to confirm the system functionality for your application." at 161.56,-26.822 h1.14
  text ".print_Scale" at 289.055,-26.843 h1.78
  text ".Application_BuildNumber" at 327.295,-26.843 h1.78
  text "1" at 18.452,-32.093 h1.78
  text "2" at 81.842,-32.093 h1.78
  text "3" at 145.071,-32.093 h1.78
  text "4" at 208.74,-32.093 h1.78
  text "5" at 272.215,-32.093 h1.78
  text "6" at 335.842,-32.093 h1.78
M10 Fab Notes:
  drawing of 189 lines, arcs and shapes, not listed
  text "DESIGN INFORMATION" at 314.163,161.447 h1.52
  text "MIN. TRACK WIDTH:" at 297.791,158.091 h1.52
  text "8" at 325.636,158.091 h1.52
  text "MIL" at 329.567,158.091 h1.52
  text "7.874" at 321.41,155 h1.52
  text "MIN. CLEARANCE:" at 297.791,154.938 h1.52
  text "MIL" at 329.567,154.938 h1.52
  text "MIN. VIA PAD SIZE:" at 297.791,151.785 h1.52
  text "24" at 324.874,151.785 h1.52
  text "MIL" at 329.567,151.785 h1.52
  text "0.05mm (2MIL)" at 315.444,148.486 h1.52
  text "MINIMUM ANNULAR RING" at 289.429,148.277 h1.52
  text "EXTERNAL" at 333.428,148.277 h1.52
  text "PER" at 294.509,145.48 h1.52
  text "IPC-D-275 CLASS 2 LEVEL C" at 300.097,145.48 h1.52
  text "MIL, HOLES" at 337.898,142.928 h1.52
  text "+/-" at 327.93,142.709 h1.52
  text "+/-" at 349.621,142.709 h1.52
  text "REGISTRATION TOLERANCES:" at 289.429,142.682 h1.52
  text "METAL" at 319.903,142.682 h1.52
  text "5" at 334.539,142.683 h1.52
  text "3" at 355.697,142.683 h1.52
  text "MIL" at 358.65,142.682 h1.52
  text "HOLE SIZE TOLERANCE (UNLESS OTHERWISE SPECIFIED):" at 289.429,140.185 h1.52
  text "+/-" at 349.621,140.112 h1.52
  text "3" at 355.697,140.085 h1.52
  text "MIL" at 358.65,140.085 h1.52
  text "MATERIAL:" at 287.53,136.589 h1.52
  text "FR-4 High Tg" at 312.586,133.324 h1.52
  text "X" at 308.917,133.122 h1.52
  text "FR-4" at 298.223,133.007 h1.52
  text "OTHER" at 336.018,133.007 h1.52
  text "62 MIL (1.6mm) +/-10%" at 306.354,129.374 h1.52
  text "X" at 303.303,129.312 h1.52
  text "THICKNESS:" at 289.429,129.165 h1.52
  text "OTHER" at 338.99,129.165 h1.52
  text "TOLERANCE:" at 289.429,125.652 h1.52
  text "X" at 310.974,125.652 h1.52
  text "ANSI IPC-6012 TYPE 3 CLASS 2" at 315.496,125.652 h1.52
  text "OTHER +/-" at 315.495,121.989 h1.52
  text "BOW & TWIST:" at 289.429,118.302 h1.52
  text "X" at 310.974,118.302 h1.52
  text "ANSI IPC-6012 TYPE 3 CLASS 2" at 315.496,118.302 h1.52
  text "OTHER +/-" at 315.495,114.576 h1.52
  text "DRILLING:" at 287.53,111.258 h1.52
  text "NC_DRILL FILES" at 332.259,108.586 h1.52
  text "REFERENCE:" at 289.429,108.486 h1.52
  text "X" at 306.123,108.484 h1.52
  text "AS SHOWN" at 310.644,108.486 h1.52
  text "X" at 329.008,108.486 h1.52
  text "OTHER" at 339.828,104.873 h1.52
  text "PTH COPPER THICKNESS:" at 289.421,104.783 h1.52
  text "X" at 318.357,104.783 h1.52
  text "20-30 um" at 321.608,104.783 h1.52
  text "BOARD FINISH:" at 287.53,101.034 h1.52
  text "SILKSCREEN:" at 291.473,98.237 h1.52
  text "X" at 315.8,98.237 h1.52
  text "TOP" at 318.772,98.237 h1.52
  text "X" at 328.754,98.237 h1.52
  text "BOTTOM" at 331.751,98.237 h1.52
  text "SILKSCREEN COLOR:" at 291.473,94.295 h1.52
  text "X" at 315.775,94.295 h1.52
  text "WHITE" at 318.772,94.295 h1.52
  text "OTHER" at 331.751,94.295 h1.52
  text "X" at 319.102,90.652 h1.52
  text "GREEN" at 322.099,90.652 h1.52
  text "OTHER" at 337.796,90.652 h1.52
  text "SOLDER RESIST COLOR:" at 291.473,90.477 h1.52
  text "X" at 319.102,86.734 h1.52
  text "MATTE" at 322.099,86.734 h1.52
  text "SEMI-GLOSS" at 337.785,86.717 h1.52
  text "IMMERSION GOLD (ENIG)" at 314.479,82.345 h1.52
  text "ENEPIG" at 348.453,82.162 h1.52
  text "SURFACE FINISH:" at 287.53,82.136 h1.52
  text "X" at 309.958,82.136 h1.52
  text "IMM. TIN/SILVER OR EQUIV" at 295.9,78.649 h1.52
  text "OTHER" at 332.259,78.549 h1.52
  text "ARRAY/PANEL:" at 287.53,74.602 h1.52
  text "CUT AND TRIM PER M1 BOARD OUTLINE" at 314.479,74.393 h1.52
  text "N.C. ROUTE" at 314.479,70.94 h1.52
  text "X" at 331.955,70.94 h1.52
  text "V. SCORE" at 336.476,70.94 h1.52
  text "CERTIFICATION:" at 287.53,67.66 h1.52
  text "MATERIALS AND WORKMANSHIP FOR ALL PCBS" at 305.945,67.66 h1.52
  text "TO MEET OR EXCEED THE REQUIREMENTS OF:" at 305.945,65.271 h1.52
  text "X" at 296.738,62.003 h1.52
  text "ANSI IPC-A-600F CLASS ->" at 299.989,62.003 h1.52
  text "X" at 341.848,62.003 h1.52
  text "2" at 344.642,62.003 h1.52
  text "1" at 336.641,61.965 h1.52
  text "3" at 353.633,61.965 h1.52
  text "X" at 317.362,58.252 h1.52
  text "RoHS" at 320.613,58.252 h1.52
  text "OTHER" at 336.981,58.252 h1.52
  text "PER ORDER" at 347.067,58.252 h1.52
  text "ALL BOARDS MUST MEET OR EXCEED UL94-V0 REQUIREMENTS." at 288.229,54.345 h1.52
  text "PCB MUST BEAR THE UL94V-0 UL REGISTERED MATERIAL ID NUMBER" at 288.229,51.397 h1.52
  text "ADDITIONAL REQUIREMENTS:" at 287.53,47.094 h1.52
  text "MICROSECTION:" at 289.429,44.373 h1.52
  text "YES" at 312.435,44.373 h1.52
  text "REQUIRED" at 334.317,40.707 h1.52
  text "BARE BOARD ELEC. TEST:" at 289.429,40.634 h1.52
  text "NONE" at 322.595,40.634 h1.52
  text "X" at 331.32,40.634 h1.52
  text "PER ORDER" at 349.353,40.634 h1.52
  text "XX MIL VIAS REQUIRE NON-CONDUCTIVE FILL AND PLANARIZE" at 293.7,35.428 h1.5
  text "XX MIL VIAS REQUIRE CONDUCTIVE FILL AND PLANARIZE" at 293.903,32.787 h1.52
  text "OUTER XX MIL TRACES REQUIRE 50 OHM SINGLE-ENDED IMPEDANCE" at 293.878,28.637 h1.47
  text "LAYER 2 & 3 (INNER LAYERS) XX MIL WIDE, XX MIL SPACE / TRACES REQUIRE 100 OHM DIFFERENTIAL IMPEDANCE" at 293.675,22.65 h1.52
  text ".Layer_Name" at 14.316,-21.806 h1.52
M11 Gerber Information:
  lines w0.254: -7.757,-23.626 159.883,-23.626 ; -7.757,-18.462 159.934,-18.462 ; -7.757,-13.297 -7.757,-28.791 93.97,-28.791 159.934,-28.791 159.934,-13.297 -7.744,-13.297 -7.744,-28.791 32.274,-28.791 ; 54.854,-28.791 54.854,-13.297 ; 87.036,-18.462 87.036,-13.297 ; 108.372,-18.462 108.372,-13.297 ; 124.171,-28.956 124.171,-23.804
  text "ALL ARTWORK VIEWED FROM TOP SIDE" at -6.144,-16.654 h1.52
  text "BOARD #:" at 56.759,-16.654 h1.52
  text ".PRJ_Number" at 70.615,-16.654 h1.52
  text "REV:" at 92.065,-16.654 h1.52
  text ".PCB_Rev" at 99.469,-16.654 h1.52
  text "SVN REV:" at 113.35,-16.654 h1.52
  text ".VersionControl_RevNumber" at 126.203,-16.654 h1.52
  text "LAYER NAME =" at -6.144,-21.806 h1.52
  text "TID #:" at 56.759,-21.819 h1.52
  text ".TID" at 70.615,-21.819 h1.52
  text "PLOT NAME =" at -6.144,-27.034 h1.52
  text ".plot_File_Name" at 14.316,-27.034 h1.52
  text "GENERATED    :" at 56.81,-27.034 h1.52
  text ".Print_Date" at 78.895,-27.034 h1.52
  text ".Print_Time" at 97.412,-27.034 h1.52
  text "TEXAS INSTRUMENTS" at 129.53,-27.034 h1.52
M12 Stackup:
  drawing of 295 lines, arcs and shapes, not listed
  text "Layer" at 20.309,155.27 h1.52
  text "Name" at 30.721,155.27 h1.52
  text "Material" at 54.337,155.27 h1.52
  text "Thickness" at 76.175,155.27 h1.52
  text "Constant" at 92.68,155.27 h1.52
  text "Board Layer Stack" at 107.155,155.27 h1.52
  text "Top Overlay" at 30.721,152.222 h1.52
  text "Top Solder" at 30.721,149.174 h1.52
  text "Solder Resist" at 54.337,149.174 h1.52
  text "0.40mil" at 76.175,149.174 h1.52
  text "3.5" at 92.68,149.174 h1.52
  text "1" at 20.309,146.126 h1.52
  text "Top Layer" at 30.721,146.126 h1.52
  text "2.76mil" at 76.175,146.126 h1.52
  text "Dielectric1" at 30.721,143.078 h1.52
  text "FR-4 High Tg" at 54.337,143.078 h1.52
  text "59.20mil" at 76.175,143.078 h1.52
  text "4.8" at 92.68,143.078 h1.52
  text "2" at 20.309,140.03 h1.52
  text "Mid-Layer 1" at 30.721,140.03 h1.52
  text "1.40mil" at 76.175,140.03 h1.52
  text "Dielectric2" at 30.721,136.982 h1.52
  text "FR-4" at 54.337,136.982 h1.52
  text "12.60mil" at 76.175,136.982 h1.52
  text "4.8" at 92.68,136.982 h1.52
  text "3" at 20.309,133.934 h1.52
  text "Mid-Layer 2" at 30.721,133.934 h1.52
  text "1.40mil" at 76.175,133.934 h1.52
  text "Dielectric3" at 30.721,130.886 h1.52
  text "FR-4" at 54.337,130.886 h1.52
  text "12.60mil" at 76.175,130.886 h1.52
  text "4.8" at 92.68,130.886 h1.52
  text "4" at 20.309,127.838 h1.52
  text "Bottom Layer" at 30.721,127.838 h1.52
  text "2.76mil" at 76.175,127.838 h1.52
  text "Bottom Solder" at 30.721,124.79 h1.52
  text "Solder Resist" at 54.337,124.79 h1.52
  text "0.40mil" at 76.175,124.79 h1.52
  text "3.5" at 92.68,124.79 h1.52
  text "Bottom Overlay" at 30.721,121.742 h1.52
  text ".Layer_Name" at 14.316,-21.806 h1.52
M13 Component Bodies Top:
  text ".Layer_Name" at 14.316,-21.806 h1.52
M14 Component Bodies Bottom:
  text ".Layer_Name" at 14.316,-21.806 h1.52
M15 Courtyards Top:
  text ".Layer_Name" at 14.316,-21.806 h1.52
M16 Courtyards Bottom:
  text ".Layer_Name" at 14.316,-21.806 h1.52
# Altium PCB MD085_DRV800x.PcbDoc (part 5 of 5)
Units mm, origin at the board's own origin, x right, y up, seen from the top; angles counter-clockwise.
Board outline 152.66 x 101.89 mm, 4 copper layers (Top Layer, Mid-Layer 1, Mid-Layer 2, Bottom Layer), stack 2.355 mm thick; 265 components, 148 nets, 849 pads, 1494 vias.
Unrouted connection lines stored in the file: 2.

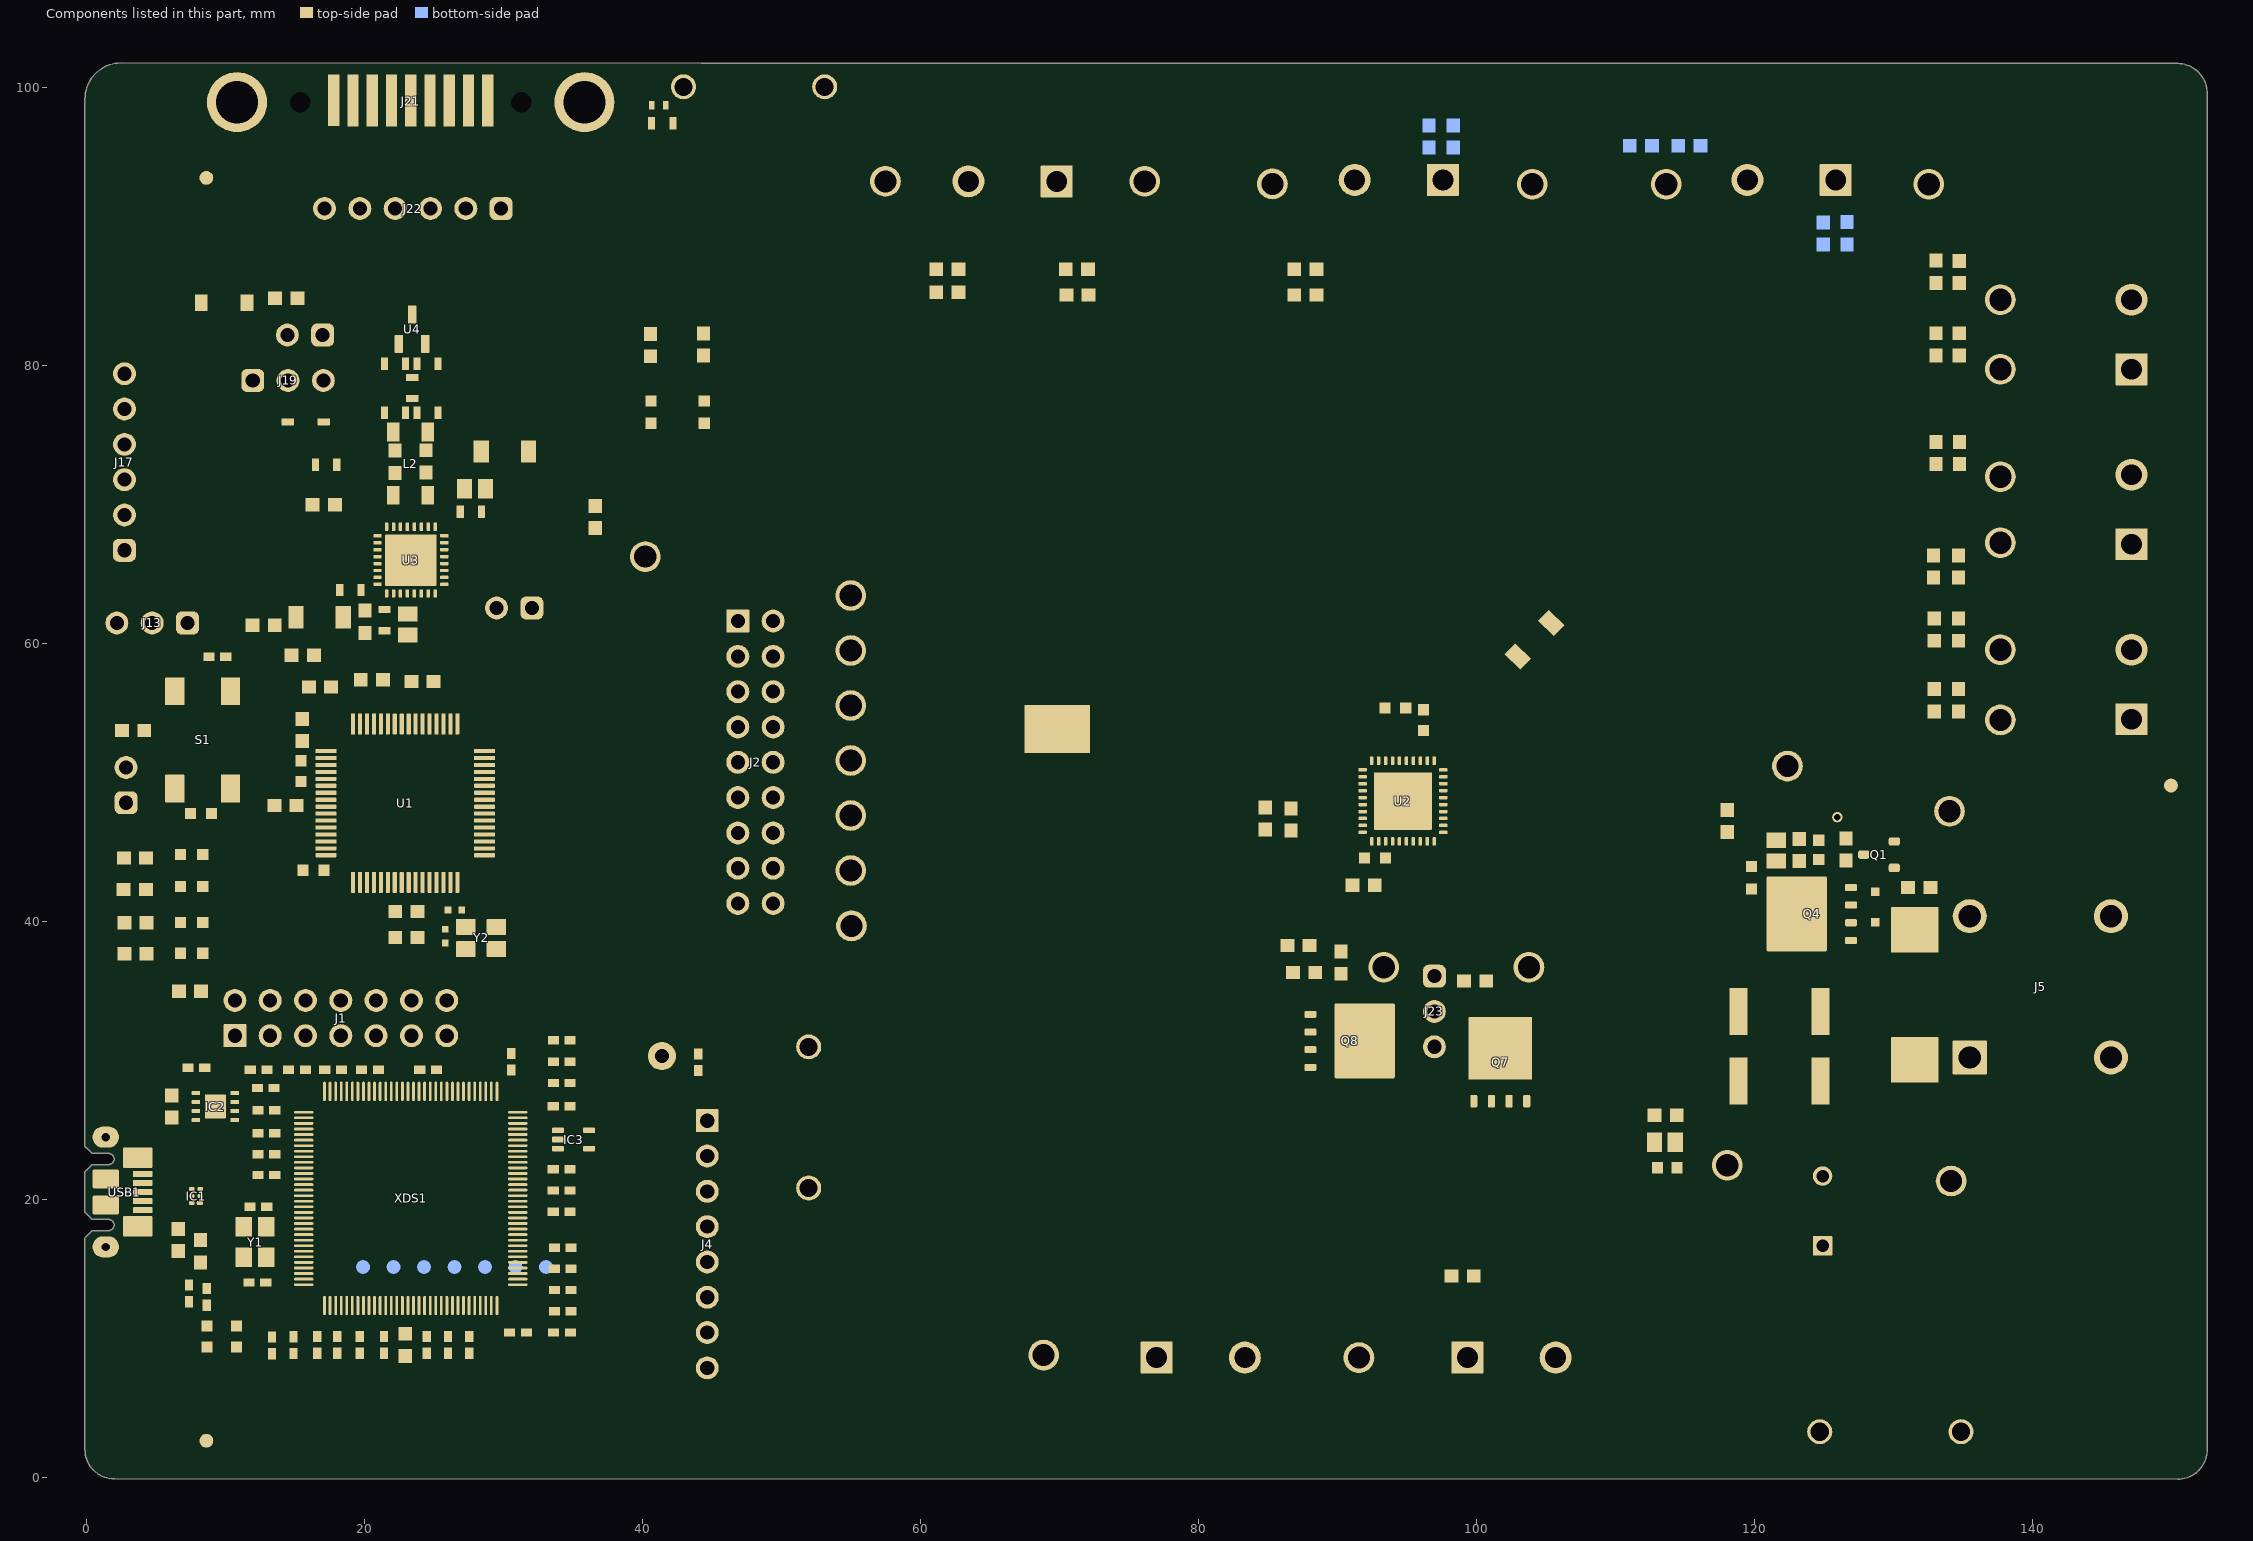
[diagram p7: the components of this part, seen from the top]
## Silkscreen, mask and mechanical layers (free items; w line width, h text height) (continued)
Drill Drawing:
  circle w0.254: c182.822,51.685 r0.421
  circle w0.254: c182.822,51.685 r0.702
  circle w0.254: c182.822,32.738 r0.702
  lines w0.254: 182.121,30.282 183.524,30.282 182.822,28.879 182.121,30.282 ; 182.121,35.545 182.472,35.545 182.472,35.194 183.173,35.194 183.173,35.545 183.524,35.545 183.524,36.247 183.173,36.247 183.173,36.598 182.472,36.598 182.472,36.247 182.121,36.247 182.121,35.545 ; 182.121,41.51 182.822,41.861 183.524,41.51 183.173,42.212 183.524,42.913 182.822,42.562 182.121,42.913 182.472,42.212 182.121,41.51 ; 182.121,45.018 182.472,45.018 182.822,44.668 183.173,45.018 183.524,45.018 183.173,45.369 183.524,45.72 183.173,45.72 182.822,46.071 182.472,45.72 182.121,45.72 182.472,45.369 182.121,45.018 ; 182.121,48.176 182.472,48.176 182.472,47.825 183.173,47.825 183.173,48.176 183.524,48.176 183.524,48.878 183.173,48.878 183.173,49.229 182.472,49.229 182.472,48.878 182.121,48.878 182.121,48.176 ; 182.121,54.141 183.524,54.141 183.524,55.544 182.121,55.544 182.121,54.141 ; 182.121,58.702 183.524,58.702 182.822,57.298 182.121,58.702 ; 182.121,64.316 182.822,63.614 183.524,64.316 182.822,65.017 182.121,64.316 ; 182.121,66.772 182.121,67.123 182.472,67.473 182.121,67.824 182.121,68.175 182.472,68.175 182.822,67.824 183.173,68.175 183.524,68.175 183.524,67.824 183.173,67.473 183.524,67.123 183.524,66.772 183.173,66.772 182.822,67.123 182.472,66.772 182.121,66.772 ; 182.121,69.929 182.822,70.28 183.524,69.929 183.173,70.631 183.524,71.333 182.822,70.982 182.121,71.333 182.472,70.631 182.121,69.929 ; 182.121,73.438 182.472,73.438 182.822,73.087 183.173,73.438 183.524,73.438 183.173,73.789 183.524,74.14 183.173,74.14 182.822,74.491 182.472,74.14 182.121,74.14 182.472,73.789 182.121,73.438 ; 182.401,41.791 182.822,42.001 183.243,41.791 183.033,42.212 183.243,42.633 182.822,42.422 182.401,42.633 182.612,42.212 182.401,41.791 ; 182.401,45.159 182.612,45.159 182.822,44.948 183.033,45.159 183.243,45.159 183.033,45.369 183.243,45.58 183.033,45.58 182.822,45.79 182.612,45.58 182.401,45.58 182.612,45.369 182.401,45.159 ; 182.401,48.316 182.612,48.316 182.612,48.106 183.033,48.106 183.033,48.316 183.243,48.316 183.243,48.738 183.033,48.738 183.033,48.948 182.612,48.948 182.612,48.738 182.401,48.738 182.401,48.316 ; 182.401,58.421 183.243,58.421 182.822,57.579 182.401,58.421
  lines w0.305: 180.848,27.932 262.928,27.932 ; 180.848,78.455 262.928,78.455 ; 189.43,24.774 189.43,81.613 ; 197.863,24.774 197.863,81.613 ; 214.032,24.774 214.032,81.613 ; 220.614,24.774 220.614,81.613 ; 230.143,24.774 230.143,81.613 ; 248.541,24.774 248.541,81.613 ; 180.848,24.774 262.928,24.774 262.928,81.613 180.848,81.613 180.848,24.774
  text "Symbol" at 182.743,79.403 h1.83
  text "Quantity" at 190.377,79.403 h1.83
  text "Finished Hole Size" at 198.81,79.403 h1.83
  text "Plated" at 214.979,79.403 h1.83
  text "Hole Type" at 221.561,79.403 h1.83
  text "Drill Layer Pair" at 231.09,79.403 h1.83
  text "Hole Tolerance" at 249.488,79.403 h1.83
  text "2" at 190.377,76.245 h1.52
  text "59.00mil (1.499mm)" at 198.81,76.245 h1.52
  text "NPTH" at 214.979,76.245 h1.52
  text "Round" at 221.561,76.245 h1.52
  text "Top Layer - Bottom Layer" at 231.09,76.245 h1.52
  text "C" at 182.101,75.991 h1.4
  text "1416" at 190.377,73.087 h1.52
  text "7.87mil (0.200mm)" at 198.81,73.087 h1.52
  text "PTH" at 214.979,73.087 h1.52
  text "Round" at 221.561,73.087 h1.52
  text "Top Layer - Bottom Layer" at 231.09,73.087 h1.52
  text "49" at 190.377,69.929 h1.52
  text "8.00mil (0.203mm)" at 198.81,69.929 h1.52
  text "PTH" at 214.979,69.929 h1.52
  text "Round" at 221.561,69.929 h1.52
  text "Top Layer - Bottom Layer" at 231.09,69.929 h1.52
  text "10" at 190.377,66.772 h1.52
  text "14.00mil (0.356mm)" at 198.81,66.772 h1.52
  text "PTH" at 214.979,66.772 h1.52
  text "Round" at 221.561,66.772 h1.52
  text "Top Layer - Bottom Layer" at 231.09,66.772 h1.52
  text "15" at 190.377,63.614 h1.52
  text "16.00mil (0.406mm)" at 198.81,63.614 h1.52
  text "PTH" at 214.979,63.614 h1.52
  text "Round" at 221.561,63.614 h1.52
  text "Top Layer - Bottom Layer" at 231.09,63.614 h1.52
  text "1" at 190.377,60.456 h1.52
  text "17.72mil (0.450mm)" at 198.81,60.456 h1.52
  text "PTH" at 214.979,60.456 h1.52
  text "Round" at 221.561,60.456 h1.52
  text "Top Layer - Bottom Layer" at 231.09,60.456 h1.52
  text "B" at 182.101,60.202 h1.4
  text "2" at 190.377,57.298 h1.52
  text "35.43mil (0.900mm)" at 198.81,57.298 h1.52
  text "PTH" at 214.979,57.298 h1.52
  text "Round" at 221.561,57.298 h1.52
  text "Top Layer - Bottom Layer" at 231.09,57.298 h1.52
  text "68" at 190.377,54.141 h1.52
  text "40.00mil (1.016mm)" at 198.81,54.141 h1.52
  text "PTH" at 214.979,54.141 h1.52
  text "Round" at 221.561,54.141 h1.52
  text "Top Layer - Bottom Layer" at 231.09,54.141 h1.52
  text "6" at 190.377,50.983 h1.52
  text "51.18mil (1.300mm)" at 198.81,50.983 h1.52
  text "PTH" at 214.979,50.983 h1.52
  text "Round" at 221.561,50.983 h1.52
  text "Top Layer - Bottom Layer" at 231.09,50.983 h1.52
  text "16" at 190.377,47.825 h1.52
  text "59.06mil (1.500mm)" at 198.81,47.825 h1.52
  text "PTH" at 214.979,47.825 h1.52
  text "Round" at 221.561,47.825 h1.52
  text "Top Layer - Bottom Layer" at 231.09,47.825 h1.52
  text "4" at 190.377,44.668 h1.52
  text "62.99mil (1.600mm)" at 198.81,44.668 h1.52
  text "PTH" at 214.979,44.668 h1.52
  text "Round" at 221.561,44.668 h1.52
  text "Top Layer - Bottom Layer" at 231.09,44.668 h1.52
  text "28" at 190.377,41.51 h1.52
  text "63.00mil (1.600mm)" at 198.81,41.51 h1.52
  text "PTH" at 214.979,41.51 h1.52
  text "Round" at 221.561,41.51 h1.52
  text "Top Layer - Bottom Layer" at 231.09,41.51 h1.52
  text "2" at 190.377,38.352 h1.52
  text "120.00mil (3.048mm)" at 198.81,38.352 h1.52
  text "PTH" at 214.979,38.352 h1.52
  text "Round" at 221.561,38.352 h1.52
  text "Top Layer - Bottom Layer" at 231.09,38.352 h1.52
  text "A" at 182.101,38.098 h1.4
  text "3" at 190.377,35.194 h1.52
  text "169.29mil (4.300mm)" at 198.81,35.194 h1.52
  text "PTH" at 214.979,35.194 h1.52
  text "Round" at 221.561,35.194 h1.52
  text "Top Layer - Bottom Layer" at 231.09,35.194 h1.52
  text "1" at 190.377,32.037 h1.52
  text "177.17mil (4.500mm)" at 198.81,32.037 h1.52
  text "PTH" at 214.979,32.037 h1.52
  text "Round" at 221.561,32.037 h1.52
  text "Top Layer - Bottom Layer" at 231.09,32.037 h1.52
  text "2" at 190.377,28.879 h1.52
  text "23.62mil (0.600mm)" at 198.81,28.879 h1.52
  text "PTH" at 214.979,28.879 h1.52
  text "Slot" at 221.561,28.879 h1.52
  text "Top Layer - Bottom Layer" at 231.09,28.879 h1.52
  text "1625 Total" at 190.377,25.721 h1.52
  text "Slot definitions :" at 182.743,23.511 h1.52
  text "Routed Path Length" at 194.191,23.511 h1.52
  text "= Calculated from tool start centre position to tool end centre position." at 207.901,23.511 h1.52
  text "Hole Length" at 194.191,22.248 h1.52
  text "= Routed Path Length + Tool Size = Slot length as defined in the PCB layout" at 202.826,22.248 h1.52
  text ".Layer_Name" at 14.316,-21.806 h1.52
M17 Embedded Cavity:
  text ".Layer_Name" at 14.316,-21.806 h1.52
M18 Embedded Assembly:
  text ".Layer_Name" at 14.316,-21.806 h1.52
M19 Embedded Keepout:
  text ".Layer_Name" at 14.316,-21.806 h1.52

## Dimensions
-0.34,-10.16 to 25.06,-10.16 on M2 Board Dimensions
0,0 to 0,101.6 on M2 Board Dimensions
0,0 to 152.4,0 on M2 Board Dimensions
